VERSION 5.8 ;
BUSBITCHARS "[]" ;
DIVIDERCHAR "/" ;
UNITS
    DATABASE MICRONS 1000 ;
END UNITS

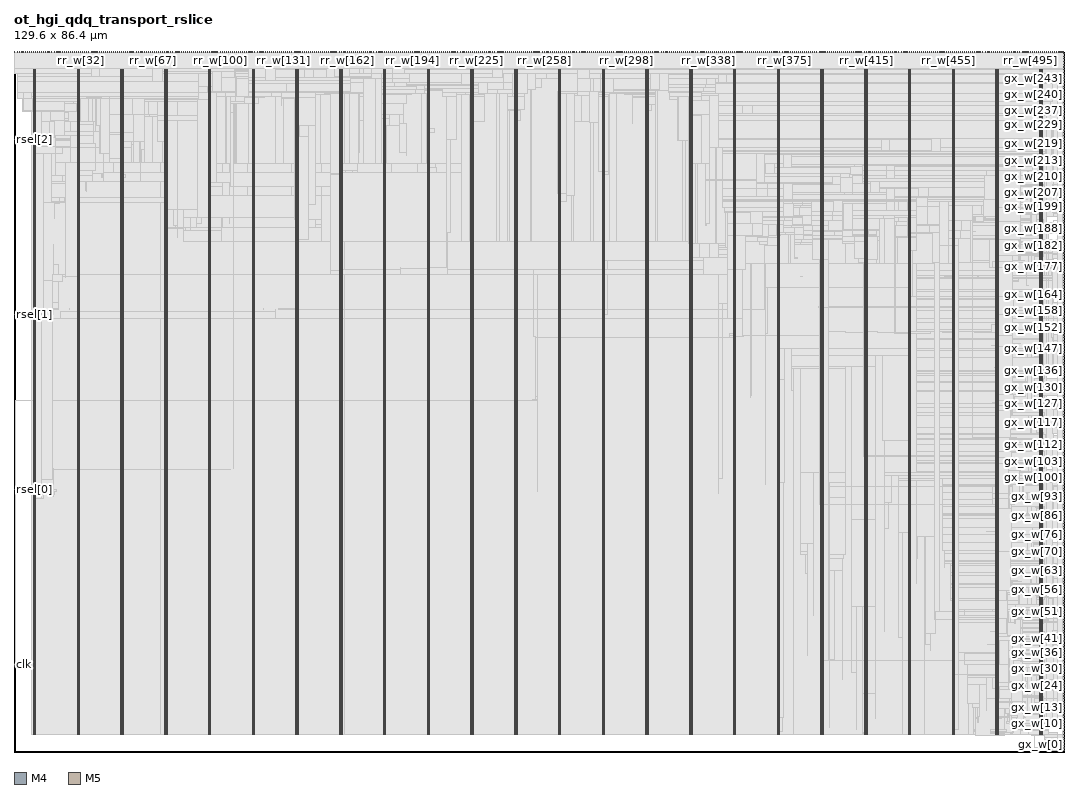
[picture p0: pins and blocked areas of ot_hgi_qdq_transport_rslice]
MACRO ot_hgi_qdq_transport_rslice
  FOREIGN ot_hgi_qdq_transport_rslice 0 0 ;
  CLASS BLOCK ;
  SIZE 129.6 BY 86.4 ;
  PIN clk
    DIRECTION INPUT ;
    USE SIGNAL ;
    PORT
      LAYER M4 ;
        RECT  0 10.8 0.084 10.824 ;
    END
    PORT
      LAYER M4 ;
        RECT  0.06 10.8 0.227 10.824 ;
    END
  END clk
  PIN gx_w[0]
    DIRECTION OUTPUT ;
    USE SIGNAL ;
    PORT
      LAYER M4 ;
        RECT  129.516 0.144 129.6 0.168 ;
    END
  END gx_w[0]
  PIN gx_w[100]
    DIRECTION OUTPUT ;
    USE SIGNAL ;
    PORT
      LAYER M4 ;
        RECT  129.516 33.888 129.6 33.912 ;
    END
  END gx_w[100]
  PIN gx_w[101]
    DIRECTION OUTPUT ;
    USE SIGNAL ;
    PORT
      LAYER M4 ;
        RECT  129.516 34.224 129.6 34.248 ;
    END
  END gx_w[101]
  PIN gx_w[102]
    DIRECTION OUTPUT ;
    USE SIGNAL ;
    PORT
      LAYER M4 ;
        RECT  129.516 34.56 129.6 34.584 ;
    END
  END gx_w[102]
  PIN gx_w[103]
    DIRECTION OUTPUT ;
    USE SIGNAL ;
    PORT
      LAYER M4 ;
        RECT  129.516 34.896 129.6 34.92 ;
    END
  END gx_w[103]
  PIN gx_w[104]
    DIRECTION OUTPUT ;
    USE SIGNAL ;
    PORT
      LAYER M4 ;
        RECT  129.516 35.28 129.6 35.304 ;
    END
  END gx_w[104]
  PIN gx_w[105]
    DIRECTION OUTPUT ;
    USE SIGNAL ;
    PORT
      LAYER M4 ;
        RECT  129.516 35.616 129.6 35.64 ;
    END
  END gx_w[105]
  PIN gx_w[106]
    DIRECTION OUTPUT ;
    USE SIGNAL ;
    PORT
      LAYER M4 ;
        RECT  129.516 35.952 129.6 35.976 ;
    END
  END gx_w[106]
  PIN gx_w[107]
    DIRECTION OUTPUT ;
    USE SIGNAL ;
    PORT
      LAYER M4 ;
        RECT  129.516 36.288 129.6 36.312 ;
    END
  END gx_w[107]
  PIN gx_w[108]
    DIRECTION OUTPUT ;
    USE SIGNAL ;
    PORT
      LAYER M4 ;
        RECT  129.516 36.624 129.6 36.648 ;
    END
  END gx_w[108]
  PIN gx_w[109]
    DIRECTION OUTPUT ;
    USE SIGNAL ;
    PORT
      LAYER M4 ;
        RECT  129.516 36.96 129.6 36.984 ;
    END
  END gx_w[109]
  PIN gx_w[10]
    DIRECTION OUTPUT ;
    USE SIGNAL ;
    PORT
      LAYER M4 ;
        RECT  129.516 3.552 129.6 3.576 ;
    END
  END gx_w[10]
  PIN gx_w[110]
    DIRECTION OUTPUT ;
    USE SIGNAL ;
    PORT
      LAYER M4 ;
        RECT  129.516 37.296 129.6 37.32 ;
    END
  END gx_w[110]
  PIN gx_w[111]
    DIRECTION OUTPUT ;
    USE SIGNAL ;
    PORT
      LAYER M4 ;
        RECT  129.516 37.632 129.6 37.656 ;
    END
  END gx_w[111]
  PIN gx_w[112]
    DIRECTION OUTPUT ;
    USE SIGNAL ;
    PORT
      LAYER M4 ;
        RECT  129.516 37.968 129.6 37.992 ;
    END
  END gx_w[112]
  PIN gx_w[113]
    DIRECTION OUTPUT ;
    USE SIGNAL ;
    PORT
      LAYER M4 ;
        RECT  129.516 38.304 129.6 38.328 ;
    END
  END gx_w[113]
  PIN gx_w[114]
    DIRECTION OUTPUT ;
    USE SIGNAL ;
    PORT
      LAYER M4 ;
        RECT  129.516 38.64 129.6 38.664 ;
    END
  END gx_w[114]
  PIN gx_w[115]
    DIRECTION OUTPUT ;
    USE SIGNAL ;
    PORT
      LAYER M4 ;
        RECT  129.516 38.976 129.6 39 ;
    END
  END gx_w[115]
  PIN gx_w[116]
    DIRECTION OUTPUT ;
    USE SIGNAL ;
    PORT
      LAYER M4 ;
        RECT  129.516 39.312 129.6 39.336 ;
    END
  END gx_w[116]
  PIN gx_w[117]
    DIRECTION OUTPUT ;
    USE SIGNAL ;
    PORT
      LAYER M4 ;
        RECT  129.516 39.648 129.6 39.672 ;
    END
  END gx_w[117]
  PIN gx_w[118]
    DIRECTION OUTPUT ;
    USE SIGNAL ;
    PORT
      LAYER M4 ;
        RECT  129.516 39.984 129.6 40.008 ;
    END
  END gx_w[118]
  PIN gx_w[119]
    DIRECTION OUTPUT ;
    USE SIGNAL ;
    PORT
      LAYER M4 ;
        RECT  129.516 40.32 129.6 40.344 ;
    END
  END gx_w[119]
  PIN gx_w[11]
    DIRECTION OUTPUT ;
    USE SIGNAL ;
    PORT
      LAYER M4 ;
        RECT  129.516 3.888 129.6 3.912 ;
    END
  END gx_w[11]
  PIN gx_w[120]
    DIRECTION OUTPUT ;
    USE SIGNAL ;
    PORT
      LAYER M4 ;
        RECT  129.516 40.656 129.6 40.68 ;
    END
  END gx_w[120]
  PIN gx_w[121]
    DIRECTION OUTPUT ;
    USE SIGNAL ;
    PORT
      LAYER M4 ;
        RECT  129.516 40.992 129.6 41.016 ;
    END
  END gx_w[121]
  PIN gx_w[122]
    DIRECTION OUTPUT ;
    USE SIGNAL ;
    PORT
      LAYER M4 ;
        RECT  129.516 41.328 129.6 41.352 ;
    END
  END gx_w[122]
  PIN gx_w[123]
    DIRECTION OUTPUT ;
    USE SIGNAL ;
    PORT
      LAYER M4 ;
        RECT  129.516 41.664 129.6 41.688 ;
    END
  END gx_w[123]
  PIN gx_w[124]
    DIRECTION OUTPUT ;
    USE SIGNAL ;
    PORT
      LAYER M4 ;
        RECT  129.516 42 129.6 42.024 ;
    END
  END gx_w[124]
  PIN gx_w[125]
    DIRECTION OUTPUT ;
    USE SIGNAL ;
    PORT
      LAYER M4 ;
        RECT  129.516 42.336 129.6 42.36 ;
    END
  END gx_w[125]
  PIN gx_w[126]
    DIRECTION OUTPUT ;
    USE SIGNAL ;
    PORT
      LAYER M4 ;
        RECT  129.516 42.672 129.6 42.696 ;
    END
  END gx_w[126]
  PIN gx_w[127]
    DIRECTION OUTPUT ;
    USE SIGNAL ;
    PORT
      LAYER M4 ;
        RECT  129.516 43.008 129.6 43.032 ;
    END
  END gx_w[127]
  PIN gx_w[128]
    DIRECTION OUTPUT ;
    USE SIGNAL ;
    PORT
      LAYER M4 ;
        RECT  129.516 43.344 129.6 43.368 ;
    END
  END gx_w[128]
  PIN gx_w[129]
    DIRECTION OUTPUT ;
    USE SIGNAL ;
    PORT
      LAYER M4 ;
        RECT  129.516 43.68 129.6 43.704 ;
    END
  END gx_w[129]
  PIN gx_w[12]
    DIRECTION OUTPUT ;
    USE SIGNAL ;
    PORT
      LAYER M4 ;
        RECT  129.516 4.224 129.6 4.248 ;
    END
  END gx_w[12]
  PIN gx_w[130]
    DIRECTION OUTPUT ;
    USE SIGNAL ;
    PORT
      LAYER M4 ;
        RECT  129.516 44.016 129.6 44.04 ;
    END
  END gx_w[130]
  PIN gx_w[131]
    DIRECTION OUTPUT ;
    USE SIGNAL ;
    PORT
      LAYER M4 ;
        RECT  129.516 44.352 129.6 44.376 ;
    END
  END gx_w[131]
  PIN gx_w[132]
    DIRECTION OUTPUT ;
    USE SIGNAL ;
    PORT
      LAYER M4 ;
        RECT  129.516 44.688 129.6 44.712 ;
    END
  END gx_w[132]
  PIN gx_w[133]
    DIRECTION OUTPUT ;
    USE SIGNAL ;
    PORT
      LAYER M4 ;
        RECT  129.516 45.024 129.6 45.048 ;
    END
  END gx_w[133]
  PIN gx_w[134]
    DIRECTION OUTPUT ;
    USE SIGNAL ;
    PORT
      LAYER M4 ;
        RECT  129.516 45.36 129.6 45.384 ;
    END
  END gx_w[134]
  PIN gx_w[135]
    DIRECTION OUTPUT ;
    USE SIGNAL ;
    PORT
      LAYER M4 ;
        RECT  129.516 45.696 129.6 45.72 ;
    END
  END gx_w[135]
  PIN gx_w[136]
    DIRECTION OUTPUT ;
    USE SIGNAL ;
    PORT
      LAYER M4 ;
        RECT  129.516 46.08 129.6 46.104 ;
    END
  END gx_w[136]
  PIN gx_w[137]
    DIRECTION OUTPUT ;
    USE SIGNAL ;
    PORT
      LAYER M4 ;
        RECT  129.516 46.416 129.6 46.44 ;
    END
  END gx_w[137]
  PIN gx_w[138]
    DIRECTION OUTPUT ;
    USE SIGNAL ;
    PORT
      LAYER M4 ;
        RECT  129.516 46.752 129.6 46.776 ;
    END
  END gx_w[138]
  PIN gx_w[139]
    DIRECTION OUTPUT ;
    USE SIGNAL ;
    PORT
      LAYER M4 ;
        RECT  129.516 47.088 129.6 47.112 ;
    END
  END gx_w[139]
  PIN gx_w[13]
    DIRECTION OUTPUT ;
    USE SIGNAL ;
    PORT
      LAYER M4 ;
        RECT  129.516 4.56 129.6 4.584 ;
    END
  END gx_w[13]
  PIN gx_w[140]
    DIRECTION OUTPUT ;
    USE SIGNAL ;
    PORT
      LAYER M4 ;
        RECT  129.516 47.424 129.6 47.448 ;
    END
  END gx_w[140]
  PIN gx_w[141]
    DIRECTION OUTPUT ;
    USE SIGNAL ;
    PORT
      LAYER M4 ;
        RECT  129.516 47.76 129.6 47.784 ;
    END
  END gx_w[141]
  PIN gx_w[142]
    DIRECTION OUTPUT ;
    USE SIGNAL ;
    PORT
      LAYER M4 ;
        RECT  129.516 48.096 129.6 48.12 ;
    END
  END gx_w[142]
  PIN gx_w[143]
    DIRECTION OUTPUT ;
    USE SIGNAL ;
    PORT
      LAYER M4 ;
        RECT  129.516 48.432 129.6 48.456 ;
    END
  END gx_w[143]
  PIN gx_w[144]
    DIRECTION OUTPUT ;
    USE SIGNAL ;
    PORT
      LAYER M4 ;
        RECT  129.516 48.768 129.6 48.792 ;
    END
  END gx_w[144]
  PIN gx_w[145]
    DIRECTION OUTPUT ;
    USE SIGNAL ;
    PORT
      LAYER M4 ;
        RECT  129.516 49.104 129.6 49.128 ;
    END
  END gx_w[145]
  PIN gx_w[146]
    DIRECTION OUTPUT ;
    USE SIGNAL ;
    PORT
      LAYER M4 ;
        RECT  129.516 49.44 129.6 49.464 ;
    END
  END gx_w[146]
  PIN gx_w[147]
    DIRECTION OUTPUT ;
    USE SIGNAL ;
    PORT
      LAYER M4 ;
        RECT  129.516 49.776 129.6 49.8 ;
    END
  END gx_w[147]
  PIN gx_w[148]
    DIRECTION OUTPUT ;
    USE SIGNAL ;
    PORT
      LAYER M4 ;
        RECT  129.516 50.112 129.6 50.136 ;
    END
  END gx_w[148]
  PIN gx_w[149]
    DIRECTION OUTPUT ;
    USE SIGNAL ;
    PORT
      LAYER M4 ;
        RECT  129.516 50.448 129.6 50.472 ;
    END
  END gx_w[149]
  PIN gx_w[14]
    DIRECTION OUTPUT ;
    USE SIGNAL ;
    PORT
      LAYER M4 ;
        RECT  129.516 4.896 129.6 4.92 ;
    END
  END gx_w[14]
  PIN gx_w[150]
    DIRECTION OUTPUT ;
    USE SIGNAL ;
    PORT
      LAYER M4 ;
        RECT  129.516 50.784 129.6 50.808 ;
    END
  END gx_w[150]
  PIN gx_w[151]
    DIRECTION OUTPUT ;
    USE SIGNAL ;
    PORT
      LAYER M4 ;
        RECT  129.516 51.12 129.6 51.144 ;
    END
  END gx_w[151]
  PIN gx_w[152]
    DIRECTION OUTPUT ;
    USE SIGNAL ;
    PORT
      LAYER M4 ;
        RECT  129.516 51.456 129.6 51.48 ;
    END
  END gx_w[152]
  PIN gx_w[153]
    DIRECTION OUTPUT ;
    USE SIGNAL ;
    PORT
      LAYER M4 ;
        RECT  129.516 51.792 129.6 51.816 ;
    END
  END gx_w[153]
  PIN gx_w[154]
    DIRECTION OUTPUT ;
    USE SIGNAL ;
    PORT
      LAYER M4 ;
        RECT  129.516 52.128 129.6 52.152 ;
    END
  END gx_w[154]
  PIN gx_w[155]
    DIRECTION OUTPUT ;
    USE SIGNAL ;
    PORT
      LAYER M4 ;
        RECT  129.516 52.464 129.6 52.488 ;
    END
  END gx_w[155]
  PIN gx_w[156]
    DIRECTION OUTPUT ;
    USE SIGNAL ;
    PORT
      LAYER M4 ;
        RECT  129.516 52.8 129.6 52.824 ;
    END
  END gx_w[156]
  PIN gx_w[157]
    DIRECTION OUTPUT ;
    USE SIGNAL ;
    PORT
      LAYER M4 ;
        RECT  129.516 53.136 129.6 53.16 ;
    END
  END gx_w[157]
  PIN gx_w[158]
    DIRECTION OUTPUT ;
    USE SIGNAL ;
    PORT
      LAYER M4 ;
        RECT  129.516 53.472 129.6 53.496 ;
    END
  END gx_w[158]
  PIN gx_w[159]
    DIRECTION OUTPUT ;
    USE SIGNAL ;
    PORT
      LAYER M4 ;
        RECT  129.516 53.808 129.6 53.832 ;
    END
  END gx_w[159]
  PIN gx_w[15]
    DIRECTION OUTPUT ;
    USE SIGNAL ;
    PORT
      LAYER M4 ;
        RECT  129.516 5.232 129.6 5.256 ;
    END
  END gx_w[15]
  PIN gx_w[160]
    DIRECTION OUTPUT ;
    USE SIGNAL ;
    PORT
      LAYER M4 ;
        RECT  129.516 54.144 129.6 54.168 ;
    END
  END gx_w[160]
  PIN gx_w[161]
    DIRECTION OUTPUT ;
    USE SIGNAL ;
    PORT
      LAYER M4 ;
        RECT  129.516 54.48 129.6 54.504 ;
    END
  END gx_w[161]
  PIN gx_w[162]
    DIRECTION OUTPUT ;
    USE SIGNAL ;
    PORT
      LAYER M4 ;
        RECT  129.516 54.816 129.6 54.84 ;
    END
  END gx_w[162]
  PIN gx_w[163]
    DIRECTION OUTPUT ;
    USE SIGNAL ;
    PORT
      LAYER M4 ;
        RECT  129.516 55.152 129.6 55.176 ;
    END
  END gx_w[163]
  PIN gx_w[164]
    DIRECTION OUTPUT ;
    USE SIGNAL ;
    PORT
      LAYER M4 ;
        RECT  129.516 55.488 129.6 55.512 ;
    END
  END gx_w[164]
  PIN gx_w[165]
    DIRECTION OUTPUT ;
    USE SIGNAL ;
    PORT
      LAYER M4 ;
        RECT  129.516 55.824 129.6 55.848 ;
    END
  END gx_w[165]
  PIN gx_w[166]
    DIRECTION OUTPUT ;
    USE SIGNAL ;
    PORT
      LAYER M4 ;
        RECT  129.516 56.16 129.6 56.184 ;
    END
  END gx_w[166]
  PIN gx_w[167]
    DIRECTION OUTPUT ;
    USE SIGNAL ;
    PORT
      LAYER M4 ;
        RECT  129.516 56.496 129.6 56.52 ;
    END
  END gx_w[167]
  PIN gx_w[168]
    DIRECTION OUTPUT ;
    USE SIGNAL ;
    PORT
      LAYER M4 ;
        RECT  129.516 56.88 129.6 56.904 ;
    END
  END gx_w[168]
  PIN gx_w[169]
    DIRECTION OUTPUT ;
    USE SIGNAL ;
    PORT
      LAYER M4 ;
        RECT  129.516 57.216 129.6 57.24 ;
    END
  END gx_w[169]
  PIN gx_w[16]
    DIRECTION OUTPUT ;
    USE SIGNAL ;
    PORT
      LAYER M4 ;
        RECT  129.516 5.568 129.6 5.592 ;
    END
  END gx_w[16]
  PIN gx_w[170]
    DIRECTION OUTPUT ;
    USE SIGNAL ;
    PORT
      LAYER M4 ;
        RECT  129.516 57.552 129.6 57.576 ;
    END
  END gx_w[170]
  PIN gx_w[171]
    DIRECTION OUTPUT ;
    USE SIGNAL ;
    PORT
      LAYER M4 ;
        RECT  129.516 57.888 129.6 57.912 ;
    END
  END gx_w[171]
  PIN gx_w[172]
    DIRECTION OUTPUT ;
    USE SIGNAL ;
    PORT
      LAYER M4 ;
        RECT  129.516 58.224 129.6 58.248 ;
    END
  END gx_w[172]
  PIN gx_w[173]
    DIRECTION OUTPUT ;
    USE SIGNAL ;
    PORT
      LAYER M4 ;
        RECT  129.516 58.56 129.6 58.584 ;
    END
  END gx_w[173]
  PIN gx_w[174]
    DIRECTION OUTPUT ;
    USE SIGNAL ;
    PORT
      LAYER M4 ;
        RECT  129.516 58.896 129.6 58.92 ;
    END
  END gx_w[174]
  PIN gx_w[175]
    DIRECTION OUTPUT ;
    USE SIGNAL ;
    PORT
      LAYER M4 ;
        RECT  129.516 59.232 129.6 59.256 ;
    END
  END gx_w[175]
  PIN gx_w[176]
    DIRECTION OUTPUT ;
    USE SIGNAL ;
    PORT
      LAYER M4 ;
        RECT  129.516 59.568 129.6 59.592 ;
    END
  END gx_w[176]
  PIN gx_w[177]
    DIRECTION OUTPUT ;
    USE SIGNAL ;
    PORT
      LAYER M4 ;
        RECT  129.516 59.904 129.6 59.928 ;
    END
  END gx_w[177]
  PIN gx_w[178]
    DIRECTION OUTPUT ;
    USE SIGNAL ;
    PORT
      LAYER M4 ;
        RECT  129.516 60.24 129.6 60.264 ;
    END
  END gx_w[178]
  PIN gx_w[179]
    DIRECTION OUTPUT ;
    USE SIGNAL ;
    PORT
      LAYER M4 ;
        RECT  129.516 60.576 129.6 60.6 ;
    END
  END gx_w[179]
  PIN gx_w[17]
    DIRECTION OUTPUT ;
    USE SIGNAL ;
    PORT
      LAYER M4 ;
        RECT  129.516 5.904 129.6 5.928 ;
    END
  END gx_w[17]
  PIN gx_w[180]
    DIRECTION OUTPUT ;
    USE SIGNAL ;
    PORT
      LAYER M4 ;
        RECT  129.516 60.912 129.6 60.936 ;
    END
  END gx_w[180]
  PIN gx_w[181]
    DIRECTION OUTPUT ;
    USE SIGNAL ;
    PORT
      LAYER M4 ;
        RECT  129.516 61.248 129.6 61.272 ;
    END
  END gx_w[181]
  PIN gx_w[182]
    DIRECTION OUTPUT ;
    USE SIGNAL ;
    PORT
      LAYER M4 ;
        RECT  129.516 61.584 129.6 61.608 ;
    END
  END gx_w[182]
  PIN gx_w[183]
    DIRECTION OUTPUT ;
    USE SIGNAL ;
    PORT
      LAYER M4 ;
        RECT  129.516 61.92 129.6 61.944 ;
    END
  END gx_w[183]
  PIN gx_w[184]
    DIRECTION OUTPUT ;
    USE SIGNAL ;
    PORT
      LAYER M4 ;
        RECT  129.516 62.256 129.6 62.28 ;
    END
  END gx_w[184]
  PIN gx_w[185]
    DIRECTION OUTPUT ;
    USE SIGNAL ;
    PORT
      LAYER M4 ;
        RECT  129.516 62.592 129.6 62.616 ;
    END
  END gx_w[185]
  PIN gx_w[186]
    DIRECTION OUTPUT ;
    USE SIGNAL ;
    PORT
      LAYER M4 ;
        RECT  129.516 62.928 129.6 62.952 ;
    END
  END gx_w[186]
  PIN gx_w[187]
    DIRECTION OUTPUT ;
    USE SIGNAL ;
    PORT
      LAYER M4 ;
        RECT  129.516 63.264 129.6 63.288 ;
    END
  END gx_w[187]
  PIN gx_w[188]
    DIRECTION OUTPUT ;
    USE SIGNAL ;
    PORT
      LAYER M4 ;
        RECT  129.516 63.6 129.6 63.624 ;
    END
  END gx_w[188]
  PIN gx_w[189]
    DIRECTION OUTPUT ;
    USE SIGNAL ;
    PORT
      LAYER M4 ;
        RECT  129.516 63.936 129.6 63.96 ;
    END
  END gx_w[189]
  PIN gx_w[18]
    DIRECTION OUTPUT ;
    USE SIGNAL ;
    PORT
      LAYER M4 ;
        RECT  129.516 6.24 129.6 6.264 ;
    END
  END gx_w[18]
  PIN gx_w[190]
    DIRECTION OUTPUT ;
    USE SIGNAL ;
    PORT
      LAYER M4 ;
        RECT  129.516 64.272 129.6 64.296 ;
    END
  END gx_w[190]
  PIN gx_w[191]
    DIRECTION OUTPUT ;
    USE SIGNAL ;
    PORT
      LAYER M4 ;
        RECT  129.516 64.608 129.6 64.632 ;
    END
  END gx_w[191]
  PIN gx_w[192]
    DIRECTION OUTPUT ;
    USE SIGNAL ;
    PORT
      LAYER M4 ;
        RECT  129.516 64.944 129.6 64.968 ;
    END
  END gx_w[192]
  PIN gx_w[193]
    DIRECTION OUTPUT ;
    USE SIGNAL ;
    PORT
      LAYER M4 ;
        RECT  129.516 65.28 129.6 65.304 ;
    END
  END gx_w[193]
  PIN gx_w[194]
    DIRECTION OUTPUT ;
    USE SIGNAL ;
    PORT
      LAYER M4 ;
        RECT  129.516 65.616 129.6 65.64 ;
    END
  END gx_w[194]
  PIN gx_w[195]
    DIRECTION OUTPUT ;
    USE SIGNAL ;
    PORT
      LAYER M4 ;
        RECT  129.516 65.952 129.6 65.976 ;
    END
  END gx_w[195]
  PIN gx_w[196]
    DIRECTION OUTPUT ;
    USE SIGNAL ;
    PORT
      LAYER M4 ;
        RECT  129.516 66.288 129.6 66.312 ;
    END
  END gx_w[196]
  PIN gx_w[197]
    DIRECTION OUTPUT ;
    USE SIGNAL ;
    PORT
      LAYER M4 ;
        RECT  129.516 66.624 129.6 66.648 ;
    END
  END gx_w[197]
  PIN gx_w[198]
    DIRECTION OUTPUT ;
    USE SIGNAL ;
    PORT
      LAYER M4 ;
        RECT  129.516 66.96 129.6 66.984 ;
    END
  END gx_w[198]
  PIN gx_w[199]
    DIRECTION OUTPUT ;
    USE SIGNAL ;
    PORT
      LAYER M4 ;
        RECT  129.516 67.296 129.6 67.32 ;
    END
  END gx_w[199]
  PIN gx_w[19]
    DIRECTION OUTPUT ;
    USE SIGNAL ;
    PORT
      LAYER M4 ;
        RECT  129.516 6.576 129.6 6.6 ;
    END
  END gx_w[19]
  PIN gx_w[1]
    DIRECTION OUTPUT ;
    USE SIGNAL ;
    PORT
      LAYER M4 ;
        RECT  129.516 0.48 129.6 0.504 ;
    END
  END gx_w[1]
  PIN gx_w[200]
    DIRECTION OUTPUT ;
    USE SIGNAL ;
    PORT
      LAYER M4 ;
        RECT  129.516 67.68 129.6 67.704 ;
    END
  END gx_w[200]
  PIN gx_w[201]
    DIRECTION OUTPUT ;
    USE SIGNAL ;
    PORT
      LAYER M4 ;
        RECT  129.516 68.016 129.6 68.04 ;
    END
  END gx_w[201]
  PIN gx_w[202]
    DIRECTION OUTPUT ;
    USE SIGNAL ;
    PORT
      LAYER M4 ;
        RECT  129.516 68.352 129.6 68.376 ;
    END
  END gx_w[202]
  PIN gx_w[203]
    DIRECTION OUTPUT ;
    USE SIGNAL ;
    PORT
      LAYER M4 ;
        RECT  129.516 68.688 129.6 68.712 ;
    END
  END gx_w[203]
  PIN gx_w[204]
    DIRECTION OUTPUT ;
    USE SIGNAL ;
    PORT
      LAYER M4 ;
        RECT  129.516 69.024 129.6 69.048 ;
    END
  END gx_w[204]
  PIN gx_w[205]
    DIRECTION OUTPUT ;
    USE SIGNAL ;
    PORT
      LAYER M4 ;
        RECT  129.516 69.36 129.6 69.384 ;
    END
  END gx_w[205]
  PIN gx_w[206]
    DIRECTION OUTPUT ;
    USE SIGNAL ;
    PORT
      LAYER M4 ;
        RECT  129.516 69.696 129.6 69.72 ;
    END
  END gx_w[206]
  PIN gx_w[207]
    DIRECTION OUTPUT ;
    USE SIGNAL ;
    PORT
      LAYER M4 ;
        RECT  129.516 70.032 129.6 70.056 ;
    END
  END gx_w[207]
  PIN gx_w[208]
    DIRECTION OUTPUT ;
    USE SIGNAL ;
    PORT
      LAYER M4 ;
        RECT  129.516 70.368 129.6 70.392 ;
    END
  END gx_w[208]
  PIN gx_w[209]
    DIRECTION OUTPUT ;
    USE SIGNAL ;
    PORT
      LAYER M4 ;
        RECT  129.516 70.704 129.6 70.728 ;
    END
  END gx_w[209]
  PIN gx_w[20]
    DIRECTION OUTPUT ;
    USE SIGNAL ;
    PORT
      LAYER M4 ;
        RECT  129.516 6.912 129.6 6.936 ;
    END
  END gx_w[20]
  PIN gx_w[210]
    DIRECTION OUTPUT ;
    USE SIGNAL ;
    PORT
      LAYER M4 ;
        RECT  129.516 71.04 129.6 71.064 ;
    END
  END gx_w[210]
  PIN gx_w[211]
    DIRECTION OUTPUT ;
    USE SIGNAL ;
    PORT
      LAYER M4 ;
        RECT  129.516 71.376 129.6 71.4 ;
    END
  END gx_w[211]
  PIN gx_w[212]
    DIRECTION OUTPUT ;
    USE SIGNAL ;
    PORT
      LAYER M4 ;
        RECT  129.516 71.712 129.6 71.736 ;
    END
  END gx_w[212]
  PIN gx_w[213]
    DIRECTION OUTPUT ;
    USE SIGNAL ;
    PORT
      LAYER M4 ;
        RECT  129.516 72.048 129.6 72.072 ;
    END
  END gx_w[213]
  PIN gx_w[214]
    DIRECTION OUTPUT ;
    USE SIGNAL ;
    PORT
      LAYER M4 ;
        RECT  129.516 72.384 129.6 72.408 ;
    END
  END gx_w[214]
  PIN gx_w[215]
    DIRECTION OUTPUT ;
    USE SIGNAL ;
    PORT
      LAYER M4 ;
        RECT  129.516 72.72 129.6 72.744 ;
    END
  END gx_w[215]
  PIN gx_w[216]
    DIRECTION OUTPUT ;
    USE SIGNAL ;
    PORT
      LAYER M4 ;
        RECT  129.516 73.056 129.6 73.08 ;
    END
  END gx_w[216]
  PIN gx_w[217]
    DIRECTION OUTPUT ;
    USE SIGNAL ;
    PORT
      LAYER M4 ;
        RECT  129.516 73.392 129.6 73.416 ;
    END
  END gx_w[217]
  PIN gx_w[218]
    DIRECTION OUTPUT ;
    USE SIGNAL ;
    PORT
      LAYER M4 ;
        RECT  129.516 73.728 129.6 73.752 ;
    END
  END gx_w[218]
  PIN gx_w[219]
    DIRECTION OUTPUT ;
    USE SIGNAL ;
    PORT
      LAYER M4 ;
        RECT  129.516 74.064 129.6 74.088 ;
    END
  END gx_w[219]
  PIN gx_w[21]
    DIRECTION OUTPUT ;
    USE SIGNAL ;
    PORT
      LAYER M4 ;
        RECT  129.516 7.248 129.6 7.272 ;
    END
  END gx_w[21]
  PIN gx_w[220]
    DIRECTION OUTPUT ;
    USE SIGNAL ;
    PORT
      LAYER M4 ;
        RECT  129.516 74.4 129.6 74.424 ;
    END
  END gx_w[220]
  PIN gx_w[221]
    DIRECTION OUTPUT ;
    USE SIGNAL ;
    PORT
      LAYER M4 ;
        RECT  129.516 74.736 129.6 74.76 ;
    END
  END gx_w[221]
  PIN gx_w[222]
    DIRECTION OUTPUT ;
    USE SIGNAL ;
    PORT
      LAYER M4 ;
        RECT  129.516 75.072 129.6 75.096 ;
    END
  END gx_w[222]
  PIN gx_w[223]
    DIRECTION OUTPUT ;
    USE SIGNAL ;
    PORT
      LAYER M4 ;
        RECT  129.516 75.408 129.6 75.432 ;
    END
  END gx_w[223]
  PIN gx_w[224]
    DIRECTION OUTPUT ;
    USE SIGNAL ;
    PORT
      LAYER M4 ;
        RECT  129.516 75.744 129.6 75.768 ;
    END
  END gx_w[224]
  PIN gx_w[225]
    DIRECTION OUTPUT ;
    USE SIGNAL ;
    PORT
      LAYER M4 ;
        RECT  129.516 76.08 129.6 76.104 ;
    END
  END gx_w[225]
  PIN gx_w[226]
    DIRECTION OUTPUT ;
    USE SIGNAL ;
    PORT
      LAYER M4 ;
        RECT  129.516 76.416 129.6 76.44 ;
    END
  END gx_w[226]
  PIN gx_w[227]
    DIRECTION OUTPUT ;
    USE SIGNAL ;
    PORT
      LAYER M4 ;
        RECT  129.516 76.752 129.6 76.776 ;
    END
  END gx_w[227]
  PIN gx_w[228]
    DIRECTION OUTPUT ;
    USE SIGNAL ;
    PORT
      LAYER M4 ;
        RECT  129.516 77.088 129.6 77.112 ;
    END
  END gx_w[228]
  PIN gx_w[229]
    DIRECTION OUTPUT ;
    USE SIGNAL ;
    PORT
      LAYER M4 ;
        RECT  129.516 77.424 129.6 77.448 ;
    END
  END gx_w[229]
  PIN gx_w[22]
    DIRECTION OUTPUT ;
    USE SIGNAL ;
    PORT
      LAYER M4 ;
        RECT  129.516 7.584 129.6 7.608 ;
    END
  END gx_w[22]
  PIN gx_w[230]
    DIRECTION OUTPUT ;
    USE SIGNAL ;
    PORT
      LAYER M4 ;
        RECT  129.516 77.76 129.6 77.784 ;
    END
  END gx_w[230]
  PIN gx_w[231]
    DIRECTION OUTPUT ;
    USE SIGNAL ;
    PORT
      LAYER M4 ;
        RECT  129.516 78.096 129.6 78.12 ;
    END
  END gx_w[231]
  PIN gx_w[232]
    DIRECTION OUTPUT ;
    USE SIGNAL ;
    PORT
      LAYER M4 ;
        RECT  129.516 78.48 129.6 78.504 ;
    END
  END gx_w[232]
  PIN gx_w[233]
    DIRECTION OUTPUT ;
    USE SIGNAL ;
    PORT
      LAYER M4 ;
        RECT  129.516 78.816 129.6 78.84 ;
    END
  END gx_w[233]
  PIN gx_w[234]
    DIRECTION OUTPUT ;
    USE SIGNAL ;
    PORT
      LAYER M4 ;
        RECT  129.516 79.152 129.6 79.176 ;
    END
  END gx_w[234]
  PIN gx_w[235]
    DIRECTION OUTPUT ;
    USE SIGNAL ;
    PORT
      LAYER M4 ;
        RECT  129.516 79.488 129.6 79.512 ;
    END
  END gx_w[235]
  PIN gx_w[236]
    DIRECTION OUTPUT ;
    USE SIGNAL ;
    PORT
      LAYER M4 ;
        RECT  129.516 79.824 129.6 79.848 ;
    END
  END gx_w[236]
  PIN gx_w[237]
    DIRECTION OUTPUT ;
    USE SIGNAL ;
    PORT
      LAYER M4 ;
        RECT  129.516 80.16 129.6 80.184 ;
    END
  END gx_w[237]
  PIN gx_w[238]
    DIRECTION OUTPUT ;
    USE SIGNAL ;
    PORT
      LAYER M4 ;
        RECT  129.516 80.496 129.6 80.52 ;
    END
  END gx_w[238]
  PIN gx_w[239]
    DIRECTION OUTPUT ;
    USE SIGNAL ;
    PORT
      LAYER M4 ;
        RECT  129.516 80.832 129.6 80.856 ;
    END
  END gx_w[239]
  PIN gx_w[23]
    DIRECTION OUTPUT ;
    USE SIGNAL ;
    PORT
      LAYER M4 ;
        RECT  129.516 7.92 129.6 7.944 ;
    END
  END gx_w[23]
  PIN gx_w[240]
    DIRECTION OUTPUT ;
    USE SIGNAL ;
    PORT
      LAYER M4 ;
        RECT  129.516 81.168 129.6 81.192 ;
    END
  END gx_w[240]
  PIN gx_w[241]
    DIRECTION OUTPUT ;
    USE SIGNAL ;
    PORT
      LAYER M4 ;
        RECT  129.516 81.504 129.6 81.528 ;
    END
  END gx_w[241]
  PIN gx_w[242]
    DIRECTION OUTPUT ;
    USE SIGNAL ;
    PORT
      LAYER M4 ;
        RECT  129.516 81.84 129.6 81.864 ;
    END
  END gx_w[242]
  PIN gx_w[243]
    DIRECTION OUTPUT ;
    USE SIGNAL ;
    PORT
      LAYER M4 ;
        RECT  129.516 82.176 129.6 82.2 ;
    END
  END gx_w[243]
  PIN gx_w[244]
    DIRECTION OUTPUT ;
    USE SIGNAL ;
    PORT
      LAYER M4 ;
        RECT  129.516 82.512 129.6 82.536 ;
    END
  END gx_w[244]
  PIN gx_w[245]
    DIRECTION OUTPUT ;
    USE SIGNAL ;
    PORT
      LAYER M4 ;
        RECT  129.516 82.848 129.6 82.872 ;
    END
  END gx_w[245]
  PIN gx_w[246]
    DIRECTION OUTPUT ;
    USE SIGNAL ;
    PORT
      LAYER M4 ;
        RECT  129.516 83.184 129.6 83.208 ;
    END
  END gx_w[246]
  PIN gx_w[247]
    DIRECTION OUTPUT ;
    USE SIGNAL ;
    PORT
      LAYER M4 ;
        RECT  129.516 83.52 129.6 83.544 ;
    END
  END gx_w[247]
  PIN gx_w[248]
    DIRECTION OUTPUT ;
    USE SIGNAL ;
    PORT
      LAYER M4 ;
        RECT  129.516 83.856 129.6 83.88 ;
    END
  END gx_w[248]
  PIN gx_w[249]
    DIRECTION OUTPUT ;
    USE SIGNAL ;
    PORT
      LAYER M4 ;
        RECT  129.516 84.192 129.6 84.216 ;
    END
  END gx_w[249]
  PIN gx_w[24]
    DIRECTION OUTPUT ;
    USE SIGNAL ;
    PORT
      LAYER M4 ;
        RECT  129.516 8.256 129.6 8.28 ;
    END
  END gx_w[24]
  PIN gx_w[250]
    DIRECTION OUTPUT ;
    USE SIGNAL ;
    PORT
      LAYER M4 ;
        RECT  129.516 84.528 129.6 84.552 ;
    END
  END gx_w[250]
  PIN gx_w[251]
    DIRECTION OUTPUT ;
    USE SIGNAL ;
    PORT
      LAYER M4 ;
        RECT  129.516 84.864 129.6 84.888 ;
    END
  END gx_w[251]
  PIN gx_w[252]
    DIRECTION OUTPUT ;
    USE SIGNAL ;
    PORT
      LAYER M4 ;
        RECT  129.516 85.2 129.6 85.224 ;
    END
  END gx_w[252]
  PIN gx_w[253]
    DIRECTION OUTPUT ;
    USE SIGNAL ;
    PORT
      LAYER M4 ;
        RECT  129.516 85.536 129.6 85.56 ;
    END
  END gx_w[253]
  PIN gx_w[254]
    DIRECTION OUTPUT ;
    USE SIGNAL ;
    PORT
      LAYER M4 ;
        RECT  129.516 85.872 129.6 85.896 ;
    END
  END gx_w[254]
  PIN gx_w[255]
    DIRECTION OUTPUT ;
    USE SIGNAL ;
    PORT
      LAYER M4 ;
        RECT  129.516 86.208 129.6 86.232 ;
    END
  END gx_w[255]
  PIN gx_w[25]
    DIRECTION OUTPUT ;
    USE SIGNAL ;
    PORT
      LAYER M4 ;
        RECT  129.516 8.592 129.6 8.616 ;
    END
  END gx_w[25]
  PIN gx_w[26]
    DIRECTION OUTPUT ;
    USE SIGNAL ;
    PORT
      LAYER M4 ;
        RECT  129.516 8.928 129.6 8.952 ;
    END
  END gx_w[26]
  PIN gx_w[27]
    DIRECTION OUTPUT ;
    USE SIGNAL ;
    PORT
      LAYER M4 ;
        RECT  129.516 9.264 129.6 9.288 ;
    END
  END gx_w[27]
  PIN gx_w[28]
    DIRECTION OUTPUT ;
    USE SIGNAL ;
    PORT
      LAYER M4 ;
        RECT  129.516 9.6 129.6 9.624 ;
    END
  END gx_w[28]
  PIN gx_w[29]
    DIRECTION OUTPUT ;
    USE SIGNAL ;
    PORT
      LAYER M4 ;
        RECT  129.516 9.936 129.6 9.96 ;
    END
  END gx_w[29]
  PIN gx_w[2]
    DIRECTION OUTPUT ;
    USE SIGNAL ;
    PORT
      LAYER M4 ;
        RECT  129.516 0.816 129.6 0.84 ;
    END
  END gx_w[2]
  PIN gx_w[30]
    DIRECTION OUTPUT ;
    USE SIGNAL ;
    PORT
      LAYER M4 ;
        RECT  129.516 10.272 129.6 10.296 ;
    END
  END gx_w[30]
  PIN gx_w[31]
    DIRECTION OUTPUT ;
    USE SIGNAL ;
    PORT
      LAYER M4 ;
        RECT  129.516 10.608 129.6 10.632 ;
    END
  END gx_w[31]
  PIN gx_w[32]
    DIRECTION OUTPUT ;
    USE SIGNAL ;
    PORT
      LAYER M4 ;
        RECT  129.516 10.944 129.6 10.968 ;
    END
  END gx_w[32]
  PIN gx_w[33]
    DIRECTION OUTPUT ;
    USE SIGNAL ;
    PORT
      LAYER M4 ;
        RECT  129.516 11.28 129.6 11.304 ;
    END
  END gx_w[33]
  PIN gx_w[34]
    DIRECTION OUTPUT ;
    USE SIGNAL ;
    PORT
      LAYER M4 ;
        RECT  129.516 11.616 129.6 11.64 ;
    END
  END gx_w[34]
  PIN gx_w[35]
    DIRECTION OUTPUT ;
    USE SIGNAL ;
    PORT
      LAYER M4 ;
        RECT  129.516 11.952 129.6 11.976 ;
    END
  END gx_w[35]
  PIN gx_w[36]
    DIRECTION OUTPUT ;
    USE SIGNAL ;
    PORT
      LAYER M4 ;
        RECT  129.516 12.288 129.6 12.312 ;
    END
  END gx_w[36]
  PIN gx_w[37]
    DIRECTION OUTPUT ;
    USE SIGNAL ;
    PORT
      LAYER M4 ;
        RECT  129.516 12.624 129.6 12.648 ;
    END
  END gx_w[37]
  PIN gx_w[38]
    DIRECTION OUTPUT ;
    USE SIGNAL ;
    PORT
      LAYER M4 ;
        RECT  129.516 12.96 129.6 12.984 ;
    END
  END gx_w[38]
  PIN gx_w[39]
    DIRECTION OUTPUT ;
    USE SIGNAL ;
    PORT
      LAYER M4 ;
        RECT  129.516 13.296 129.6 13.32 ;
    END
  END gx_w[39]
  PIN gx_w[3]
    DIRECTION OUTPUT ;
    USE SIGNAL ;
    PORT
      LAYER M4 ;
        RECT  129.516 1.152 129.6 1.176 ;
    END
  END gx_w[3]
  PIN gx_w[40]
    DIRECTION OUTPUT ;
    USE SIGNAL ;
    PORT
      LAYER M4 ;
        RECT  129.516 13.68 129.6 13.704 ;
    END
  END gx_w[40]
  PIN gx_w[41]
    DIRECTION OUTPUT ;
    USE SIGNAL ;
    PORT
      LAYER M4 ;
        RECT  129.516 14.016 129.6 14.04 ;
    END
  END gx_w[41]
  PIN gx_w[42]
    DIRECTION OUTPUT ;
    USE SIGNAL ;
    PORT
      LAYER M4 ;
        RECT  129.516 14.352 129.6 14.376 ;
    END
  END gx_w[42]
  PIN gx_w[43]
    DIRECTION OUTPUT ;
    USE SIGNAL ;
    PORT
      LAYER M4 ;
        RECT  129.516 14.688 129.6 14.712 ;
    END
  END gx_w[43]
  PIN gx_w[44]
    DIRECTION OUTPUT ;
    USE SIGNAL ;
    PORT
      LAYER M4 ;
        RECT  129.516 15.024 129.6 15.048 ;
    END
  END gx_w[44]
  PIN gx_w[45]
    DIRECTION OUTPUT ;
    USE SIGNAL ;
    PORT
      LAYER M4 ;
        RECT  129.516 15.36 129.6 15.384 ;
    END
  END gx_w[45]
  PIN gx_w[46]
    DIRECTION OUTPUT ;
    USE SIGNAL ;
    PORT
      LAYER M4 ;
        RECT  129.516 15.696 129.6 15.72 ;
    END
  END gx_w[46]
  PIN gx_w[47]
    DIRECTION OUTPUT ;
    USE SIGNAL ;
    PORT
      LAYER M4 ;
        RECT  129.516 16.032 129.6 16.056 ;
    END
  END gx_w[47]
  PIN gx_w[48]
    DIRECTION OUTPUT ;
    USE SIGNAL ;
    PORT
      LAYER M4 ;
        RECT  129.516 16.368 129.6 16.392 ;
    END
  END gx_w[48]
  PIN gx_w[49]
    DIRECTION OUTPUT ;
    USE SIGNAL ;
    PORT
      LAYER M4 ;
        RECT  129.516 16.704 129.6 16.728 ;
    END
  END gx_w[49]
  PIN gx_w[4]
    DIRECTION OUTPUT ;
    USE SIGNAL ;
    PORT
      LAYER M4 ;
        RECT  129.516 1.488 129.6 1.512 ;
    END
  END gx_w[4]
  PIN gx_w[50]
    DIRECTION OUTPUT ;
    USE SIGNAL ;
    PORT
      LAYER M4 ;
        RECT  129.516 17.04 129.6 17.064 ;
    END
  END gx_w[50]
  PIN gx_w[51]
    DIRECTION OUTPUT ;
    USE SIGNAL ;
    PORT
      LAYER M4 ;
        RECT  129.516 17.376 129.6 17.4 ;
    END
  END gx_w[51]
  PIN gx_w[52]
    DIRECTION OUTPUT ;
    USE SIGNAL ;
    PORT
      LAYER M4 ;
        RECT  129.516 17.712 129.6 17.736 ;
    END
  END gx_w[52]
  PIN gx_w[53]
    DIRECTION OUTPUT ;
    USE SIGNAL ;
    PORT
      LAYER M4 ;
        RECT  129.516 18.048 129.6 18.072 ;
    END
  END gx_w[53]
  PIN gx_w[54]
    DIRECTION OUTPUT ;
    USE SIGNAL ;
    PORT
      LAYER M4 ;
        RECT  129.516 18.384 129.6 18.408 ;
    END
  END gx_w[54]
  PIN gx_w[55]
    DIRECTION OUTPUT ;
    USE SIGNAL ;
    PORT
      LAYER M4 ;
        RECT  129.516 18.72 129.6 18.744 ;
    END
  END gx_w[55]
  PIN gx_w[56]
    DIRECTION OUTPUT ;
    USE SIGNAL ;
    PORT
      LAYER M4 ;
        RECT  129.516 19.056 129.6 19.08 ;
    END
  END gx_w[56]
  PIN gx_w[57]
    DIRECTION OUTPUT ;
    USE SIGNAL ;
    PORT
      LAYER M4 ;
        RECT  129.516 19.392 129.6 19.416 ;
    END
  END gx_w[57]
  PIN gx_w[58]
    DIRECTION OUTPUT ;
    USE SIGNAL ;
    PORT
      LAYER M4 ;
        RECT  129.516 19.728 129.6 19.752 ;
    END
  END gx_w[58]
  PIN gx_w[59]
    DIRECTION OUTPUT ;
    USE SIGNAL ;
    PORT
      LAYER M4 ;
        RECT  129.516 20.064 129.6 20.088 ;
    END
  END gx_w[59]
  PIN gx_w[5]
    DIRECTION OUTPUT ;
    USE SIGNAL ;
    PORT
      LAYER M4 ;
        RECT  129.516 1.824 129.6 1.848 ;
    END
  END gx_w[5]
  PIN gx_w[60]
    DIRECTION OUTPUT ;
    USE SIGNAL ;
    PORT
      LAYER M4 ;
        RECT  129.516 20.4 129.6 20.424 ;
    END
  END gx_w[60]
  PIN gx_w[61]
    DIRECTION OUTPUT ;
    USE SIGNAL ;
    PORT
      LAYER M4 ;
        RECT  129.516 20.736 129.6 20.76 ;
    END
  END gx_w[61]
  PIN gx_w[62]
    DIRECTION OUTPUT ;
    USE SIGNAL ;
    PORT
      LAYER M4 ;
        RECT  129.516 21.072 129.6 21.096 ;
    END
  END gx_w[62]
  PIN gx_w[63]
    DIRECTION OUTPUT ;
    USE SIGNAL ;
    PORT
      LAYER M4 ;
        RECT  129.516 21.408 129.6 21.432 ;
    END
  END gx_w[63]
  PIN gx_w[64]
    DIRECTION OUTPUT ;
    USE SIGNAL ;
    PORT
      LAYER M4 ;
        RECT  129.516 21.744 129.6 21.768 ;
    END
  END gx_w[64]
  PIN gx_w[65]
    DIRECTION OUTPUT ;
    USE SIGNAL ;
    PORT
      LAYER M4 ;
        RECT  129.516 22.08 129.6 22.104 ;
    END
  END gx_w[65]
  PIN gx_w[66]
    DIRECTION OUTPUT ;
    USE SIGNAL ;
    PORT
      LAYER M4 ;
        RECT  129.516 22.416 129.6 22.44 ;
    END
  END gx_w[66]
  PIN gx_w[67]
    DIRECTION OUTPUT ;
    USE SIGNAL ;
    PORT
      LAYER M4 ;
        RECT  129.516 22.752 129.6 22.776 ;
    END
  END gx_w[67]
  PIN gx_w[68]
    DIRECTION OUTPUT ;
    USE SIGNAL ;
    PORT
      LAYER M4 ;
        RECT  129.516 23.088 129.6 23.112 ;
    END
  END gx_w[68]
  PIN gx_w[69]
    DIRECTION OUTPUT ;
    USE SIGNAL ;
    PORT
      LAYER M4 ;
        RECT  129.516 23.424 129.6 23.448 ;
    END
  END gx_w[69]
  PIN gx_w[6]
    DIRECTION OUTPUT ;
    USE SIGNAL ;
    PORT
      LAYER M4 ;
        RECT  129.516 2.16 129.6 2.184 ;
    END
  END gx_w[6]
  PIN gx_w[70]
    DIRECTION OUTPUT ;
    USE SIGNAL ;
    PORT
      LAYER M4 ;
        RECT  129.516 23.76 129.6 23.784 ;
    END
  END gx_w[70]
  PIN gx_w[71]
    DIRECTION OUTPUT ;
    USE SIGNAL ;
    PORT
      LAYER M4 ;
        RECT  129.516 24.096 129.6 24.12 ;
    END
  END gx_w[71]
  PIN gx_w[72]
    DIRECTION OUTPUT ;
    USE SIGNAL ;
    PORT
      LAYER M4 ;
        RECT  129.516 24.48 129.6 24.504 ;
    END
  END gx_w[72]
  PIN gx_w[73]
    DIRECTION OUTPUT ;
    USE SIGNAL ;
    PORT
      LAYER M4 ;
        RECT  129.516 24.816 129.6 24.84 ;
    END
  END gx_w[73]
  PIN gx_w[74]
    DIRECTION OUTPUT ;
    USE SIGNAL ;
    PORT
      LAYER M4 ;
        RECT  129.516 25.152 129.6 25.176 ;
    END
  END gx_w[74]
  PIN gx_w[75]
    DIRECTION OUTPUT ;
    USE SIGNAL ;
    PORT
      LAYER M4 ;
        RECT  129.516 25.488 129.6 25.512 ;
    END
  END gx_w[75]
  PIN gx_w[76]
    DIRECTION OUTPUT ;
    USE SIGNAL ;
    PORT
      LAYER M4 ;
        RECT  129.516 25.824 129.6 25.848 ;
    END
  END gx_w[76]
  PIN gx_w[77]
    DIRECTION OUTPUT ;
    USE SIGNAL ;
    PORT
      LAYER M4 ;
        RECT  129.516 26.16 129.6 26.184 ;
    END
  END gx_w[77]
  PIN gx_w[78]
    DIRECTION OUTPUT ;
    USE SIGNAL ;
    PORT
      LAYER M4 ;
        RECT  129.516 26.496 129.6 26.52 ;
    END
  END gx_w[78]
  PIN gx_w[79]
    DIRECTION OUTPUT ;
    USE SIGNAL ;
    PORT
      LAYER M4 ;
        RECT  129.516 26.832 129.6 26.856 ;
    END
  END gx_w[79]
  PIN gx_w[7]
    DIRECTION OUTPUT ;
    USE SIGNAL ;
    PORT
      LAYER M4 ;
        RECT  129.516 2.496 129.6 2.52 ;
    END
  END gx_w[7]
  PIN gx_w[80]
    DIRECTION OUTPUT ;
    USE SIGNAL ;
    PORT
      LAYER M4 ;
        RECT  129.516 27.168 129.6 27.192 ;
    END
  END gx_w[80]
  PIN gx_w[81]
    DIRECTION OUTPUT ;
    USE SIGNAL ;
    PORT
      LAYER M4 ;
        RECT  129.516 27.504 129.6 27.528 ;
    END
  END gx_w[81]
  PIN gx_w[82]
    DIRECTION OUTPUT ;
    USE SIGNAL ;
    PORT
      LAYER M4 ;
        RECT  129.516 27.84 129.6 27.864 ;
    END
  END gx_w[82]
  PIN gx_w[83]
    DIRECTION OUTPUT ;
    USE SIGNAL ;
    PORT
      LAYER M4 ;
        RECT  129.516 28.176 129.6 28.2 ;
    END
  END gx_w[83]
  PIN gx_w[84]
    DIRECTION OUTPUT ;
    USE SIGNAL ;
    PORT
      LAYER M4 ;
        RECT  129.516 28.512 129.6 28.536 ;
    END
  END gx_w[84]
  PIN gx_w[85]
    DIRECTION OUTPUT ;
    USE SIGNAL ;
    PORT
      LAYER M4 ;
        RECT  129.516 28.848 129.6 28.872 ;
    END
  END gx_w[85]
  PIN gx_w[86]
    DIRECTION OUTPUT ;
    USE SIGNAL ;
    PORT
      LAYER M4 ;
        RECT  129.516 29.184 129.6 29.208 ;
    END
  END gx_w[86]
  PIN gx_w[87]
    DIRECTION OUTPUT ;
    USE SIGNAL ;
    PORT
      LAYER M4 ;
        RECT  129.516 29.52 129.6 29.544 ;
    END
  END gx_w[87]
  PIN gx_w[88]
    DIRECTION OUTPUT ;
    USE SIGNAL ;
    PORT
      LAYER M4 ;
        RECT  129.516 29.856 129.6 29.88 ;
    END
  END gx_w[88]
  PIN gx_w[89]
    DIRECTION OUTPUT ;
    USE SIGNAL ;
    PORT
      LAYER M4 ;
        RECT  129.516 30.192 129.6 30.216 ;
    END
  END gx_w[89]
  PIN gx_w[8]
    DIRECTION OUTPUT ;
    USE SIGNAL ;
    PORT
      LAYER M4 ;
        RECT  129.516 2.88 129.6 2.904 ;
    END
  END gx_w[8]
  PIN gx_w[90]
    DIRECTION OUTPUT ;
    USE SIGNAL ;
    PORT
      LAYER M4 ;
        RECT  129.516 30.528 129.6 30.552 ;
    END
  END gx_w[90]
  PIN gx_w[91]
    DIRECTION OUTPUT ;
    USE SIGNAL ;
    PORT
      LAYER M4 ;
        RECT  129.516 30.864 129.6 30.888 ;
    END
  END gx_w[91]
  PIN gx_w[92]
    DIRECTION OUTPUT ;
    USE SIGNAL ;
    PORT
      LAYER M4 ;
        RECT  129.516 31.2 129.6 31.224 ;
    END
  END gx_w[92]
  PIN gx_w[93]
    DIRECTION OUTPUT ;
    USE SIGNAL ;
    PORT
      LAYER M4 ;
        RECT  129.516 31.536 129.6 31.56 ;
    END
  END gx_w[93]
  PIN gx_w[94]
    DIRECTION OUTPUT ;
    USE SIGNAL ;
    PORT
      LAYER M4 ;
        RECT  129.516 31.872 129.6 31.896 ;
    END
  END gx_w[94]
  PIN gx_w[95]
    DIRECTION OUTPUT ;
    USE SIGNAL ;
    PORT
      LAYER M4 ;
        RECT  129.516 32.208 129.6 32.232 ;
    END
  END gx_w[95]
  PIN gx_w[96]
    DIRECTION OUTPUT ;
    USE SIGNAL ;
    PORT
      LAYER M4 ;
        RECT  129.516 32.544 129.6 32.568 ;
    END
  END gx_w[96]
  PIN gx_w[97]
    DIRECTION OUTPUT ;
    USE SIGNAL ;
    PORT
      LAYER M4 ;
        RECT  129.516 32.88 129.6 32.904 ;
    END
  END gx_w[97]
  PIN gx_w[98]
    DIRECTION OUTPUT ;
    USE SIGNAL ;
    PORT
      LAYER M4 ;
        RECT  129.516 33.216 129.6 33.24 ;
    END
  END gx_w[98]
  PIN gx_w[99]
    DIRECTION OUTPUT ;
    USE SIGNAL ;
    PORT
      LAYER M4 ;
        RECT  129.516 33.552 129.6 33.576 ;
    END
  END gx_w[99]
  PIN gx_w[9]
    DIRECTION OUTPUT ;
    USE SIGNAL ;
    PORT
      LAYER M4 ;
        RECT  129.516 3.216 129.6 3.24 ;
    END
  END gx_w[9]
  PIN rr_w[0]
    DIRECTION INPUT ;
    USE SIGNAL ;
    PORT
      LAYER M5 ;
        RECT  0.096 86.316 0.12 86.4 ;
    END
  END rr_w[0]
  PIN rr_w[100]
    DIRECTION INPUT ;
    USE SIGNAL ;
    PORT
      LAYER M5 ;
        RECT  25.44 86.316 25.464 86.4 ;
    END
  END rr_w[100]
  PIN rr_w[101]
    DIRECTION INPUT ;
    USE SIGNAL ;
    PORT
      LAYER M5 ;
        RECT  25.68 86.316 25.704 86.4 ;
    END
  END rr_w[101]
  PIN rr_w[102]
    DIRECTION INPUT ;
    USE SIGNAL ;
    PORT
      LAYER M5 ;
        RECT  25.92 86.316 25.944 86.4 ;
    END
  END rr_w[102]
  PIN rr_w[103]
    DIRECTION INPUT ;
    USE SIGNAL ;
    PORT
      LAYER M5 ;
        RECT  26.208 86.316 26.232 86.4 ;
    END
  END rr_w[103]
  PIN rr_w[104]
    DIRECTION INPUT ;
    USE SIGNAL ;
    PORT
      LAYER M5 ;
        RECT  26.448 86.316 26.472 86.4 ;
    END
  END rr_w[104]
  PIN rr_w[105]
    DIRECTION INPUT ;
    USE SIGNAL ;
    PORT
      LAYER M5 ;
        RECT  26.688 86.316 26.712 86.4 ;
    END
  END rr_w[105]
  PIN rr_w[106]
    DIRECTION INPUT ;
    USE SIGNAL ;
    PORT
      LAYER M5 ;
        RECT  26.928 86.316 26.952 86.4 ;
    END
  END rr_w[106]
  PIN rr_w[107]
    DIRECTION INPUT ;
    USE SIGNAL ;
    PORT
      LAYER M5 ;
        RECT  27.216 86.316 27.24 86.4 ;
    END
  END rr_w[107]
  PIN rr_w[108]
    DIRECTION INPUT ;
    USE SIGNAL ;
    PORT
      LAYER M5 ;
        RECT  27.456 86.316 27.48 86.4 ;
    END
  END rr_w[108]
  PIN rr_w[109]
    DIRECTION INPUT ;
    USE SIGNAL ;
    PORT
      LAYER M5 ;
        RECT  27.696 86.316 27.72 86.4 ;
    END
  END rr_w[109]
  PIN rr_w[10]
    DIRECTION INPUT ;
    USE SIGNAL ;
    PORT
      LAYER M5 ;
        RECT  2.64 86.316 2.664 86.4 ;
    END
  END rr_w[10]
  PIN rr_w[110]
    DIRECTION INPUT ;
    USE SIGNAL ;
    PORT
      LAYER M5 ;
        RECT  27.936 86.316 27.96 86.4 ;
    END
  END rr_w[110]
  PIN rr_w[111]
    DIRECTION INPUT ;
    USE SIGNAL ;
    PORT
      LAYER M5 ;
        RECT  28.224 86.316 28.248 86.4 ;
    END
  END rr_w[111]
  PIN rr_w[112]
    DIRECTION INPUT ;
    USE SIGNAL ;
    PORT
      LAYER M5 ;
        RECT  28.464 86.316 28.488 86.4 ;
    END
  END rr_w[112]
  PIN rr_w[113]
    DIRECTION INPUT ;
    USE SIGNAL ;
    PORT
      LAYER M5 ;
        RECT  28.704 86.316 28.728 86.4 ;
    END
  END rr_w[113]
  PIN rr_w[114]
    DIRECTION INPUT ;
    USE SIGNAL ;
    PORT
      LAYER M5 ;
        RECT  28.992 86.316 29.016 86.4 ;
    END
  END rr_w[114]
  PIN rr_w[115]
    DIRECTION INPUT ;
    USE SIGNAL ;
    PORT
      LAYER M5 ;
        RECT  29.232 86.316 29.256 86.4 ;
    END
  END rr_w[115]
  PIN rr_w[116]
    DIRECTION INPUT ;
    USE SIGNAL ;
    PORT
      LAYER M5 ;
        RECT  29.472 86.316 29.496 86.4 ;
    END
  END rr_w[116]
  PIN rr_w[117]
    DIRECTION INPUT ;
    USE SIGNAL ;
    PORT
      LAYER M5 ;
        RECT  29.712 86.316 29.736 86.4 ;
    END
  END rr_w[117]
  PIN rr_w[118]
    DIRECTION INPUT ;
    USE SIGNAL ;
    PORT
      LAYER M5 ;
        RECT  30 86.316 30.024 86.4 ;
    END
  END rr_w[118]
  PIN rr_w[119]
    DIRECTION INPUT ;
    USE SIGNAL ;
    PORT
      LAYER M5 ;
        RECT  30.24 86.316 30.264 86.4 ;
    END
  END rr_w[119]
  PIN rr_w[11]
    DIRECTION INPUT ;
    USE SIGNAL ;
    PORT
      LAYER M5 ;
        RECT  2.88 86.316 2.904 86.4 ;
    END
  END rr_w[11]
  PIN rr_w[120]
    DIRECTION INPUT ;
    USE SIGNAL ;
    PORT
      LAYER M5 ;
        RECT  30.48 86.316 30.504 86.4 ;
    END
  END rr_w[120]
  PIN rr_w[121]
    DIRECTION INPUT ;
    USE SIGNAL ;
    PORT
      LAYER M5 ;
        RECT  30.72 86.316 30.744 86.4 ;
    END
  END rr_w[121]
  PIN rr_w[122]
    DIRECTION INPUT ;
    USE SIGNAL ;
    PORT
      LAYER M5 ;
        RECT  31.008 86.316 31.032 86.4 ;
    END
  END rr_w[122]
  PIN rr_w[123]
    DIRECTION INPUT ;
    USE SIGNAL ;
    PORT
      LAYER M5 ;
        RECT  31.248 86.316 31.272 86.4 ;
    END
  END rr_w[123]
  PIN rr_w[124]
    DIRECTION INPUT ;
    USE SIGNAL ;
    PORT
      LAYER M5 ;
        RECT  31.488 86.316 31.512 86.4 ;
    END
  END rr_w[124]
  PIN rr_w[125]
    DIRECTION INPUT ;
    USE SIGNAL ;
    PORT
      LAYER M5 ;
        RECT  31.776 86.316 31.8 86.4 ;
    END
  END rr_w[125]
  PIN rr_w[126]
    DIRECTION INPUT ;
    USE SIGNAL ;
    PORT
      LAYER M5 ;
        RECT  32.016 86.316 32.04 86.4 ;
    END
  END rr_w[126]
  PIN rr_w[127]
    DIRECTION INPUT ;
    USE SIGNAL ;
    PORT
      LAYER M5 ;
        RECT  32.256 86.316 32.28 86.4 ;
    END
  END rr_w[127]
  PIN rr_w[128]
    DIRECTION INPUT ;
    USE SIGNAL ;
    PORT
      LAYER M5 ;
        RECT  32.496 86.316 32.52 86.4 ;
    END
  END rr_w[128]
  PIN rr_w[129]
    DIRECTION INPUT ;
    USE SIGNAL ;
    PORT
      LAYER M5 ;
        RECT  32.784 86.316 32.808 86.4 ;
    END
  END rr_w[129]
  PIN rr_w[12]
    DIRECTION INPUT ;
    USE SIGNAL ;
    PORT
      LAYER M5 ;
        RECT  3.168 86.316 3.192 86.4 ;
    END
  END rr_w[12]
  PIN rr_w[130]
    DIRECTION INPUT ;
    USE SIGNAL ;
    PORT
      LAYER M5 ;
        RECT  33.024 86.316 33.048 86.4 ;
    END
  END rr_w[130]
  PIN rr_w[131]
    DIRECTION INPUT ;
    USE SIGNAL ;
    PORT
      LAYER M5 ;
        RECT  33.264 86.316 33.288 86.4 ;
    END
  END rr_w[131]
  PIN rr_w[132]
    DIRECTION INPUT ;
    USE SIGNAL ;
    PORT
      LAYER M5 ;
        RECT  33.504 86.316 33.528 86.4 ;
    END
  END rr_w[132]
  PIN rr_w[133]
    DIRECTION INPUT ;
    USE SIGNAL ;
    PORT
      LAYER M5 ;
        RECT  33.792 86.316 33.816 86.4 ;
    END
  END rr_w[133]
  PIN rr_w[134]
    DIRECTION INPUT ;
    USE SIGNAL ;
    PORT
      LAYER M5 ;
        RECT  34.032 86.316 34.056 86.4 ;
    END
  END rr_w[134]
  PIN rr_w[135]
    DIRECTION INPUT ;
    USE SIGNAL ;
    PORT
      LAYER M5 ;
        RECT  34.272 86.316 34.296 86.4 ;
    END
  END rr_w[135]
  PIN rr_w[136]
    DIRECTION INPUT ;
    USE SIGNAL ;
    PORT
      LAYER M5 ;
        RECT  34.56 86.316 34.584 86.4 ;
    END
  END rr_w[136]
  PIN rr_w[137]
    DIRECTION INPUT ;
    USE SIGNAL ;
    PORT
      LAYER M5 ;
        RECT  34.8 86.316 34.824 86.4 ;
    END
  END rr_w[137]
  PIN rr_w[138]
    DIRECTION INPUT ;
    USE SIGNAL ;
    PORT
      LAYER M5 ;
        RECT  35.04 86.316 35.064 86.4 ;
    END
  END rr_w[138]
  PIN rr_w[139]
    DIRECTION INPUT ;
    USE SIGNAL ;
    PORT
      LAYER M5 ;
        RECT  35.28 86.316 35.304 86.4 ;
    END
  END rr_w[139]
  PIN rr_w[13]
    DIRECTION INPUT ;
    USE SIGNAL ;
    PORT
      LAYER M5 ;
        RECT  3.408 86.316 3.432 86.4 ;
    END
  END rr_w[13]
  PIN rr_w[140]
    DIRECTION INPUT ;
    USE SIGNAL ;
    PORT
      LAYER M5 ;
        RECT  35.568 86.316 35.592 86.4 ;
    END
  END rr_w[140]
  PIN rr_w[141]
    DIRECTION INPUT ;
    USE SIGNAL ;
    PORT
      LAYER M5 ;
        RECT  35.808 86.316 35.832 86.4 ;
    END
  END rr_w[141]
  PIN rr_w[142]
    DIRECTION INPUT ;
    USE SIGNAL ;
    PORT
      LAYER M5 ;
        RECT  36.048 86.316 36.072 86.4 ;
    END
  END rr_w[142]
  PIN rr_w[143]
    DIRECTION INPUT ;
    USE SIGNAL ;
    PORT
      LAYER M5 ;
        RECT  36.288 86.316 36.312 86.4 ;
    END
  END rr_w[143]
  PIN rr_w[144]
    DIRECTION INPUT ;
    USE SIGNAL ;
    PORT
      LAYER M5 ;
        RECT  36.576 86.316 36.6 86.4 ;
    END
  END rr_w[144]
  PIN rr_w[145]
    DIRECTION INPUT ;
    USE SIGNAL ;
    PORT
      LAYER M5 ;
        RECT  36.816 86.316 36.84 86.4 ;
    END
  END rr_w[145]
  PIN rr_w[146]
    DIRECTION INPUT ;
    USE SIGNAL ;
    PORT
      LAYER M5 ;
        RECT  37.056 86.316 37.08 86.4 ;
    END
  END rr_w[146]
  PIN rr_w[147]
    DIRECTION INPUT ;
    USE SIGNAL ;
    PORT
      LAYER M5 ;
        RECT  37.344 86.316 37.368 86.4 ;
    END
  END rr_w[147]
  PIN rr_w[148]
    DIRECTION INPUT ;
    USE SIGNAL ;
    PORT
      LAYER M5 ;
        RECT  37.584 86.316 37.608 86.4 ;
    END
  END rr_w[148]
  PIN rr_w[149]
    DIRECTION INPUT ;
    USE SIGNAL ;
    PORT
      LAYER M5 ;
        RECT  37.824 86.316 37.848 86.4 ;
    END
  END rr_w[149]
  PIN rr_w[14]
    DIRECTION INPUT ;
    USE SIGNAL ;
    PORT
      LAYER M5 ;
        RECT  3.648 86.316 3.672 86.4 ;
    END
  END rr_w[14]
  PIN rr_w[150]
    DIRECTION INPUT ;
    USE SIGNAL ;
    PORT
      LAYER M5 ;
        RECT  38.064 86.316 38.088 86.4 ;
    END
  END rr_w[150]
  PIN rr_w[151]
    DIRECTION INPUT ;
    USE SIGNAL ;
    PORT
      LAYER M5 ;
        RECT  38.352 86.316 38.376 86.4 ;
    END
  END rr_w[151]
  PIN rr_w[152]
    DIRECTION INPUT ;
    USE SIGNAL ;
    PORT
      LAYER M5 ;
        RECT  38.592 86.316 38.616 86.4 ;
    END
  END rr_w[152]
  PIN rr_w[153]
    DIRECTION INPUT ;
    USE SIGNAL ;
    PORT
      LAYER M5 ;
        RECT  38.832 86.316 38.856 86.4 ;
    END
  END rr_w[153]
  PIN rr_w[154]
    DIRECTION INPUT ;
    USE SIGNAL ;
    PORT
      LAYER M5 ;
        RECT  39.12 86.316 39.144 86.4 ;
    END
  END rr_w[154]
  PIN rr_w[155]
    DIRECTION INPUT ;
    USE SIGNAL ;
    PORT
      LAYER M5 ;
        RECT  39.36 86.316 39.384 86.4 ;
    END
  END rr_w[155]
  PIN rr_w[156]
    DIRECTION INPUT ;
    USE SIGNAL ;
    PORT
      LAYER M5 ;
        RECT  39.6 86.316 39.624 86.4 ;
    END
  END rr_w[156]
  PIN rr_w[157]
    DIRECTION INPUT ;
    USE SIGNAL ;
    PORT
      LAYER M5 ;
        RECT  39.84 86.316 39.864 86.4 ;
    END
  END rr_w[157]
  PIN rr_w[158]
    DIRECTION INPUT ;
    USE SIGNAL ;
    PORT
      LAYER M5 ;
        RECT  40.128 86.316 40.152 86.4 ;
    END
  END rr_w[158]
  PIN rr_w[159]
    DIRECTION INPUT ;
    USE SIGNAL ;
    PORT
      LAYER M5 ;
        RECT  40.368 86.316 40.392 86.4 ;
    END
  END rr_w[159]
  PIN rr_w[15]
    DIRECTION INPUT ;
    USE SIGNAL ;
    PORT
      LAYER M5 ;
        RECT  3.888 86.316 3.912 86.4 ;
    END
  END rr_w[15]
  PIN rr_w[160]
    DIRECTION INPUT ;
    USE SIGNAL ;
    PORT
      LAYER M5 ;
        RECT  40.608 86.316 40.632 86.4 ;
    END
  END rr_w[160]
  PIN rr_w[161]
    DIRECTION INPUT ;
    USE SIGNAL ;
    PORT
      LAYER M5 ;
        RECT  40.848 86.316 40.872 86.4 ;
    END
  END rr_w[161]
  PIN rr_w[162]
    DIRECTION INPUT ;
    USE SIGNAL ;
    PORT
      LAYER M5 ;
        RECT  41.136 86.316 41.16 86.4 ;
    END
  END rr_w[162]
  PIN rr_w[163]
    DIRECTION INPUT ;
    USE SIGNAL ;
    PORT
      LAYER M5 ;
        RECT  41.376 86.316 41.4 86.4 ;
    END
  END rr_w[163]
  PIN rr_w[164]
    DIRECTION INPUT ;
    USE SIGNAL ;
    PORT
      LAYER M5 ;
        RECT  41.616 86.316 41.64 86.4 ;
    END
  END rr_w[164]
  PIN rr_w[165]
    DIRECTION INPUT ;
    USE SIGNAL ;
    PORT
      LAYER M5 ;
        RECT  41.904 86.316 41.928 86.4 ;
    END
  END rr_w[165]
  PIN rr_w[166]
    DIRECTION INPUT ;
    USE SIGNAL ;
    PORT
      LAYER M5 ;
        RECT  42.144 86.316 42.168 86.4 ;
    END
  END rr_w[166]
  PIN rr_w[167]
    DIRECTION INPUT ;
    USE SIGNAL ;
    PORT
      LAYER M5 ;
        RECT  42.384 86.316 42.408 86.4 ;
    END
  END rr_w[167]
  PIN rr_w[168]
    DIRECTION INPUT ;
    USE SIGNAL ;
    PORT
      LAYER M5 ;
        RECT  42.624 86.316 42.648 86.4 ;
    END
  END rr_w[168]
  PIN rr_w[169]
    DIRECTION INPUT ;
    USE SIGNAL ;
    PORT
      LAYER M5 ;
        RECT  42.912 86.316 42.936 86.4 ;
    END
  END rr_w[169]
  PIN rr_w[16]
    DIRECTION INPUT ;
    USE SIGNAL ;
    PORT
      LAYER M5 ;
        RECT  4.176 86.316 4.2 86.4 ;
    END
  END rr_w[16]
  PIN rr_w[170]
    DIRECTION INPUT ;
    USE SIGNAL ;
    PORT
      LAYER M5 ;
        RECT  43.152 86.316 43.176 86.4 ;
    END
  END rr_w[170]
  PIN rr_w[171]
    DIRECTION INPUT ;
    USE SIGNAL ;
    PORT
      LAYER M5 ;
        RECT  43.392 86.316 43.416 86.4 ;
    END
  END rr_w[171]
  PIN rr_w[172]
    DIRECTION INPUT ;
    USE SIGNAL ;
    PORT
      LAYER M5 ;
        RECT  43.632 86.316 43.656 86.4 ;
    END
  END rr_w[172]
  PIN rr_w[173]
    DIRECTION INPUT ;
    USE SIGNAL ;
    PORT
      LAYER M5 ;
        RECT  43.92 86.316 43.944 86.4 ;
    END
  END rr_w[173]
  PIN rr_w[174]
    DIRECTION INPUT ;
    USE SIGNAL ;
    PORT
      LAYER M5 ;
        RECT  44.16 86.316 44.184 86.4 ;
    END
  END rr_w[174]
  PIN rr_w[175]
    DIRECTION INPUT ;
    USE SIGNAL ;
    PORT
      LAYER M5 ;
        RECT  44.4 86.316 44.424 86.4 ;
    END
  END rr_w[175]
  PIN rr_w[176]
    DIRECTION INPUT ;
    USE SIGNAL ;
    PORT
      LAYER M5 ;
        RECT  44.688 86.316 44.712 86.4 ;
    END
  END rr_w[176]
  PIN rr_w[177]
    DIRECTION INPUT ;
    USE SIGNAL ;
    PORT
      LAYER M5 ;
        RECT  44.928 86.316 44.952 86.4 ;
    END
  END rr_w[177]
  PIN rr_w[178]
    DIRECTION INPUT ;
    USE SIGNAL ;
    PORT
      LAYER M5 ;
        RECT  45.168 86.316 45.192 86.4 ;
    END
  END rr_w[178]
  PIN rr_w[179]
    DIRECTION INPUT ;
    USE SIGNAL ;
    PORT
      LAYER M5 ;
        RECT  45.408 86.316 45.432 86.4 ;
    END
  END rr_w[179]
  PIN rr_w[17]
    DIRECTION INPUT ;
    USE SIGNAL ;
    PORT
      LAYER M5 ;
        RECT  4.416 86.316 4.44 86.4 ;
    END
  END rr_w[17]
  PIN rr_w[180]
    DIRECTION INPUT ;
    USE SIGNAL ;
    PORT
      LAYER M5 ;
        RECT  45.696 86.316 45.72 86.4 ;
    END
  END rr_w[180]
  PIN rr_w[181]
    DIRECTION INPUT ;
    USE SIGNAL ;
    PORT
      LAYER M5 ;
        RECT  45.936 86.316 45.96 86.4 ;
    END
  END rr_w[181]
  PIN rr_w[182]
    DIRECTION INPUT ;
    USE SIGNAL ;
    PORT
      LAYER M5 ;
        RECT  46.176 86.316 46.2 86.4 ;
    END
  END rr_w[182]
  PIN rr_w[183]
    DIRECTION INPUT ;
    USE SIGNAL ;
    PORT
      LAYER M5 ;
        RECT  46.416 86.316 46.44 86.4 ;
    END
  END rr_w[183]
  PIN rr_w[184]
    DIRECTION INPUT ;
    USE SIGNAL ;
    PORT
      LAYER M5 ;
        RECT  46.704 86.316 46.728 86.4 ;
    END
  END rr_w[184]
  PIN rr_w[185]
    DIRECTION INPUT ;
    USE SIGNAL ;
    PORT
      LAYER M5 ;
        RECT  46.944 86.316 46.968 86.4 ;
    END
  END rr_w[185]
  PIN rr_w[186]
    DIRECTION INPUT ;
    USE SIGNAL ;
    PORT
      LAYER M5 ;
        RECT  47.184 86.316 47.208 86.4 ;
    END
  END rr_w[186]
  PIN rr_w[187]
    DIRECTION INPUT ;
    USE SIGNAL ;
    PORT
      LAYER M5 ;
        RECT  47.472 86.316 47.496 86.4 ;
    END
  END rr_w[187]
  PIN rr_w[188]
    DIRECTION INPUT ;
    USE SIGNAL ;
    PORT
      LAYER M5 ;
        RECT  47.712 86.316 47.736 86.4 ;
    END
  END rr_w[188]
  PIN rr_w[189]
    DIRECTION INPUT ;
    USE SIGNAL ;
    PORT
      LAYER M5 ;
        RECT  47.952 86.316 47.976 86.4 ;
    END
  END rr_w[189]
  PIN rr_w[18]
    DIRECTION INPUT ;
    USE SIGNAL ;
    PORT
      LAYER M5 ;
        RECT  4.656 86.316 4.68 86.4 ;
    END
  END rr_w[18]
  PIN rr_w[190]
    DIRECTION INPUT ;
    USE SIGNAL ;
    PORT
      LAYER M5 ;
        RECT  48.192 86.316 48.216 86.4 ;
    END
  END rr_w[190]
  PIN rr_w[191]
    DIRECTION INPUT ;
    USE SIGNAL ;
    PORT
      LAYER M5 ;
        RECT  48.48 86.316 48.504 86.4 ;
    END
  END rr_w[191]
  PIN rr_w[192]
    DIRECTION INPUT ;
    USE SIGNAL ;
    PORT
      LAYER M5 ;
        RECT  48.72 86.316 48.744 86.4 ;
    END
  END rr_w[192]
  PIN rr_w[193]
    DIRECTION INPUT ;
    USE SIGNAL ;
    PORT
      LAYER M5 ;
        RECT  48.96 86.316 48.984 86.4 ;
    END
  END rr_w[193]
  PIN rr_w[194]
    DIRECTION INPUT ;
    USE SIGNAL ;
    PORT
      LAYER M5 ;
        RECT  49.2 86.316 49.224 86.4 ;
    END
  END rr_w[194]
  PIN rr_w[195]
    DIRECTION INPUT ;
    USE SIGNAL ;
    PORT
      LAYER M5 ;
        RECT  49.488 86.316 49.512 86.4 ;
    END
  END rr_w[195]
  PIN rr_w[196]
    DIRECTION INPUT ;
    USE SIGNAL ;
    PORT
      LAYER M5 ;
        RECT  49.728 86.316 49.752 86.4 ;
    END
  END rr_w[196]
  PIN rr_w[197]
    DIRECTION INPUT ;
    USE SIGNAL ;
    PORT
      LAYER M5 ;
        RECT  49.968 86.316 49.992 86.4 ;
    END
  END rr_w[197]
  PIN rr_w[198]
    DIRECTION INPUT ;
    USE SIGNAL ;
    PORT
      LAYER M5 ;
        RECT  50.256 86.316 50.28 86.4 ;
    END
  END rr_w[198]
  PIN rr_w[199]
    DIRECTION INPUT ;
    USE SIGNAL ;
    PORT
      LAYER M5 ;
        RECT  50.496 86.316 50.52 86.4 ;
    END
  END rr_w[199]
  PIN rr_w[19]
    DIRECTION INPUT ;
    USE SIGNAL ;
    PORT
      LAYER M5 ;
        RECT  4.944 86.316 4.968 86.4 ;
    END
  END rr_w[19]
  PIN rr_w[1]
    DIRECTION INPUT ;
    USE SIGNAL ;
    PORT
      LAYER M5 ;
        RECT  0.384 86.316 0.408 86.4 ;
    END
  END rr_w[1]
  PIN rr_w[200]
    DIRECTION INPUT ;
    USE SIGNAL ;
    PORT
      LAYER M5 ;
        RECT  50.736 86.316 50.76 86.4 ;
    END
  END rr_w[200]
  PIN rr_w[201]
    DIRECTION INPUT ;
    USE SIGNAL ;
    PORT
      LAYER M5 ;
        RECT  50.976 86.316 51 86.4 ;
    END
  END rr_w[201]
  PIN rr_w[202]
    DIRECTION INPUT ;
    USE SIGNAL ;
    PORT
      LAYER M5 ;
        RECT  51.264 86.316 51.288 86.4 ;
    END
  END rr_w[202]
  PIN rr_w[203]
    DIRECTION INPUT ;
    USE SIGNAL ;
    PORT
      LAYER M5 ;
        RECT  51.504 86.316 51.528 86.4 ;
    END
  END rr_w[203]
  PIN rr_w[204]
    DIRECTION INPUT ;
    USE SIGNAL ;
    PORT
      LAYER M5 ;
        RECT  51.744 86.316 51.768 86.4 ;
    END
  END rr_w[204]
  PIN rr_w[205]
    DIRECTION INPUT ;
    USE SIGNAL ;
    PORT
      LAYER M5 ;
        RECT  51.984 86.316 52.008 86.4 ;
    END
  END rr_w[205]
  PIN rr_w[206]
    DIRECTION INPUT ;
    USE SIGNAL ;
    PORT
      LAYER M5 ;
        RECT  52.272 86.316 52.296 86.4 ;
    END
  END rr_w[206]
  PIN rr_w[207]
    DIRECTION INPUT ;
    USE SIGNAL ;
    PORT
      LAYER M5 ;
        RECT  52.512 86.316 52.536 86.4 ;
    END
  END rr_w[207]
  PIN rr_w[208]
    DIRECTION INPUT ;
    USE SIGNAL ;
    PORT
      LAYER M5 ;
        RECT  52.752 86.316 52.776 86.4 ;
    END
  END rr_w[208]
  PIN rr_w[209]
    DIRECTION INPUT ;
    USE SIGNAL ;
    PORT
      LAYER M5 ;
        RECT  53.04 86.316 53.064 86.4 ;
    END
  END rr_w[209]
  PIN rr_w[20]
    DIRECTION INPUT ;
    USE SIGNAL ;
    PORT
      LAYER M5 ;
        RECT  5.184 86.316 5.208 86.4 ;
    END
  END rr_w[20]
  PIN rr_w[210]
    DIRECTION INPUT ;
    USE SIGNAL ;
    PORT
      LAYER M5 ;
        RECT  53.28 86.316 53.304 86.4 ;
    END
  END rr_w[210]
  PIN rr_w[211]
    DIRECTION INPUT ;
    USE SIGNAL ;
    PORT
      LAYER M5 ;
        RECT  53.52 86.316 53.544 86.4 ;
    END
  END rr_w[211]
  PIN rr_w[212]
    DIRECTION INPUT ;
    USE SIGNAL ;
    PORT
      LAYER M5 ;
        RECT  53.76 86.316 53.784 86.4 ;
    END
  END rr_w[212]
  PIN rr_w[213]
    DIRECTION INPUT ;
    USE SIGNAL ;
    PORT
      LAYER M5 ;
        RECT  54.048 86.316 54.072 86.4 ;
    END
  END rr_w[213]
  PIN rr_w[214]
    DIRECTION INPUT ;
    USE SIGNAL ;
    PORT
      LAYER M5 ;
        RECT  54.288 86.316 54.312 86.4 ;
    END
  END rr_w[214]
  PIN rr_w[215]
    DIRECTION INPUT ;
    USE SIGNAL ;
    PORT
      LAYER M5 ;
        RECT  54.528 86.316 54.552 86.4 ;
    END
  END rr_w[215]
  PIN rr_w[216]
    DIRECTION INPUT ;
    USE SIGNAL ;
    PORT
      LAYER M5 ;
        RECT  54.768 86.316 54.792 86.4 ;
    END
  END rr_w[216]
  PIN rr_w[217]
    DIRECTION INPUT ;
    USE SIGNAL ;
    PORT
      LAYER M5 ;
        RECT  55.056 86.316 55.08 86.4 ;
    END
  END rr_w[217]
  PIN rr_w[218]
    DIRECTION INPUT ;
    USE SIGNAL ;
    PORT
      LAYER M5 ;
        RECT  55.296 86.316 55.32 86.4 ;
    END
  END rr_w[218]
  PIN rr_w[219]
    DIRECTION INPUT ;
    USE SIGNAL ;
    PORT
      LAYER M5 ;
        RECT  55.536 86.316 55.56 86.4 ;
    END
  END rr_w[219]
  PIN rr_w[21]
    DIRECTION INPUT ;
    USE SIGNAL ;
    PORT
      LAYER M5 ;
        RECT  5.424 86.316 5.448 86.4 ;
    END
  END rr_w[21]
  PIN rr_w[220]
    DIRECTION INPUT ;
    USE SIGNAL ;
    PORT
      LAYER M5 ;
        RECT  55.824 86.316 55.848 86.4 ;
    END
  END rr_w[220]
  PIN rr_w[221]
    DIRECTION INPUT ;
    USE SIGNAL ;
    PORT
      LAYER M5 ;
        RECT  56.064 86.316 56.088 86.4 ;
    END
  END rr_w[221]
  PIN rr_w[222]
    DIRECTION INPUT ;
    USE SIGNAL ;
    PORT
      LAYER M5 ;
        RECT  56.304 86.316 56.328 86.4 ;
    END
  END rr_w[222]
  PIN rr_w[223]
    DIRECTION INPUT ;
    USE SIGNAL ;
    PORT
      LAYER M5 ;
        RECT  56.544 86.316 56.568 86.4 ;
    END
  END rr_w[223]
  PIN rr_w[224]
    DIRECTION INPUT ;
    USE SIGNAL ;
    PORT
      LAYER M5 ;
        RECT  56.832 86.316 56.856 86.4 ;
    END
  END rr_w[224]
  PIN rr_w[225]
    DIRECTION INPUT ;
    USE SIGNAL ;
    PORT
      LAYER M5 ;
        RECT  57.072 86.316 57.096 86.4 ;
    END
  END rr_w[225]
  PIN rr_w[226]
    DIRECTION INPUT ;
    USE SIGNAL ;
    PORT
      LAYER M5 ;
        RECT  57.312 86.316 57.336 86.4 ;
    END
  END rr_w[226]
  PIN rr_w[227]
    DIRECTION INPUT ;
    USE SIGNAL ;
    PORT
      LAYER M5 ;
        RECT  57.552 86.316 57.576 86.4 ;
    END
  END rr_w[227]
  PIN rr_w[228]
    DIRECTION INPUT ;
    USE SIGNAL ;
    PORT
      LAYER M5 ;
        RECT  57.84 86.316 57.864 86.4 ;
    END
  END rr_w[228]
  PIN rr_w[229]
    DIRECTION INPUT ;
    USE SIGNAL ;
    PORT
      LAYER M5 ;
        RECT  58.08 86.316 58.104 86.4 ;
    END
  END rr_w[229]
  PIN rr_w[22]
    DIRECTION INPUT ;
    USE SIGNAL ;
    PORT
      LAYER M5 ;
        RECT  5.664 86.316 5.688 86.4 ;
    END
  END rr_w[22]
  PIN rr_w[230]
    DIRECTION INPUT ;
    USE SIGNAL ;
    PORT
      LAYER M5 ;
        RECT  58.32 86.316 58.344 86.4 ;
    END
  END rr_w[230]
  PIN rr_w[231]
    DIRECTION INPUT ;
    USE SIGNAL ;
    PORT
      LAYER M5 ;
        RECT  58.608 86.316 58.632 86.4 ;
    END
  END rr_w[231]
  PIN rr_w[232]
    DIRECTION INPUT ;
    USE SIGNAL ;
    PORT
      LAYER M5 ;
        RECT  58.848 86.316 58.872 86.4 ;
    END
  END rr_w[232]
  PIN rr_w[233]
    DIRECTION INPUT ;
    USE SIGNAL ;
    PORT
      LAYER M5 ;
        RECT  59.088 86.316 59.112 86.4 ;
    END
  END rr_w[233]
  PIN rr_w[234]
    DIRECTION INPUT ;
    USE SIGNAL ;
    PORT
      LAYER M5 ;
        RECT  59.328 86.316 59.352 86.4 ;
    END
  END rr_w[234]
  PIN rr_w[235]
    DIRECTION INPUT ;
    USE SIGNAL ;
    PORT
      LAYER M5 ;
        RECT  59.616 86.316 59.64 86.4 ;
    END
  END rr_w[235]
  PIN rr_w[236]
    DIRECTION INPUT ;
    USE SIGNAL ;
    PORT
      LAYER M5 ;
        RECT  59.856 86.316 59.88 86.4 ;
    END
  END rr_w[236]
  PIN rr_w[237]
    DIRECTION INPUT ;
    USE SIGNAL ;
    PORT
      LAYER M5 ;
        RECT  60.096 86.316 60.12 86.4 ;
    END
  END rr_w[237]
  PIN rr_w[238]
    DIRECTION INPUT ;
    USE SIGNAL ;
    PORT
      LAYER M5 ;
        RECT  60.336 86.316 60.36 86.4 ;
    END
  END rr_w[238]
  PIN rr_w[239]
    DIRECTION INPUT ;
    USE SIGNAL ;
    PORT
      LAYER M5 ;
        RECT  60.624 86.316 60.648 86.4 ;
    END
  END rr_w[239]
  PIN rr_w[23]
    DIRECTION INPUT ;
    USE SIGNAL ;
    PORT
      LAYER M5 ;
        RECT  5.952 86.316 5.976 86.4 ;
    END
  END rr_w[23]
  PIN rr_w[240]
    DIRECTION INPUT ;
    USE SIGNAL ;
    PORT
      LAYER M5 ;
        RECT  60.864 86.316 60.888 86.4 ;
    END
  END rr_w[240]
  PIN rr_w[241]
    DIRECTION INPUT ;
    USE SIGNAL ;
    PORT
      LAYER M5 ;
        RECT  61.104 86.316 61.128 86.4 ;
    END
  END rr_w[241]
  PIN rr_w[242]
    DIRECTION INPUT ;
    USE SIGNAL ;
    PORT
      LAYER M5 ;
        RECT  61.392 86.316 61.416 86.4 ;
    END
  END rr_w[242]
  PIN rr_w[243]
    DIRECTION INPUT ;
    USE SIGNAL ;
    PORT
      LAYER M5 ;
        RECT  61.632 86.316 61.656 86.4 ;
    END
  END rr_w[243]
  PIN rr_w[244]
    DIRECTION INPUT ;
    USE SIGNAL ;
    PORT
      LAYER M5 ;
        RECT  61.872 86.316 61.896 86.4 ;
    END
  END rr_w[244]
  PIN rr_w[245]
    DIRECTION INPUT ;
    USE SIGNAL ;
    PORT
      LAYER M5 ;
        RECT  62.112 86.316 62.136 86.4 ;
    END
  END rr_w[245]
  PIN rr_w[246]
    DIRECTION INPUT ;
    USE SIGNAL ;
    PORT
      LAYER M5 ;
        RECT  62.4 86.316 62.424 86.4 ;
    END
  END rr_w[246]
  PIN rr_w[247]
    DIRECTION INPUT ;
    USE SIGNAL ;
    PORT
      LAYER M5 ;
        RECT  62.64 86.316 62.664 86.4 ;
    END
  END rr_w[247]
  PIN rr_w[248]
    DIRECTION INPUT ;
    USE SIGNAL ;
    PORT
      LAYER M5 ;
        RECT  62.88 86.316 62.904 86.4 ;
    END
  END rr_w[248]
  PIN rr_w[249]
    DIRECTION INPUT ;
    USE SIGNAL ;
    PORT
      LAYER M5 ;
        RECT  63.12 86.316 63.144 86.4 ;
    END
  END rr_w[249]
  PIN rr_w[24]
    DIRECTION INPUT ;
    USE SIGNAL ;
    PORT
      LAYER M5 ;
        RECT  6.192 86.316 6.216 86.4 ;
    END
  END rr_w[24]
  PIN rr_w[250]
    DIRECTION INPUT ;
    USE SIGNAL ;
    PORT
      LAYER M5 ;
        RECT  63.408 86.316 63.432 86.4 ;
    END
  END rr_w[250]
  PIN rr_w[251]
    DIRECTION INPUT ;
    USE SIGNAL ;
    PORT
      LAYER M5 ;
        RECT  63.648 86.316 63.672 86.4 ;
    END
  END rr_w[251]
  PIN rr_w[252]
    DIRECTION INPUT ;
    USE SIGNAL ;
    PORT
      LAYER M5 ;
        RECT  63.888 86.316 63.912 86.4 ;
    END
  END rr_w[252]
  PIN rr_w[253]
    DIRECTION INPUT ;
    USE SIGNAL ;
    PORT
      LAYER M5 ;
        RECT  64.176 86.316 64.2 86.4 ;
    END
  END rr_w[253]
  PIN rr_w[254]
    DIRECTION INPUT ;
    USE SIGNAL ;
    PORT
      LAYER M5 ;
        RECT  64.416 86.316 64.44 86.4 ;
    END
  END rr_w[254]
  PIN rr_w[255]
    DIRECTION INPUT ;
    USE SIGNAL ;
    PORT
      LAYER M5 ;
        RECT  64.656 86.316 64.68 86.4 ;
    END
  END rr_w[255]
  PIN rr_w[256]
    DIRECTION INPUT ;
    USE SIGNAL ;
    PORT
      LAYER M5 ;
        RECT  64.896 86.316 64.92 86.4 ;
    END
  END rr_w[256]
  PIN rr_w[257]
    DIRECTION INPUT ;
    USE SIGNAL ;
    PORT
      LAYER M5 ;
        RECT  65.184 86.316 65.208 86.4 ;
    END
  END rr_w[257]
  PIN rr_w[258]
    DIRECTION INPUT ;
    USE SIGNAL ;
    PORT
      LAYER M5 ;
        RECT  65.424 86.316 65.448 86.4 ;
    END
  END rr_w[258]
  PIN rr_w[259]
    DIRECTION INPUT ;
    USE SIGNAL ;
    PORT
      LAYER M5 ;
        RECT  65.664 86.316 65.688 86.4 ;
    END
  END rr_w[259]
  PIN rr_w[25]
    DIRECTION INPUT ;
    USE SIGNAL ;
    PORT
      LAYER M5 ;
        RECT  6.432 86.316 6.456 86.4 ;
    END
  END rr_w[25]
  PIN rr_w[260]
    DIRECTION INPUT ;
    USE SIGNAL ;
    PORT
      LAYER M5 ;
        RECT  65.904 86.316 65.928 86.4 ;
    END
  END rr_w[260]
  PIN rr_w[261]
    DIRECTION INPUT ;
    USE SIGNAL ;
    PORT
      LAYER M5 ;
        RECT  66.192 86.316 66.216 86.4 ;
    END
  END rr_w[261]
  PIN rr_w[262]
    DIRECTION INPUT ;
    USE SIGNAL ;
    PORT
      LAYER M5 ;
        RECT  66.432 86.316 66.456 86.4 ;
    END
  END rr_w[262]
  PIN rr_w[263]
    DIRECTION INPUT ;
    USE SIGNAL ;
    PORT
      LAYER M5 ;
        RECT  66.672 86.316 66.696 86.4 ;
    END
  END rr_w[263]
  PIN rr_w[264]
    DIRECTION INPUT ;
    USE SIGNAL ;
    PORT
      LAYER M5 ;
        RECT  66.96 86.316 66.984 86.4 ;
    END
  END rr_w[264]
  PIN rr_w[265]
    DIRECTION INPUT ;
    USE SIGNAL ;
    PORT
      LAYER M5 ;
        RECT  67.2 86.316 67.224 86.4 ;
    END
  END rr_w[265]
  PIN rr_w[266]
    DIRECTION INPUT ;
    USE SIGNAL ;
    PORT
      LAYER M5 ;
        RECT  67.44 86.316 67.464 86.4 ;
    END
  END rr_w[266]
  PIN rr_w[267]
    DIRECTION INPUT ;
    USE SIGNAL ;
    PORT
      LAYER M5 ;
        RECT  67.68 86.316 67.704 86.4 ;
    END
  END rr_w[267]
  PIN rr_w[268]
    DIRECTION INPUT ;
    USE SIGNAL ;
    PORT
      LAYER M5 ;
        RECT  67.968 86.316 67.992 86.4 ;
    END
  END rr_w[268]
  PIN rr_w[269]
    DIRECTION INPUT ;
    USE SIGNAL ;
    PORT
      LAYER M5 ;
        RECT  68.208 86.316 68.232 86.4 ;
    END
  END rr_w[269]
  PIN rr_w[26]
    DIRECTION INPUT ;
    USE SIGNAL ;
    PORT
      LAYER M5 ;
        RECT  6.72 86.316 6.744 86.4 ;
    END
  END rr_w[26]
  PIN rr_w[270]
    DIRECTION INPUT ;
    USE SIGNAL ;
    PORT
      LAYER M5 ;
        RECT  68.448 86.316 68.472 86.4 ;
    END
  END rr_w[270]
  PIN rr_w[271]
    DIRECTION INPUT ;
    USE SIGNAL ;
    PORT
      LAYER M5 ;
        RECT  68.688 86.316 68.712 86.4 ;
    END
  END rr_w[271]
  PIN rr_w[272]
    DIRECTION INPUT ;
    USE SIGNAL ;
    PORT
      LAYER M5 ;
        RECT  68.976 86.316 69 86.4 ;
    END
  END rr_w[272]
  PIN rr_w[273]
    DIRECTION INPUT ;
    USE SIGNAL ;
    PORT
      LAYER M5 ;
        RECT  69.216 86.316 69.24 86.4 ;
    END
  END rr_w[273]
  PIN rr_w[274]
    DIRECTION INPUT ;
    USE SIGNAL ;
    PORT
      LAYER M5 ;
        RECT  69.456 86.316 69.48 86.4 ;
    END
  END rr_w[274]
  PIN rr_w[275]
    DIRECTION INPUT ;
    USE SIGNAL ;
    PORT
      LAYER M5 ;
        RECT  69.744 86.316 69.768 86.4 ;
    END
  END rr_w[275]
  PIN rr_w[276]
    DIRECTION INPUT ;
    USE SIGNAL ;
    PORT
      LAYER M5 ;
        RECT  69.984 86.316 70.008 86.4 ;
    END
  END rr_w[276]
  PIN rr_w[277]
    DIRECTION INPUT ;
    USE SIGNAL ;
    PORT
      LAYER M5 ;
        RECT  70.224 86.316 70.248 86.4 ;
    END
  END rr_w[277]
  PIN rr_w[278]
    DIRECTION INPUT ;
    USE SIGNAL ;
    PORT
      LAYER M5 ;
        RECT  70.464 86.316 70.488 86.4 ;
    END
  END rr_w[278]
  PIN rr_w[279]
    DIRECTION INPUT ;
    USE SIGNAL ;
    PORT
      LAYER M5 ;
        RECT  70.752 86.316 70.776 86.4 ;
    END
  END rr_w[279]
  PIN rr_w[27]
    DIRECTION INPUT ;
    USE SIGNAL ;
    PORT
      LAYER M5 ;
        RECT  6.96 86.316 6.984 86.4 ;
    END
  END rr_w[27]
  PIN rr_w[280]
    DIRECTION INPUT ;
    USE SIGNAL ;
    PORT
      LAYER M5 ;
        RECT  70.992 86.316 71.016 86.4 ;
    END
  END rr_w[280]
  PIN rr_w[281]
    DIRECTION INPUT ;
    USE SIGNAL ;
    PORT
      LAYER M5 ;
        RECT  71.232 86.316 71.256 86.4 ;
    END
  END rr_w[281]
  PIN rr_w[282]
    DIRECTION INPUT ;
    USE SIGNAL ;
    PORT
      LAYER M5 ;
        RECT  71.52 86.316 71.544 86.4 ;
    END
  END rr_w[282]
  PIN rr_w[283]
    DIRECTION INPUT ;
    USE SIGNAL ;
    PORT
      LAYER M5 ;
        RECT  71.76 86.316 71.784 86.4 ;
    END
  END rr_w[283]
  PIN rr_w[284]
    DIRECTION INPUT ;
    USE SIGNAL ;
    PORT
      LAYER M5 ;
        RECT  72 86.316 72.024 86.4 ;
    END
  END rr_w[284]
  PIN rr_w[285]
    DIRECTION INPUT ;
    USE SIGNAL ;
    PORT
      LAYER M5 ;
        RECT  72.24 86.316 72.264 86.4 ;
    END
  END rr_w[285]
  PIN rr_w[286]
    DIRECTION INPUT ;
    USE SIGNAL ;
    PORT
      LAYER M5 ;
        RECT  72.528 86.316 72.552 86.4 ;
    END
  END rr_w[286]
  PIN rr_w[287]
    DIRECTION INPUT ;
    USE SIGNAL ;
    PORT
      LAYER M5 ;
        RECT  72.768 86.316 72.792 86.4 ;
    END
  END rr_w[287]
  PIN rr_w[288]
    DIRECTION INPUT ;
    USE SIGNAL ;
    PORT
      LAYER M5 ;
        RECT  73.008 86.316 73.032 86.4 ;
    END
  END rr_w[288]
  PIN rr_w[289]
    DIRECTION INPUT ;
    USE SIGNAL ;
    PORT
      LAYER M5 ;
        RECT  73.248 86.316 73.272 86.4 ;
    END
  END rr_w[289]
  PIN rr_w[28]
    DIRECTION INPUT ;
    USE SIGNAL ;
    PORT
      LAYER M5 ;
        RECT  7.2 86.316 7.224 86.4 ;
    END
  END rr_w[28]
  PIN rr_w[290]
    DIRECTION INPUT ;
    USE SIGNAL ;
    PORT
      LAYER M5 ;
        RECT  73.536 86.316 73.56 86.4 ;
    END
  END rr_w[290]
  PIN rr_w[291]
    DIRECTION INPUT ;
    USE SIGNAL ;
    PORT
      LAYER M5 ;
        RECT  73.776 86.316 73.8 86.4 ;
    END
  END rr_w[291]
  PIN rr_w[292]
    DIRECTION INPUT ;
    USE SIGNAL ;
    PORT
      LAYER M5 ;
        RECT  74.016 86.316 74.04 86.4 ;
    END
  END rr_w[292]
  PIN rr_w[293]
    DIRECTION INPUT ;
    USE SIGNAL ;
    PORT
      LAYER M5 ;
        RECT  74.304 86.316 74.328 86.4 ;
    END
  END rr_w[293]
  PIN rr_w[294]
    DIRECTION INPUT ;
    USE SIGNAL ;
    PORT
      LAYER M5 ;
        RECT  74.544 86.316 74.568 86.4 ;
    END
  END rr_w[294]
  PIN rr_w[295]
    DIRECTION INPUT ;
    USE SIGNAL ;
    PORT
      LAYER M5 ;
        RECT  74.784 86.316 74.808 86.4 ;
    END
  END rr_w[295]
  PIN rr_w[296]
    DIRECTION INPUT ;
    USE SIGNAL ;
    PORT
      LAYER M5 ;
        RECT  75.024 86.316 75.048 86.4 ;
    END
  END rr_w[296]
  PIN rr_w[297]
    DIRECTION INPUT ;
    USE SIGNAL ;
    PORT
      LAYER M5 ;
        RECT  75.312 86.316 75.336 86.4 ;
    END
  END rr_w[297]
  PIN rr_w[298]
    DIRECTION INPUT ;
    USE SIGNAL ;
    PORT
      LAYER M5 ;
        RECT  75.552 86.316 75.576 86.4 ;
    END
  END rr_w[298]
  PIN rr_w[299]
    DIRECTION INPUT ;
    USE SIGNAL ;
    PORT
      LAYER M5 ;
        RECT  75.792 86.316 75.816 86.4 ;
    END
  END rr_w[299]
  PIN rr_w[29]
    DIRECTION INPUT ;
    USE SIGNAL ;
    PORT
      LAYER M5 ;
        RECT  7.44 86.316 7.464 86.4 ;
    END
  END rr_w[29]
  PIN rr_w[2]
    DIRECTION INPUT ;
    USE SIGNAL ;
    PORT
      LAYER M5 ;
        RECT  0.624 86.316 0.648 86.4 ;
    END
  END rr_w[2]
  PIN rr_w[300]
    DIRECTION INPUT ;
    USE SIGNAL ;
    PORT
      LAYER M5 ;
        RECT  76.032 86.316 76.056 86.4 ;
    END
  END rr_w[300]
  PIN rr_w[301]
    DIRECTION INPUT ;
    USE SIGNAL ;
    PORT
      LAYER M5 ;
        RECT  76.32 86.316 76.344 86.4 ;
    END
  END rr_w[301]
  PIN rr_w[302]
    DIRECTION INPUT ;
    USE SIGNAL ;
    PORT
      LAYER M5 ;
        RECT  76.56 86.316 76.584 86.4 ;
    END
  END rr_w[302]
  PIN rr_w[303]
    DIRECTION INPUT ;
    USE SIGNAL ;
    PORT
      LAYER M5 ;
        RECT  76.8 86.316 76.824 86.4 ;
    END
  END rr_w[303]
  PIN rr_w[304]
    DIRECTION INPUT ;
    USE SIGNAL ;
    PORT
      LAYER M5 ;
        RECT  77.088 86.316 77.112 86.4 ;
    END
  END rr_w[304]
  PIN rr_w[305]
    DIRECTION INPUT ;
    USE SIGNAL ;
    PORT
      LAYER M5 ;
        RECT  77.328 86.316 77.352 86.4 ;
    END
  END rr_w[305]
  PIN rr_w[306]
    DIRECTION INPUT ;
    USE SIGNAL ;
    PORT
      LAYER M5 ;
        RECT  77.568 86.316 77.592 86.4 ;
    END
  END rr_w[306]
  PIN rr_w[307]
    DIRECTION INPUT ;
    USE SIGNAL ;
    PORT
      LAYER M5 ;
        RECT  77.808 86.316 77.832 86.4 ;
    END
  END rr_w[307]
  PIN rr_w[308]
    DIRECTION INPUT ;
    USE SIGNAL ;
    PORT
      LAYER M5 ;
        RECT  78.096 86.316 78.12 86.4 ;
    END
  END rr_w[308]
  PIN rr_w[309]
    DIRECTION INPUT ;
    USE SIGNAL ;
    PORT
      LAYER M5 ;
        RECT  78.336 86.316 78.36 86.4 ;
    END
  END rr_w[309]
  PIN rr_w[30]
    DIRECTION INPUT ;
    USE SIGNAL ;
    PORT
      LAYER M5 ;
        RECT  7.728 86.316 7.752 86.4 ;
    END
  END rr_w[30]
  PIN rr_w[310]
    DIRECTION INPUT ;
    USE SIGNAL ;
    PORT
      LAYER M5 ;
        RECT  78.576 86.316 78.6 86.4 ;
    END
  END rr_w[310]
  PIN rr_w[311]
    DIRECTION INPUT ;
    USE SIGNAL ;
    PORT
      LAYER M5 ;
        RECT  78.816 86.316 78.84 86.4 ;
    END
  END rr_w[311]
  PIN rr_w[312]
    DIRECTION INPUT ;
    USE SIGNAL ;
    PORT
      LAYER M5 ;
        RECT  79.104 86.316 79.128 86.4 ;
    END
  END rr_w[312]
  PIN rr_w[313]
    DIRECTION INPUT ;
    USE SIGNAL ;
    PORT
      LAYER M5 ;
        RECT  79.344 86.316 79.368 86.4 ;
    END
  END rr_w[313]
  PIN rr_w[314]
    DIRECTION INPUT ;
    USE SIGNAL ;
    PORT
      LAYER M5 ;
        RECT  79.584 86.316 79.608 86.4 ;
    END
  END rr_w[314]
  PIN rr_w[315]
    DIRECTION INPUT ;
    USE SIGNAL ;
    PORT
      LAYER M5 ;
        RECT  79.872 86.316 79.896 86.4 ;
    END
  END rr_w[315]
  PIN rr_w[316]
    DIRECTION INPUT ;
    USE SIGNAL ;
    PORT
      LAYER M5 ;
        RECT  80.112 86.316 80.136 86.4 ;
    END
  END rr_w[316]
  PIN rr_w[317]
    DIRECTION INPUT ;
    USE SIGNAL ;
    PORT
      LAYER M5 ;
        RECT  80.352 86.316 80.376 86.4 ;
    END
  END rr_w[317]
  PIN rr_w[318]
    DIRECTION INPUT ;
    USE SIGNAL ;
    PORT
      LAYER M5 ;
        RECT  80.592 86.316 80.616 86.4 ;
    END
  END rr_w[318]
  PIN rr_w[319]
    DIRECTION INPUT ;
    USE SIGNAL ;
    PORT
      LAYER M5 ;
        RECT  80.88 86.316 80.904 86.4 ;
    END
  END rr_w[319]
  PIN rr_w[31]
    DIRECTION INPUT ;
    USE SIGNAL ;
    PORT
      LAYER M5 ;
        RECT  7.968 86.316 7.992 86.4 ;
    END
  END rr_w[31]
  PIN rr_w[320]
    DIRECTION INPUT ;
    USE SIGNAL ;
    PORT
      LAYER M5 ;
        RECT  81.12 86.316 81.144 86.4 ;
    END
  END rr_w[320]
  PIN rr_w[321]
    DIRECTION INPUT ;
    USE SIGNAL ;
    PORT
      LAYER M5 ;
        RECT  81.36 86.316 81.384 86.4 ;
    END
  END rr_w[321]
  PIN rr_w[322]
    DIRECTION INPUT ;
    USE SIGNAL ;
    PORT
      LAYER M5 ;
        RECT  81.6 86.316 81.624 86.4 ;
    END
  END rr_w[322]
  PIN rr_w[323]
    DIRECTION INPUT ;
    USE SIGNAL ;
    PORT
      LAYER M5 ;
        RECT  81.888 86.316 81.912 86.4 ;
    END
  END rr_w[323]
  PIN rr_w[324]
    DIRECTION INPUT ;
    USE SIGNAL ;
    PORT
      LAYER M5 ;
        RECT  82.128 86.316 82.152 86.4 ;
    END
  END rr_w[324]
  PIN rr_w[325]
    DIRECTION INPUT ;
    USE SIGNAL ;
    PORT
      LAYER M5 ;
        RECT  82.368 86.316 82.392 86.4 ;
    END
  END rr_w[325]
  PIN rr_w[326]
    DIRECTION INPUT ;
    USE SIGNAL ;
    PORT
      LAYER M5 ;
        RECT  82.656 86.316 82.68 86.4 ;
    END
  END rr_w[326]
  PIN rr_w[327]
    DIRECTION INPUT ;
    USE SIGNAL ;
    PORT
      LAYER M5 ;
        RECT  82.896 86.316 82.92 86.4 ;
    END
  END rr_w[327]
  PIN rr_w[328]
    DIRECTION INPUT ;
    USE SIGNAL ;
    PORT
      LAYER M5 ;
        RECT  83.136 86.316 83.16 86.4 ;
    END
  END rr_w[328]
  PIN rr_w[329]
    DIRECTION INPUT ;
    USE SIGNAL ;
    PORT
      LAYER M5 ;
        RECT  83.376 86.316 83.4 86.4 ;
    END
  END rr_w[329]
  PIN rr_w[32]
    DIRECTION INPUT ;
    USE SIGNAL ;
    PORT
      LAYER M5 ;
        RECT  8.208 86.316 8.232 86.4 ;
    END
  END rr_w[32]
  PIN rr_w[330]
    DIRECTION INPUT ;
    USE SIGNAL ;
    PORT
      LAYER M5 ;
        RECT  83.664 86.316 83.688 86.4 ;
    END
  END rr_w[330]
  PIN rr_w[331]
    DIRECTION INPUT ;
    USE SIGNAL ;
    PORT
      LAYER M5 ;
        RECT  83.904 86.316 83.928 86.4 ;
    END
  END rr_w[331]
  PIN rr_w[332]
    DIRECTION INPUT ;
    USE SIGNAL ;
    PORT
      LAYER M5 ;
        RECT  84.144 86.316 84.168 86.4 ;
    END
  END rr_w[332]
  PIN rr_w[333]
    DIRECTION INPUT ;
    USE SIGNAL ;
    PORT
      LAYER M5 ;
        RECT  84.384 86.316 84.408 86.4 ;
    END
  END rr_w[333]
  PIN rr_w[334]
    DIRECTION INPUT ;
    USE SIGNAL ;
    PORT
      LAYER M5 ;
        RECT  84.672 86.316 84.696 86.4 ;
    END
  END rr_w[334]
  PIN rr_w[335]
    DIRECTION INPUT ;
    USE SIGNAL ;
    PORT
      LAYER M5 ;
        RECT  84.912 86.316 84.936 86.4 ;
    END
  END rr_w[335]
  PIN rr_w[336]
    DIRECTION INPUT ;
    USE SIGNAL ;
    PORT
      LAYER M5 ;
        RECT  85.152 86.316 85.176 86.4 ;
    END
  END rr_w[336]
  PIN rr_w[337]
    DIRECTION INPUT ;
    USE SIGNAL ;
    PORT
      LAYER M5 ;
        RECT  85.44 86.316 85.464 86.4 ;
    END
  END rr_w[337]
  PIN rr_w[338]
    DIRECTION INPUT ;
    USE SIGNAL ;
    PORT
      LAYER M5 ;
        RECT  85.68 86.316 85.704 86.4 ;
    END
  END rr_w[338]
  PIN rr_w[339]
    DIRECTION INPUT ;
    USE SIGNAL ;
    PORT
      LAYER M5 ;
        RECT  85.92 86.316 85.944 86.4 ;
    END
  END rr_w[339]
  PIN rr_w[33]
    DIRECTION INPUT ;
    USE SIGNAL ;
    PORT
      LAYER M5 ;
        RECT  8.448 86.316 8.472 86.4 ;
    END
  END rr_w[33]
  PIN rr_w[340]
    DIRECTION INPUT ;
    USE SIGNAL ;
    PORT
      LAYER M5 ;
        RECT  86.16 86.316 86.184 86.4 ;
    END
  END rr_w[340]
  PIN rr_w[341]
    DIRECTION INPUT ;
    USE SIGNAL ;
    PORT
      LAYER M5 ;
        RECT  86.448 86.316 86.472 86.4 ;
    END
  END rr_w[341]
  PIN rr_w[342]
    DIRECTION INPUT ;
    USE SIGNAL ;
    PORT
      LAYER M5 ;
        RECT  86.688 86.316 86.712 86.4 ;
    END
  END rr_w[342]
  PIN rr_w[343]
    DIRECTION INPUT ;
    USE SIGNAL ;
    PORT
      LAYER M5 ;
        RECT  86.928 86.316 86.952 86.4 ;
    END
  END rr_w[343]
  PIN rr_w[344]
    DIRECTION INPUT ;
    USE SIGNAL ;
    PORT
      LAYER M5 ;
        RECT  87.168 86.316 87.192 86.4 ;
    END
  END rr_w[344]
  PIN rr_w[345]
    DIRECTION INPUT ;
    USE SIGNAL ;
    PORT
      LAYER M5 ;
        RECT  87.456 86.316 87.48 86.4 ;
    END
  END rr_w[345]
  PIN rr_w[346]
    DIRECTION INPUT ;
    USE SIGNAL ;
    PORT
      LAYER M5 ;
        RECT  87.696 86.316 87.72 86.4 ;
    END
  END rr_w[346]
  PIN rr_w[347]
    DIRECTION INPUT ;
    USE SIGNAL ;
    PORT
      LAYER M5 ;
        RECT  87.936 86.316 87.96 86.4 ;
    END
  END rr_w[347]
  PIN rr_w[348]
    DIRECTION INPUT ;
    USE SIGNAL ;
    PORT
      LAYER M5 ;
        RECT  88.224 86.316 88.248 86.4 ;
    END
  END rr_w[348]
  PIN rr_w[349]
    DIRECTION INPUT ;
    USE SIGNAL ;
    PORT
      LAYER M5 ;
        RECT  88.464 86.316 88.488 86.4 ;
    END
  END rr_w[349]
  PIN rr_w[34]
    DIRECTION INPUT ;
    USE SIGNAL ;
    PORT
      LAYER M5 ;
        RECT  8.736 86.316 8.76 86.4 ;
    END
  END rr_w[34]
  PIN rr_w[350]
    DIRECTION INPUT ;
    USE SIGNAL ;
    PORT
      LAYER M5 ;
        RECT  88.704 86.316 88.728 86.4 ;
    END
  END rr_w[350]
  PIN rr_w[351]
    DIRECTION INPUT ;
    USE SIGNAL ;
    PORT
      LAYER M5 ;
        RECT  88.944 86.316 88.968 86.4 ;
    END
  END rr_w[351]
  PIN rr_w[352]
    DIRECTION INPUT ;
    USE SIGNAL ;
    PORT
      LAYER M5 ;
        RECT  89.232 86.316 89.256 86.4 ;
    END
  END rr_w[352]
  PIN rr_w[353]
    DIRECTION INPUT ;
    USE SIGNAL ;
    PORT
      LAYER M5 ;
        RECT  89.472 86.316 89.496 86.4 ;
    END
  END rr_w[353]
  PIN rr_w[354]
    DIRECTION INPUT ;
    USE SIGNAL ;
    PORT
      LAYER M5 ;
        RECT  89.712 86.316 89.736 86.4 ;
    END
  END rr_w[354]
  PIN rr_w[355]
    DIRECTION INPUT ;
    USE SIGNAL ;
    PORT
      LAYER M5 ;
        RECT  89.952 86.316 89.976 86.4 ;
    END
  END rr_w[355]
  PIN rr_w[356]
    DIRECTION INPUT ;
    USE SIGNAL ;
    PORT
      LAYER M5 ;
        RECT  90.24 86.316 90.264 86.4 ;
    END
  END rr_w[356]
  PIN rr_w[357]
    DIRECTION INPUT ;
    USE SIGNAL ;
    PORT
      LAYER M5 ;
        RECT  90.48 86.316 90.504 86.4 ;
    END
  END rr_w[357]
  PIN rr_w[358]
    DIRECTION INPUT ;
    USE SIGNAL ;
    PORT
      LAYER M5 ;
        RECT  90.72 86.316 90.744 86.4 ;
    END
  END rr_w[358]
  PIN rr_w[359]
    DIRECTION INPUT ;
    USE SIGNAL ;
    PORT
      LAYER M5 ;
        RECT  91.008 86.316 91.032 86.4 ;
    END
  END rr_w[359]
  PIN rr_w[35]
    DIRECTION INPUT ;
    USE SIGNAL ;
    PORT
      LAYER M5 ;
        RECT  8.976 86.316 9 86.4 ;
    END
  END rr_w[35]
  PIN rr_w[360]
    DIRECTION INPUT ;
    USE SIGNAL ;
    PORT
      LAYER M5 ;
        RECT  91.248 86.316 91.272 86.4 ;
    END
  END rr_w[360]
  PIN rr_w[361]
    DIRECTION INPUT ;
    USE SIGNAL ;
    PORT
      LAYER M5 ;
        RECT  91.488 86.316 91.512 86.4 ;
    END
  END rr_w[361]
  PIN rr_w[362]
    DIRECTION INPUT ;
    USE SIGNAL ;
    PORT
      LAYER M5 ;
        RECT  91.728 86.316 91.752 86.4 ;
    END
  END rr_w[362]
  PIN rr_w[363]
    DIRECTION INPUT ;
    USE SIGNAL ;
    PORT
      LAYER M5 ;
        RECT  92.016 86.316 92.04 86.4 ;
    END
  END rr_w[363]
  PIN rr_w[364]
    DIRECTION INPUT ;
    USE SIGNAL ;
    PORT
      LAYER M5 ;
        RECT  92.256 86.316 92.28 86.4 ;
    END
  END rr_w[364]
  PIN rr_w[365]
    DIRECTION INPUT ;
    USE SIGNAL ;
    PORT
      LAYER M5 ;
        RECT  92.496 86.316 92.52 86.4 ;
    END
  END rr_w[365]
  PIN rr_w[366]
    DIRECTION INPUT ;
    USE SIGNAL ;
    PORT
      LAYER M5 ;
        RECT  92.736 86.316 92.76 86.4 ;
    END
  END rr_w[366]
  PIN rr_w[367]
    DIRECTION INPUT ;
    USE SIGNAL ;
    PORT
      LAYER M5 ;
        RECT  93.024 86.316 93.048 86.4 ;
    END
  END rr_w[367]
  PIN rr_w[368]
    DIRECTION INPUT ;
    USE SIGNAL ;
    PORT
      LAYER M5 ;
        RECT  93.264 86.316 93.288 86.4 ;
    END
  END rr_w[368]
  PIN rr_w[369]
    DIRECTION INPUT ;
    USE SIGNAL ;
    PORT
      LAYER M5 ;
        RECT  93.504 86.316 93.528 86.4 ;
    END
  END rr_w[369]
  PIN rr_w[36]
    DIRECTION INPUT ;
    USE SIGNAL ;
    PORT
      LAYER M5 ;
        RECT  9.216 86.316 9.24 86.4 ;
    END
  END rr_w[36]
  PIN rr_w[370]
    DIRECTION INPUT ;
    USE SIGNAL ;
    PORT
      LAYER M5 ;
        RECT  93.792 86.316 93.816 86.4 ;
    END
  END rr_w[370]
  PIN rr_w[371]
    DIRECTION INPUT ;
    USE SIGNAL ;
    PORT
      LAYER M5 ;
        RECT  94.032 86.316 94.056 86.4 ;
    END
  END rr_w[371]
  PIN rr_w[372]
    DIRECTION INPUT ;
    USE SIGNAL ;
    PORT
      LAYER M5 ;
        RECT  94.272 86.316 94.296 86.4 ;
    END
  END rr_w[372]
  PIN rr_w[373]
    DIRECTION INPUT ;
    USE SIGNAL ;
    PORT
      LAYER M5 ;
        RECT  94.512 86.316 94.536 86.4 ;
    END
  END rr_w[373]
  PIN rr_w[374]
    DIRECTION INPUT ;
    USE SIGNAL ;
    PORT
      LAYER M5 ;
        RECT  94.8 86.316 94.824 86.4 ;
    END
  END rr_w[374]
  PIN rr_w[375]
    DIRECTION INPUT ;
    USE SIGNAL ;
    PORT
      LAYER M5 ;
        RECT  95.04 86.316 95.064 86.4 ;
    END
  END rr_w[375]
  PIN rr_w[376]
    DIRECTION INPUT ;
    USE SIGNAL ;
    PORT
      LAYER M5 ;
        RECT  95.28 86.316 95.304 86.4 ;
    END
  END rr_w[376]
  PIN rr_w[377]
    DIRECTION INPUT ;
    USE SIGNAL ;
    PORT
      LAYER M5 ;
        RECT  95.52 86.316 95.544 86.4 ;
    END
  END rr_w[377]
  PIN rr_w[378]
    DIRECTION INPUT ;
    USE SIGNAL ;
    PORT
      LAYER M5 ;
        RECT  95.808 86.316 95.832 86.4 ;
    END
  END rr_w[378]
  PIN rr_w[379]
    DIRECTION INPUT ;
    USE SIGNAL ;
    PORT
      LAYER M5 ;
        RECT  96.048 86.316 96.072 86.4 ;
    END
  END rr_w[379]
  PIN rr_w[37]
    DIRECTION INPUT ;
    USE SIGNAL ;
    PORT
      LAYER M5 ;
        RECT  9.504 86.316 9.528 86.4 ;
    END
  END rr_w[37]
  PIN rr_w[380]
    DIRECTION INPUT ;
    USE SIGNAL ;
    PORT
      LAYER M5 ;
        RECT  96.288 86.316 96.312 86.4 ;
    END
  END rr_w[380]
  PIN rr_w[381]
    DIRECTION INPUT ;
    USE SIGNAL ;
    PORT
      LAYER M5 ;
        RECT  96.576 86.316 96.6 86.4 ;
    END
  END rr_w[381]
  PIN rr_w[382]
    DIRECTION INPUT ;
    USE SIGNAL ;
    PORT
      LAYER M5 ;
        RECT  96.816 86.316 96.84 86.4 ;
    END
  END rr_w[382]
  PIN rr_w[383]
    DIRECTION INPUT ;
    USE SIGNAL ;
    PORT
      LAYER M5 ;
        RECT  97.056 86.316 97.08 86.4 ;
    END
  END rr_w[383]
  PIN rr_w[384]
    DIRECTION INPUT ;
    USE SIGNAL ;
    PORT
      LAYER M5 ;
        RECT  97.296 86.316 97.32 86.4 ;
    END
  END rr_w[384]
  PIN rr_w[385]
    DIRECTION INPUT ;
    USE SIGNAL ;
    PORT
      LAYER M5 ;
        RECT  97.584 86.316 97.608 86.4 ;
    END
  END rr_w[385]
  PIN rr_w[386]
    DIRECTION INPUT ;
    USE SIGNAL ;
    PORT
      LAYER M5 ;
        RECT  97.824 86.316 97.848 86.4 ;
    END
  END rr_w[386]
  PIN rr_w[387]
    DIRECTION INPUT ;
    USE SIGNAL ;
    PORT
      LAYER M5 ;
        RECT  98.064 86.316 98.088 86.4 ;
    END
  END rr_w[387]
  PIN rr_w[388]
    DIRECTION INPUT ;
    USE SIGNAL ;
    PORT
      LAYER M5 ;
        RECT  98.304 86.316 98.328 86.4 ;
    END
  END rr_w[388]
  PIN rr_w[389]
    DIRECTION INPUT ;
    USE SIGNAL ;
    PORT
      LAYER M5 ;
        RECT  98.592 86.316 98.616 86.4 ;
    END
  END rr_w[389]
  PIN rr_w[38]
    DIRECTION INPUT ;
    USE SIGNAL ;
    PORT
      LAYER M5 ;
        RECT  9.744 86.316 9.768 86.4 ;
    END
  END rr_w[38]
  PIN rr_w[390]
    DIRECTION INPUT ;
    USE SIGNAL ;
    PORT
      LAYER M5 ;
        RECT  98.832 86.316 98.856 86.4 ;
    END
  END rr_w[390]
  PIN rr_w[391]
    DIRECTION INPUT ;
    USE SIGNAL ;
    PORT
      LAYER M5 ;
        RECT  99.072 86.316 99.096 86.4 ;
    END
  END rr_w[391]
  PIN rr_w[392]
    DIRECTION INPUT ;
    USE SIGNAL ;
    PORT
      LAYER M5 ;
        RECT  99.36 86.316 99.384 86.4 ;
    END
  END rr_w[392]
  PIN rr_w[393]
    DIRECTION INPUT ;
    USE SIGNAL ;
    PORT
      LAYER M5 ;
        RECT  99.6 86.316 99.624 86.4 ;
    END
  END rr_w[393]
  PIN rr_w[394]
    DIRECTION INPUT ;
    USE SIGNAL ;
    PORT
      LAYER M5 ;
        RECT  99.84 86.316 99.864 86.4 ;
    END
  END rr_w[394]
  PIN rr_w[395]
    DIRECTION INPUT ;
    USE SIGNAL ;
    PORT
      LAYER M5 ;
        RECT  100.08 86.316 100.104 86.4 ;
    END
  END rr_w[395]
  PIN rr_w[396]
    DIRECTION INPUT ;
    USE SIGNAL ;
    PORT
      LAYER M5 ;
        RECT  100.368 86.316 100.392 86.4 ;
    END
  END rr_w[396]
  PIN rr_w[397]
    DIRECTION INPUT ;
    USE SIGNAL ;
    PORT
      LAYER M5 ;
        RECT  100.608 86.316 100.632 86.4 ;
    END
  END rr_w[397]
  PIN rr_w[398]
    DIRECTION INPUT ;
    USE SIGNAL ;
    PORT
      LAYER M5 ;
        RECT  100.848 86.316 100.872 86.4 ;
    END
  END rr_w[398]
  PIN rr_w[399]
    DIRECTION INPUT ;
    USE SIGNAL ;
    PORT
      LAYER M5 ;
        RECT  101.088 86.316 101.112 86.4 ;
    END
  END rr_w[399]
  PIN rr_w[39]
    DIRECTION INPUT ;
    USE SIGNAL ;
    PORT
      LAYER M5 ;
        RECT  9.984 86.316 10.008 86.4 ;
    END
  END rr_w[39]
  PIN rr_w[3]
    DIRECTION INPUT ;
    USE SIGNAL ;
    PORT
      LAYER M5 ;
        RECT  0.864 86.316 0.888 86.4 ;
    END
  END rr_w[3]
  PIN rr_w[400]
    DIRECTION INPUT ;
    USE SIGNAL ;
    PORT
      LAYER M5 ;
        RECT  101.376 86.316 101.4 86.4 ;
    END
  END rr_w[400]
  PIN rr_w[401]
    DIRECTION INPUT ;
    USE SIGNAL ;
    PORT
      LAYER M5 ;
        RECT  101.616 86.316 101.64 86.4 ;
    END
  END rr_w[401]
  PIN rr_w[402]
    DIRECTION INPUT ;
    USE SIGNAL ;
    PORT
      LAYER M5 ;
        RECT  101.856 86.316 101.88 86.4 ;
    END
  END rr_w[402]
  PIN rr_w[403]
    DIRECTION INPUT ;
    USE SIGNAL ;
    PORT
      LAYER M5 ;
        RECT  102.144 86.316 102.168 86.4 ;
    END
  END rr_w[403]
  PIN rr_w[404]
    DIRECTION INPUT ;
    USE SIGNAL ;
    PORT
      LAYER M5 ;
        RECT  102.384 86.316 102.408 86.4 ;
    END
  END rr_w[404]
  PIN rr_w[405]
    DIRECTION INPUT ;
    USE SIGNAL ;
    PORT
      LAYER M5 ;
        RECT  102.624 86.316 102.648 86.4 ;
    END
  END rr_w[405]
  PIN rr_w[406]
    DIRECTION INPUT ;
    USE SIGNAL ;
    PORT
      LAYER M5 ;
        RECT  102.864 86.316 102.888 86.4 ;
    END
  END rr_w[406]
  PIN rr_w[407]
    DIRECTION INPUT ;
    USE SIGNAL ;
    PORT
      LAYER M5 ;
        RECT  103.152 86.316 103.176 86.4 ;
    END
  END rr_w[407]
  PIN rr_w[408]
    DIRECTION INPUT ;
    USE SIGNAL ;
    PORT
      LAYER M5 ;
        RECT  103.392 86.316 103.416 86.4 ;
    END
  END rr_w[408]
  PIN rr_w[409]
    DIRECTION INPUT ;
    USE SIGNAL ;
    PORT
      LAYER M5 ;
        RECT  103.632 86.316 103.656 86.4 ;
    END
  END rr_w[409]
  PIN rr_w[40]
    DIRECTION INPUT ;
    USE SIGNAL ;
    PORT
      LAYER M5 ;
        RECT  10.224 86.316 10.248 86.4 ;
    END
  END rr_w[40]
  PIN rr_w[410]
    DIRECTION INPUT ;
    USE SIGNAL ;
    PORT
      LAYER M5 ;
        RECT  103.92 86.316 103.944 86.4 ;
    END
  END rr_w[410]
  PIN rr_w[411]
    DIRECTION INPUT ;
    USE SIGNAL ;
    PORT
      LAYER M5 ;
        RECT  104.16 86.316 104.184 86.4 ;
    END
  END rr_w[411]
  PIN rr_w[412]
    DIRECTION INPUT ;
    USE SIGNAL ;
    PORT
      LAYER M5 ;
        RECT  104.4 86.316 104.424 86.4 ;
    END
  END rr_w[412]
  PIN rr_w[413]
    DIRECTION INPUT ;
    USE SIGNAL ;
    PORT
      LAYER M5 ;
        RECT  104.64 86.316 104.664 86.4 ;
    END
  END rr_w[413]
  PIN rr_w[414]
    DIRECTION INPUT ;
    USE SIGNAL ;
    PORT
      LAYER M5 ;
        RECT  104.928 86.316 104.952 86.4 ;
    END
  END rr_w[414]
  PIN rr_w[415]
    DIRECTION INPUT ;
    USE SIGNAL ;
    PORT
      LAYER M5 ;
        RECT  105.168 86.316 105.192 86.4 ;
    END
  END rr_w[415]
  PIN rr_w[416]
    DIRECTION INPUT ;
    USE SIGNAL ;
    PORT
      LAYER M5 ;
        RECT  105.408 86.316 105.432 86.4 ;
    END
  END rr_w[416]
  PIN rr_w[417]
    DIRECTION INPUT ;
    USE SIGNAL ;
    PORT
      LAYER M5 ;
        RECT  105.648 86.316 105.672 86.4 ;
    END
  END rr_w[417]
  PIN rr_w[418]
    DIRECTION INPUT ;
    USE SIGNAL ;
    PORT
      LAYER M5 ;
        RECT  105.936 86.316 105.96 86.4 ;
    END
  END rr_w[418]
  PIN rr_w[419]
    DIRECTION INPUT ;
    USE SIGNAL ;
    PORT
      LAYER M5 ;
        RECT  106.176 86.316 106.2 86.4 ;
    END
  END rr_w[419]
  PIN rr_w[41]
    DIRECTION INPUT ;
    USE SIGNAL ;
    PORT
      LAYER M5 ;
        RECT  10.512 86.316 10.536 86.4 ;
    END
  END rr_w[41]
  PIN rr_w[420]
    DIRECTION INPUT ;
    USE SIGNAL ;
    PORT
      LAYER M5 ;
        RECT  106.416 86.316 106.44 86.4 ;
    END
  END rr_w[420]
  PIN rr_w[421]
    DIRECTION INPUT ;
    USE SIGNAL ;
    PORT
      LAYER M5 ;
        RECT  106.704 86.316 106.728 86.4 ;
    END
  END rr_w[421]
  PIN rr_w[422]
    DIRECTION INPUT ;
    USE SIGNAL ;
    PORT
      LAYER M5 ;
        RECT  106.944 86.316 106.968 86.4 ;
    END
  END rr_w[422]
  PIN rr_w[423]
    DIRECTION INPUT ;
    USE SIGNAL ;
    PORT
      LAYER M5 ;
        RECT  107.184 86.316 107.208 86.4 ;
    END
  END rr_w[423]
  PIN rr_w[424]
    DIRECTION INPUT ;
    USE SIGNAL ;
    PORT
      LAYER M5 ;
        RECT  107.424 86.316 107.448 86.4 ;
    END
  END rr_w[424]
  PIN rr_w[425]
    DIRECTION INPUT ;
    USE SIGNAL ;
    PORT
      LAYER M5 ;
        RECT  107.712 86.316 107.736 86.4 ;
    END
  END rr_w[425]
  PIN rr_w[426]
    DIRECTION INPUT ;
    USE SIGNAL ;
    PORT
      LAYER M5 ;
        RECT  107.952 86.316 107.976 86.4 ;
    END
  END rr_w[426]
  PIN rr_w[427]
    DIRECTION INPUT ;
    USE SIGNAL ;
    PORT
      LAYER M5 ;
        RECT  108.192 86.316 108.216 86.4 ;
    END
  END rr_w[427]
  PIN rr_w[428]
    DIRECTION INPUT ;
    USE SIGNAL ;
    PORT
      LAYER M5 ;
        RECT  108.432 86.316 108.456 86.4 ;
    END
  END rr_w[428]
  PIN rr_w[429]
    DIRECTION INPUT ;
    USE SIGNAL ;
    PORT
      LAYER M5 ;
        RECT  108.72 86.316 108.744 86.4 ;
    END
  END rr_w[429]
  PIN rr_w[42]
    DIRECTION INPUT ;
    USE SIGNAL ;
    PORT
      LAYER M5 ;
        RECT  10.752 86.316 10.776 86.4 ;
    END
  END rr_w[42]
  PIN rr_w[430]
    DIRECTION INPUT ;
    USE SIGNAL ;
    PORT
      LAYER M5 ;
        RECT  108.96 86.316 108.984 86.4 ;
    END
  END rr_w[430]
  PIN rr_w[431]
    DIRECTION INPUT ;
    USE SIGNAL ;
    PORT
      LAYER M5 ;
        RECT  109.2 86.316 109.224 86.4 ;
    END
  END rr_w[431]
  PIN rr_w[432]
    DIRECTION INPUT ;
    USE SIGNAL ;
    PORT
      LAYER M5 ;
        RECT  109.488 86.316 109.512 86.4 ;
    END
  END rr_w[432]
  PIN rr_w[433]
    DIRECTION INPUT ;
    USE SIGNAL ;
    PORT
      LAYER M5 ;
        RECT  109.728 86.316 109.752 86.4 ;
    END
  END rr_w[433]
  PIN rr_w[434]
    DIRECTION INPUT ;
    USE SIGNAL ;
    PORT
      LAYER M5 ;
        RECT  109.968 86.316 109.992 86.4 ;
    END
  END rr_w[434]
  PIN rr_w[435]
    DIRECTION INPUT ;
    USE SIGNAL ;
    PORT
      LAYER M5 ;
        RECT  110.208 86.316 110.232 86.4 ;
    END
  END rr_w[435]
  PIN rr_w[436]
    DIRECTION INPUT ;
    USE SIGNAL ;
    PORT
      LAYER M5 ;
        RECT  110.496 86.316 110.52 86.4 ;
    END
  END rr_w[436]
  PIN rr_w[437]
    DIRECTION INPUT ;
    USE SIGNAL ;
    PORT
      LAYER M5 ;
        RECT  110.736 86.316 110.76 86.4 ;
    END
  END rr_w[437]
  PIN rr_w[438]
    DIRECTION INPUT ;
    USE SIGNAL ;
    PORT
      LAYER M5 ;
        RECT  110.976 86.316 111 86.4 ;
    END
  END rr_w[438]
  PIN rr_w[439]
    DIRECTION INPUT ;
    USE SIGNAL ;
    PORT
      LAYER M5 ;
        RECT  111.216 86.316 111.24 86.4 ;
    END
  END rr_w[439]
  PIN rr_w[43]
    DIRECTION INPUT ;
    USE SIGNAL ;
    PORT
      LAYER M5 ;
        RECT  10.992 86.316 11.016 86.4 ;
    END
  END rr_w[43]
  PIN rr_w[440]
    DIRECTION INPUT ;
    USE SIGNAL ;
    PORT
      LAYER M5 ;
        RECT  111.504 86.316 111.528 86.4 ;
    END
  END rr_w[440]
  PIN rr_w[441]
    DIRECTION INPUT ;
    USE SIGNAL ;
    PORT
      LAYER M5 ;
        RECT  111.744 86.316 111.768 86.4 ;
    END
  END rr_w[441]
  PIN rr_w[442]
    DIRECTION INPUT ;
    USE SIGNAL ;
    PORT
      LAYER M5 ;
        RECT  111.984 86.316 112.008 86.4 ;
    END
  END rr_w[442]
  PIN rr_w[443]
    DIRECTION INPUT ;
    USE SIGNAL ;
    PORT
      LAYER M5 ;
        RECT  112.272 86.316 112.296 86.4 ;
    END
  END rr_w[443]
  PIN rr_w[444]
    DIRECTION INPUT ;
    USE SIGNAL ;
    PORT
      LAYER M5 ;
        RECT  112.512 86.316 112.536 86.4 ;
    END
  END rr_w[444]
  PIN rr_w[445]
    DIRECTION INPUT ;
    USE SIGNAL ;
    PORT
      LAYER M5 ;
        RECT  112.752 86.316 112.776 86.4 ;
    END
  END rr_w[445]
  PIN rr_w[446]
    DIRECTION INPUT ;
    USE SIGNAL ;
    PORT
      LAYER M5 ;
        RECT  112.992 86.316 113.016 86.4 ;
    END
  END rr_w[446]
  PIN rr_w[447]
    DIRECTION INPUT ;
    USE SIGNAL ;
    PORT
      LAYER M5 ;
        RECT  113.28 86.316 113.304 86.4 ;
    END
  END rr_w[447]
  PIN rr_w[448]
    DIRECTION INPUT ;
    USE SIGNAL ;
    PORT
      LAYER M5 ;
        RECT  113.52 86.316 113.544 86.4 ;
    END
  END rr_w[448]
  PIN rr_w[449]
    DIRECTION INPUT ;
    USE SIGNAL ;
    PORT
      LAYER M5 ;
        RECT  113.76 86.316 113.784 86.4 ;
    END
  END rr_w[449]
  PIN rr_w[44]
    DIRECTION INPUT ;
    USE SIGNAL ;
    PORT
      LAYER M5 ;
        RECT  11.232 86.316 11.256 86.4 ;
    END
  END rr_w[44]
  PIN rr_w[450]
    DIRECTION INPUT ;
    USE SIGNAL ;
    PORT
      LAYER M5 ;
        RECT  114 86.316 114.024 86.4 ;
    END
  END rr_w[450]
  PIN rr_w[451]
    DIRECTION INPUT ;
    USE SIGNAL ;
    PORT
      LAYER M5 ;
        RECT  114.288 86.316 114.312 86.4 ;
    END
  END rr_w[451]
  PIN rr_w[452]
    DIRECTION INPUT ;
    USE SIGNAL ;
    PORT
      LAYER M5 ;
        RECT  114.528 86.316 114.552 86.4 ;
    END
  END rr_w[452]
  PIN rr_w[453]
    DIRECTION INPUT ;
    USE SIGNAL ;
    PORT
      LAYER M5 ;
        RECT  114.768 86.316 114.792 86.4 ;
    END
  END rr_w[453]
  PIN rr_w[454]
    DIRECTION INPUT ;
    USE SIGNAL ;
    PORT
      LAYER M5 ;
        RECT  115.056 86.316 115.08 86.4 ;
    END
  END rr_w[454]
  PIN rr_w[455]
    DIRECTION INPUT ;
    USE SIGNAL ;
    PORT
      LAYER M5 ;
        RECT  115.296 86.316 115.32 86.4 ;
    END
  END rr_w[455]
  PIN rr_w[456]
    DIRECTION INPUT ;
    USE SIGNAL ;
    PORT
      LAYER M5 ;
        RECT  115.536 86.316 115.56 86.4 ;
    END
  END rr_w[456]
  PIN rr_w[457]
    DIRECTION INPUT ;
    USE SIGNAL ;
    PORT
      LAYER M5 ;
        RECT  115.776 86.316 115.8 86.4 ;
    END
  END rr_w[457]
  PIN rr_w[458]
    DIRECTION INPUT ;
    USE SIGNAL ;
    PORT
      LAYER M5 ;
        RECT  116.064 86.316 116.088 86.4 ;
    END
  END rr_w[458]
  PIN rr_w[459]
    DIRECTION INPUT ;
    USE SIGNAL ;
    PORT
      LAYER M5 ;
        RECT  116.304 86.316 116.328 86.4 ;
    END
  END rr_w[459]
  PIN rr_w[45]
    DIRECTION INPUT ;
    USE SIGNAL ;
    PORT
      LAYER M5 ;
        RECT  11.52 86.316 11.544 86.4 ;
    END
  END rr_w[45]
  PIN rr_w[460]
    DIRECTION INPUT ;
    USE SIGNAL ;
    PORT
      LAYER M5 ;
        RECT  116.544 86.316 116.568 86.4 ;
    END
  END rr_w[460]
  PIN rr_w[461]
    DIRECTION INPUT ;
    USE SIGNAL ;
    PORT
      LAYER M5 ;
        RECT  116.784 86.316 116.808 86.4 ;
    END
  END rr_w[461]
  PIN rr_w[462]
    DIRECTION INPUT ;
    USE SIGNAL ;
    PORT
      LAYER M5 ;
        RECT  117.072 86.316 117.096 86.4 ;
    END
  END rr_w[462]
  PIN rr_w[463]
    DIRECTION INPUT ;
    USE SIGNAL ;
    PORT
      LAYER M5 ;
        RECT  117.312 86.316 117.336 86.4 ;
    END
  END rr_w[463]
  PIN rr_w[464]
    DIRECTION INPUT ;
    USE SIGNAL ;
    PORT
      LAYER M5 ;
        RECT  117.552 86.316 117.576 86.4 ;
    END
  END rr_w[464]
  PIN rr_w[465]
    DIRECTION INPUT ;
    USE SIGNAL ;
    PORT
      LAYER M5 ;
        RECT  117.84 86.316 117.864 86.4 ;
    END
  END rr_w[465]
  PIN rr_w[466]
    DIRECTION INPUT ;
    USE SIGNAL ;
    PORT
      LAYER M5 ;
        RECT  118.08 86.316 118.104 86.4 ;
    END
  END rr_w[466]
  PIN rr_w[467]
    DIRECTION INPUT ;
    USE SIGNAL ;
    PORT
      LAYER M5 ;
        RECT  118.32 86.316 118.344 86.4 ;
    END
  END rr_w[467]
  PIN rr_w[468]
    DIRECTION INPUT ;
    USE SIGNAL ;
    PORT
      LAYER M5 ;
        RECT  118.56 86.316 118.584 86.4 ;
    END
  END rr_w[468]
  PIN rr_w[469]
    DIRECTION INPUT ;
    USE SIGNAL ;
    PORT
      LAYER M5 ;
        RECT  118.848 86.316 118.872 86.4 ;
    END
  END rr_w[469]
  PIN rr_w[46]
    DIRECTION INPUT ;
    USE SIGNAL ;
    PORT
      LAYER M5 ;
        RECT  11.76 86.316 11.784 86.4 ;
    END
  END rr_w[46]
  PIN rr_w[470]
    DIRECTION INPUT ;
    USE SIGNAL ;
    PORT
      LAYER M5 ;
        RECT  119.088 86.316 119.112 86.4 ;
    END
  END rr_w[470]
  PIN rr_w[471]
    DIRECTION INPUT ;
    USE SIGNAL ;
    PORT
      LAYER M5 ;
        RECT  119.328 86.316 119.352 86.4 ;
    END
  END rr_w[471]
  PIN rr_w[472]
    DIRECTION INPUT ;
    USE SIGNAL ;
    PORT
      LAYER M5 ;
        RECT  119.568 86.316 119.592 86.4 ;
    END
  END rr_w[472]
  PIN rr_w[473]
    DIRECTION INPUT ;
    USE SIGNAL ;
    PORT
      LAYER M5 ;
        RECT  119.856 86.316 119.88 86.4 ;
    END
  END rr_w[473]
  PIN rr_w[474]
    DIRECTION INPUT ;
    USE SIGNAL ;
    PORT
      LAYER M5 ;
        RECT  120.096 86.316 120.12 86.4 ;
    END
  END rr_w[474]
  PIN rr_w[475]
    DIRECTION INPUT ;
    USE SIGNAL ;
    PORT
      LAYER M5 ;
        RECT  120.336 86.316 120.36 86.4 ;
    END
  END rr_w[475]
  PIN rr_w[476]
    DIRECTION INPUT ;
    USE SIGNAL ;
    PORT
      LAYER M5 ;
        RECT  120.624 86.316 120.648 86.4 ;
    END
  END rr_w[476]
  PIN rr_w[477]
    DIRECTION INPUT ;
    USE SIGNAL ;
    PORT
      LAYER M5 ;
        RECT  120.864 86.316 120.888 86.4 ;
    END
  END rr_w[477]
  PIN rr_w[478]
    DIRECTION INPUT ;
    USE SIGNAL ;
    PORT
      LAYER M5 ;
        RECT  121.104 86.316 121.128 86.4 ;
    END
  END rr_w[478]
  PIN rr_w[479]
    DIRECTION INPUT ;
    USE SIGNAL ;
    PORT
      LAYER M5 ;
        RECT  121.344 86.316 121.368 86.4 ;
    END
  END rr_w[479]
  PIN rr_w[47]
    DIRECTION INPUT ;
    USE SIGNAL ;
    PORT
      LAYER M5 ;
        RECT  12 86.316 12.024 86.4 ;
    END
  END rr_w[47]
  PIN rr_w[480]
    DIRECTION INPUT ;
    USE SIGNAL ;
    PORT
      LAYER M5 ;
        RECT  121.632 86.316 121.656 86.4 ;
    END
  END rr_w[480]
  PIN rr_w[481]
    DIRECTION INPUT ;
    USE SIGNAL ;
    PORT
      LAYER M5 ;
        RECT  121.872 86.316 121.896 86.4 ;
    END
  END rr_w[481]
  PIN rr_w[482]
    DIRECTION INPUT ;
    USE SIGNAL ;
    PORT
      LAYER M5 ;
        RECT  122.112 86.316 122.136 86.4 ;
    END
  END rr_w[482]
  PIN rr_w[483]
    DIRECTION INPUT ;
    USE SIGNAL ;
    PORT
      LAYER M5 ;
        RECT  122.352 86.316 122.376 86.4 ;
    END
  END rr_w[483]
  PIN rr_w[484]
    DIRECTION INPUT ;
    USE SIGNAL ;
    PORT
      LAYER M5 ;
        RECT  122.64 86.316 122.664 86.4 ;
    END
  END rr_w[484]
  PIN rr_w[485]
    DIRECTION INPUT ;
    USE SIGNAL ;
    PORT
      LAYER M5 ;
        RECT  122.88 86.316 122.904 86.4 ;
    END
  END rr_w[485]
  PIN rr_w[486]
    DIRECTION INPUT ;
    USE SIGNAL ;
    PORT
      LAYER M5 ;
        RECT  123.12 86.316 123.144 86.4 ;
    END
  END rr_w[486]
  PIN rr_w[487]
    DIRECTION INPUT ;
    USE SIGNAL ;
    PORT
      LAYER M5 ;
        RECT  123.408 86.316 123.432 86.4 ;
    END
  END rr_w[487]
  PIN rr_w[488]
    DIRECTION INPUT ;
    USE SIGNAL ;
    PORT
      LAYER M5 ;
        RECT  123.648 86.316 123.672 86.4 ;
    END
  END rr_w[488]
  PIN rr_w[489]
    DIRECTION INPUT ;
    USE SIGNAL ;
    PORT
      LAYER M5 ;
        RECT  123.888 86.316 123.912 86.4 ;
    END
  END rr_w[489]
  PIN rr_w[48]
    DIRECTION INPUT ;
    USE SIGNAL ;
    PORT
      LAYER M5 ;
        RECT  12.288 86.316 12.312 86.4 ;
    END
  END rr_w[48]
  PIN rr_w[490]
    DIRECTION INPUT ;
    USE SIGNAL ;
    PORT
      LAYER M5 ;
        RECT  124.128 86.316 124.152 86.4 ;
    END
  END rr_w[490]
  PIN rr_w[491]
    DIRECTION INPUT ;
    USE SIGNAL ;
    PORT
      LAYER M5 ;
        RECT  124.416 86.316 124.44 86.4 ;
    END
  END rr_w[491]
  PIN rr_w[492]
    DIRECTION INPUT ;
    USE SIGNAL ;
    PORT
      LAYER M5 ;
        RECT  124.656 86.316 124.68 86.4 ;
    END
  END rr_w[492]
  PIN rr_w[493]
    DIRECTION INPUT ;
    USE SIGNAL ;
    PORT
      LAYER M5 ;
        RECT  124.896 86.316 124.92 86.4 ;
    END
  END rr_w[493]
  PIN rr_w[494]
    DIRECTION INPUT ;
    USE SIGNAL ;
    PORT
      LAYER M5 ;
        RECT  125.136 86.316 125.16 86.4 ;
    END
  END rr_w[494]
  PIN rr_w[495]
    DIRECTION INPUT ;
    USE SIGNAL ;
    PORT
      LAYER M5 ;
        RECT  125.424 86.316 125.448 86.4 ;
    END
  END rr_w[495]
  PIN rr_w[496]
    DIRECTION INPUT ;
    USE SIGNAL ;
    PORT
      LAYER M5 ;
        RECT  125.664 86.316 125.688 86.4 ;
    END
  END rr_w[496]
  PIN rr_w[497]
    DIRECTION INPUT ;
    USE SIGNAL ;
    PORT
      LAYER M5 ;
        RECT  125.904 86.316 125.928 86.4 ;
    END
  END rr_w[497]
  PIN rr_w[498]
    DIRECTION INPUT ;
    USE SIGNAL ;
    PORT
      LAYER M5 ;
        RECT  126.192 86.316 126.216 86.4 ;
    END
  END rr_w[498]
  PIN rr_w[499]
    DIRECTION INPUT ;
    USE SIGNAL ;
    PORT
      LAYER M5 ;
        RECT  126.432 86.316 126.456 86.4 ;
    END
  END rr_w[499]
  PIN rr_w[49]
    DIRECTION INPUT ;
    USE SIGNAL ;
    PORT
      LAYER M5 ;
        RECT  12.528 86.316 12.552 86.4 ;
    END
  END rr_w[49]
  PIN rr_w[4]
    DIRECTION INPUT ;
    USE SIGNAL ;
    PORT
      LAYER M5 ;
        RECT  1.104 86.316 1.128 86.4 ;
    END
  END rr_w[4]
  PIN rr_w[500]
    DIRECTION INPUT ;
    USE SIGNAL ;
    PORT
      LAYER M5 ;
        RECT  126.672 86.316 126.696 86.4 ;
    END
  END rr_w[500]
  PIN rr_w[501]
    DIRECTION INPUT ;
    USE SIGNAL ;
    PORT
      LAYER M5 ;
        RECT  126.912 86.316 126.936 86.4 ;
    END
  END rr_w[501]
  PIN rr_w[502]
    DIRECTION INPUT ;
    USE SIGNAL ;
    PORT
      LAYER M5 ;
        RECT  127.2 86.316 127.224 86.4 ;
    END
  END rr_w[502]
  PIN rr_w[503]
    DIRECTION INPUT ;
    USE SIGNAL ;
    PORT
      LAYER M5 ;
        RECT  127.44 86.316 127.464 86.4 ;
    END
  END rr_w[503]
  PIN rr_w[504]
    DIRECTION INPUT ;
    USE SIGNAL ;
    PORT
      LAYER M5 ;
        RECT  127.68 86.316 127.704 86.4 ;
    END
  END rr_w[504]
  PIN rr_w[505]
    DIRECTION INPUT ;
    USE SIGNAL ;
    PORT
      LAYER M5 ;
        RECT  127.92 86.316 127.944 86.4 ;
    END
  END rr_w[505]
  PIN rr_w[506]
    DIRECTION INPUT ;
    USE SIGNAL ;
    PORT
      LAYER M5 ;
        RECT  128.208 86.316 128.232 86.4 ;
    END
  END rr_w[506]
  PIN rr_w[507]
    DIRECTION INPUT ;
    USE SIGNAL ;
    PORT
      LAYER M5 ;
        RECT  128.448 86.316 128.472 86.4 ;
    END
  END rr_w[507]
  PIN rr_w[508]
    DIRECTION INPUT ;
    USE SIGNAL ;
    PORT
      LAYER M5 ;
        RECT  128.688 86.316 128.712 86.4 ;
    END
  END rr_w[508]
  PIN rr_w[509]
    DIRECTION INPUT ;
    USE SIGNAL ;
    PORT
      LAYER M5 ;
        RECT  128.976 86.316 129 86.4 ;
    END
  END rr_w[509]
  PIN rr_w[50]
    DIRECTION INPUT ;
    USE SIGNAL ;
    PORT
      LAYER M5 ;
        RECT  12.768 86.316 12.792 86.4 ;
    END
  END rr_w[50]
  PIN rr_w[510]
    DIRECTION INPUT ;
    USE SIGNAL ;
    PORT
      LAYER M5 ;
        RECT  129.216 86.316 129.24 86.4 ;
    END
  END rr_w[510]
  PIN rr_w[511]
    DIRECTION INPUT ;
    USE SIGNAL ;
    PORT
      LAYER M5 ;
        RECT  129.456 86.316 129.48 86.4 ;
    END
  END rr_w[511]
  PIN rr_w[51]
    DIRECTION INPUT ;
    USE SIGNAL ;
    PORT
      LAYER M5 ;
        RECT  13.008 86.316 13.032 86.4 ;
    END
  END rr_w[51]
  PIN rr_w[52]
    DIRECTION INPUT ;
    USE SIGNAL ;
    PORT
      LAYER M5 ;
        RECT  13.296 86.316 13.32 86.4 ;
    END
  END rr_w[52]
  PIN rr_w[53]
    DIRECTION INPUT ;
    USE SIGNAL ;
    PORT
      LAYER M5 ;
        RECT  13.536 86.316 13.56 86.4 ;
    END
  END rr_w[53]
  PIN rr_w[54]
    DIRECTION INPUT ;
    USE SIGNAL ;
    PORT
      LAYER M5 ;
        RECT  13.776 86.316 13.8 86.4 ;
    END
  END rr_w[54]
  PIN rr_w[55]
    DIRECTION INPUT ;
    USE SIGNAL ;
    PORT
      LAYER M5 ;
        RECT  14.016 86.316 14.04 86.4 ;
    END
  END rr_w[55]
  PIN rr_w[56]
    DIRECTION INPUT ;
    USE SIGNAL ;
    PORT
      LAYER M5 ;
        RECT  14.304 86.316 14.328 86.4 ;
    END
  END rr_w[56]
  PIN rr_w[57]
    DIRECTION INPUT ;
    USE SIGNAL ;
    PORT
      LAYER M5 ;
        RECT  14.544 86.316 14.568 86.4 ;
    END
  END rr_w[57]
  PIN rr_w[58]
    DIRECTION INPUT ;
    USE SIGNAL ;
    PORT
      LAYER M5 ;
        RECT  14.784 86.316 14.808 86.4 ;
    END
  END rr_w[58]
  PIN rr_w[59]
    DIRECTION INPUT ;
    USE SIGNAL ;
    PORT
      LAYER M5 ;
        RECT  15.072 86.316 15.096 86.4 ;
    END
  END rr_w[59]
  PIN rr_w[5]
    DIRECTION INPUT ;
    USE SIGNAL ;
    PORT
      LAYER M5 ;
        RECT  1.392 86.316 1.416 86.4 ;
    END
  END rr_w[5]
  PIN rr_w[60]
    DIRECTION INPUT ;
    USE SIGNAL ;
    PORT
      LAYER M5 ;
        RECT  15.312 86.316 15.336 86.4 ;
    END
  END rr_w[60]
  PIN rr_w[61]
    DIRECTION INPUT ;
    USE SIGNAL ;
    PORT
      LAYER M5 ;
        RECT  15.552 86.316 15.576 86.4 ;
    END
  END rr_w[61]
  PIN rr_w[62]
    DIRECTION INPUT ;
    USE SIGNAL ;
    PORT
      LAYER M5 ;
        RECT  15.792 86.316 15.816 86.4 ;
    END
  END rr_w[62]
  PIN rr_w[63]
    DIRECTION INPUT ;
    USE SIGNAL ;
    PORT
      LAYER M5 ;
        RECT  16.08 86.316 16.104 86.4 ;
    END
  END rr_w[63]
  PIN rr_w[64]
    DIRECTION INPUT ;
    USE SIGNAL ;
    PORT
      LAYER M5 ;
        RECT  16.32 86.316 16.344 86.4 ;
    END
  END rr_w[64]
  PIN rr_w[65]
    DIRECTION INPUT ;
    USE SIGNAL ;
    PORT
      LAYER M5 ;
        RECT  16.56 86.316 16.584 86.4 ;
    END
  END rr_w[65]
  PIN rr_w[66]
    DIRECTION INPUT ;
    USE SIGNAL ;
    PORT
      LAYER M5 ;
        RECT  16.8 86.316 16.824 86.4 ;
    END
  END rr_w[66]
  PIN rr_w[67]
    DIRECTION INPUT ;
    USE SIGNAL ;
    PORT
      LAYER M5 ;
        RECT  17.088 86.316 17.112 86.4 ;
    END
  END rr_w[67]
  PIN rr_w[68]
    DIRECTION INPUT ;
    USE SIGNAL ;
    PORT
      LAYER M5 ;
        RECT  17.328 86.316 17.352 86.4 ;
    END
  END rr_w[68]
  PIN rr_w[69]
    DIRECTION INPUT ;
    USE SIGNAL ;
    PORT
      LAYER M5 ;
        RECT  17.568 86.316 17.592 86.4 ;
    END
  END rr_w[69]
  PIN rr_w[6]
    DIRECTION INPUT ;
    USE SIGNAL ;
    PORT
      LAYER M5 ;
        RECT  1.632 86.316 1.656 86.4 ;
    END
  END rr_w[6]
  PIN rr_w[70]
    DIRECTION INPUT ;
    USE SIGNAL ;
    PORT
      LAYER M5 ;
        RECT  17.856 86.316 17.88 86.4 ;
    END
  END rr_w[70]
  PIN rr_w[71]
    DIRECTION INPUT ;
    USE SIGNAL ;
    PORT
      LAYER M5 ;
        RECT  18.096 86.316 18.12 86.4 ;
    END
  END rr_w[71]
  PIN rr_w[72]
    DIRECTION INPUT ;
    USE SIGNAL ;
    PORT
      LAYER M5 ;
        RECT  18.336 86.316 18.36 86.4 ;
    END
  END rr_w[72]
  PIN rr_w[73]
    DIRECTION INPUT ;
    USE SIGNAL ;
    PORT
      LAYER M5 ;
        RECT  18.576 86.316 18.6 86.4 ;
    END
  END rr_w[73]
  PIN rr_w[74]
    DIRECTION INPUT ;
    USE SIGNAL ;
    PORT
      LAYER M5 ;
        RECT  18.864 86.316 18.888 86.4 ;
    END
  END rr_w[74]
  PIN rr_w[75]
    DIRECTION INPUT ;
    USE SIGNAL ;
    PORT
      LAYER M5 ;
        RECT  19.104 86.316 19.128 86.4 ;
    END
  END rr_w[75]
  PIN rr_w[76]
    DIRECTION INPUT ;
    USE SIGNAL ;
    PORT
      LAYER M5 ;
        RECT  19.344 86.316 19.368 86.4 ;
    END
  END rr_w[76]
  PIN rr_w[77]
    DIRECTION INPUT ;
    USE SIGNAL ;
    PORT
      LAYER M5 ;
        RECT  19.584 86.316 19.608 86.4 ;
    END
  END rr_w[77]
  PIN rr_w[78]
    DIRECTION INPUT ;
    USE SIGNAL ;
    PORT
      LAYER M5 ;
        RECT  19.872 86.316 19.896 86.4 ;
    END
  END rr_w[78]
  PIN rr_w[79]
    DIRECTION INPUT ;
    USE SIGNAL ;
    PORT
      LAYER M5 ;
        RECT  20.112 86.316 20.136 86.4 ;
    END
  END rr_w[79]
  PIN rr_w[7]
    DIRECTION INPUT ;
    USE SIGNAL ;
    PORT
      LAYER M5 ;
        RECT  1.872 86.316 1.896 86.4 ;
    END
  END rr_w[7]
  PIN rr_w[80]
    DIRECTION INPUT ;
    USE SIGNAL ;
    PORT
      LAYER M5 ;
        RECT  20.352 86.316 20.376 86.4 ;
    END
  END rr_w[80]
  PIN rr_w[81]
    DIRECTION INPUT ;
    USE SIGNAL ;
    PORT
      LAYER M5 ;
        RECT  20.64 86.316 20.664 86.4 ;
    END
  END rr_w[81]
  PIN rr_w[82]
    DIRECTION INPUT ;
    USE SIGNAL ;
    PORT
      LAYER M5 ;
        RECT  20.88 86.316 20.904 86.4 ;
    END
  END rr_w[82]
  PIN rr_w[83]
    DIRECTION INPUT ;
    USE SIGNAL ;
    PORT
      LAYER M5 ;
        RECT  21.12 86.316 21.144 86.4 ;
    END
  END rr_w[83]
  PIN rr_w[84]
    DIRECTION INPUT ;
    USE SIGNAL ;
    PORT
      LAYER M5 ;
        RECT  21.36 86.316 21.384 86.4 ;
    END
  END rr_w[84]
  PIN rr_w[85]
    DIRECTION INPUT ;
    USE SIGNAL ;
    PORT
      LAYER M5 ;
        RECT  21.648 86.316 21.672 86.4 ;
    END
  END rr_w[85]
  PIN rr_w[86]
    DIRECTION INPUT ;
    USE SIGNAL ;
    PORT
      LAYER M5 ;
        RECT  21.888 86.316 21.912 86.4 ;
    END
  END rr_w[86]
  PIN rr_w[87]
    DIRECTION INPUT ;
    USE SIGNAL ;
    PORT
      LAYER M5 ;
        RECT  22.128 86.316 22.152 86.4 ;
    END
  END rr_w[87]
  PIN rr_w[88]
    DIRECTION INPUT ;
    USE SIGNAL ;
    PORT
      LAYER M5 ;
        RECT  22.368 86.316 22.392 86.4 ;
    END
  END rr_w[88]
  PIN rr_w[89]
    DIRECTION INPUT ;
    USE SIGNAL ;
    PORT
      LAYER M5 ;
        RECT  22.656 86.316 22.68 86.4 ;
    END
  END rr_w[89]
  PIN rr_w[8]
    DIRECTION INPUT ;
    USE SIGNAL ;
    PORT
      LAYER M5 ;
        RECT  2.16 86.316 2.184 86.4 ;
    END
  END rr_w[8]
  PIN rr_w[90]
    DIRECTION INPUT ;
    USE SIGNAL ;
    PORT
      LAYER M5 ;
        RECT  22.896 86.316 22.92 86.4 ;
    END
  END rr_w[90]
  PIN rr_w[91]
    DIRECTION INPUT ;
    USE SIGNAL ;
    PORT
      LAYER M5 ;
        RECT  23.136 86.316 23.16 86.4 ;
    END
  END rr_w[91]
  PIN rr_w[92]
    DIRECTION INPUT ;
    USE SIGNAL ;
    PORT
      LAYER M5 ;
        RECT  23.424 86.316 23.448 86.4 ;
    END
  END rr_w[92]
  PIN rr_w[93]
    DIRECTION INPUT ;
    USE SIGNAL ;
    PORT
      LAYER M5 ;
        RECT  23.664 86.316 23.688 86.4 ;
    END
  END rr_w[93]
  PIN rr_w[94]
    DIRECTION INPUT ;
    USE SIGNAL ;
    PORT
      LAYER M5 ;
        RECT  23.904 86.316 23.928 86.4 ;
    END
  END rr_w[94]
  PIN rr_w[95]
    DIRECTION INPUT ;
    USE SIGNAL ;
    PORT
      LAYER M5 ;
        RECT  24.144 86.316 24.168 86.4 ;
    END
  END rr_w[95]
  PIN rr_w[96]
    DIRECTION INPUT ;
    USE SIGNAL ;
    PORT
      LAYER M5 ;
        RECT  24.432 86.316 24.456 86.4 ;
    END
  END rr_w[96]
  PIN rr_w[97]
    DIRECTION INPUT ;
    USE SIGNAL ;
    PORT
      LAYER M5 ;
        RECT  24.672 86.316 24.696 86.4 ;
    END
  END rr_w[97]
  PIN rr_w[98]
    DIRECTION INPUT ;
    USE SIGNAL ;
    PORT
      LAYER M5 ;
        RECT  24.912 86.316 24.936 86.4 ;
    END
  END rr_w[98]
  PIN rr_w[99]
    DIRECTION INPUT ;
    USE SIGNAL ;
    PORT
      LAYER M5 ;
        RECT  25.152 86.316 25.176 86.4 ;
    END
  END rr_w[99]
  PIN rr_w[9]
    DIRECTION INPUT ;
    USE SIGNAL ;
    PORT
      LAYER M5 ;
        RECT  2.4 86.316 2.424 86.4 ;
    END
  END rr_w[9]
  PIN rsel[0]
    DIRECTION INPUT ;
    USE SIGNAL ;
    PORT
      LAYER M4 ;
        RECT  0 32.4 0.084 32.424 ;
    END
    PORT
      LAYER M4 ;
        RECT  0.06 32.4 2.365 32.424 ;
    END
  END rsel[0]
  PIN rsel[1]
    DIRECTION INPUT ;
    USE SIGNAL ;
    PORT
      LAYER M4 ;
        RECT  0 54 0.084 54.024 ;
    END
    PORT
      LAYER M4 ;
        RECT  0.06 54 2.408 54.024 ;
    END
  END rsel[1]
  PIN rsel[2]
    DIRECTION INPUT ;
    USE SIGNAL ;
    PORT
      LAYER M4 ;
        RECT  0 75.6 0.084 75.624 ;
    END
    PORT
      LAYER M4 ;
        RECT  0.06 75.6 2.365 75.624 ;
    END
  END rsel[2]
  PIN VSS
    DIRECTION INOUT ;
    USE GROUND ;
    PORT
      LAYER M5 ;
        RECT  126.6 2.137 126.72 84.263 ;
        RECT  121.2 2.137 121.32 84.263 ;
        RECT  115.8 2.137 115.92 84.263 ;
        RECT  110.4 2.137 110.52 84.263 ;
        RECT  105 2.137 105.12 84.263 ;
        RECT  99.6 2.137 99.72 84.263 ;
        RECT  94.2 2.137 94.32 84.263 ;
        RECT  88.8 2.137 88.92 84.263 ;
        RECT  83.4 2.137 83.52 84.263 ;
        RECT  78 2.137 78.12 84.263 ;
        RECT  72.6 2.137 72.72 84.263 ;
        RECT  67.2 2.137 67.32 84.263 ;
        RECT  61.8 2.137 61.92 84.263 ;
        RECT  56.4 2.137 56.52 84.263 ;
        RECT  51 2.137 51.12 84.263 ;
        RECT  45.6 2.137 45.72 84.263 ;
        RECT  40.2 2.137 40.32 84.263 ;
        RECT  34.8 2.137 34.92 84.263 ;
        RECT  29.4 2.137 29.52 84.263 ;
        RECT  24 2.137 24.12 84.263 ;
        RECT  18.6 2.137 18.72 84.263 ;
        RECT  13.2 2.137 13.32 84.263 ;
        RECT  7.8 2.137 7.92 84.263 ;
        RECT  2.4 2.137 2.52 84.263 ;
    END
  END VSS
  PIN VDD
    DIRECTION INOUT ;
    USE POWER ;
    PORT
      LAYER M5 ;
        RECT  126.792 2.151 126.912 84.249 ;
        RECT  121.392 2.151 121.512 84.249 ;
        RECT  115.992 2.151 116.112 84.249 ;
        RECT  110.592 2.151 110.712 84.249 ;
        RECT  105.192 2.151 105.312 84.249 ;
        RECT  99.792 2.151 99.912 84.249 ;
        RECT  94.392 2.151 94.512 84.249 ;
        RECT  88.992 2.151 89.112 84.249 ;
        RECT  83.592 2.151 83.712 84.249 ;
        RECT  78.192 2.151 78.312 84.249 ;
        RECT  72.792 2.151 72.912 84.249 ;
        RECT  67.392 2.151 67.512 84.249 ;
        RECT  61.992 2.151 62.112 84.249 ;
        RECT  56.592 2.151 56.712 84.249 ;
        RECT  51.192 2.151 51.312 84.249 ;
        RECT  45.792 2.151 45.912 84.249 ;
        RECT  40.392 2.151 40.512 84.249 ;
        RECT  34.992 2.151 35.112 84.249 ;
        RECT  29.592 2.151 29.712 84.249 ;
        RECT  24.192 2.151 24.312 84.249 ;
        RECT  18.792 2.151 18.912 84.249 ;
        RECT  13.392 2.151 13.512 84.249 ;
        RECT  7.992 2.151 8.112 84.249 ;
        RECT  2.592 2.151 2.712 84.249 ;
    END
  END VDD
  # OT_OBS_CLOSED layer=M5 d_um=1.536 added=227
  OBS
    LAYER RVTN ;
     RECT  2.16 2.16 127.44 2.295 ;
     RECT  2.16 2.565 127.44 2.835 ;
     RECT  2.16 3.105 127.44 3.375 ;
     RECT  2.16 3.645 127.44 3.915 ;
     RECT  2.16 4.185 127.44 4.455 ;
     RECT  2.16 4.725 127.44 4.995 ;
     RECT  2.16 5.265 127.44 5.535 ;
     RECT  2.16 5.805 127.44 6.075 ;
     RECT  2.16 6.345 127.44 6.615 ;
     RECT  2.16 6.885 127.44 7.155 ;
     RECT  2.16 7.425 127.44 7.695 ;
     RECT  2.16 7.965 127.44 8.235 ;
     RECT  2.16 8.505 127.44 8.775 ;
     RECT  2.16 9.045 127.44 9.315 ;
     RECT  2.16 9.585 127.44 9.855 ;
     RECT  2.16 10.125 127.44 10.395 ;
     RECT  2.16 10.665 127.44 10.935 ;
     RECT  2.16 11.205 127.44 11.475 ;
     RECT  2.16 11.745 127.44 12.015 ;
     RECT  2.16 12.285 127.44 12.555 ;
     RECT  2.16 12.825 127.44 13.095 ;
     RECT  2.16 13.365 127.44 13.635 ;
     RECT  2.16 13.905 127.44 14.175 ;
     RECT  2.16 14.445 127.44 14.715 ;
     RECT  2.16 14.985 127.44 15.255 ;
     RECT  2.16 15.525 127.44 15.795 ;
     RECT  2.16 16.065 127.44 16.335 ;
     RECT  2.16 16.605 127.44 16.875 ;
     RECT  2.16 17.145 127.44 17.415 ;
     RECT  2.16 17.685 127.44 17.955 ;
     RECT  2.16 18.225 127.44 18.495 ;
     RECT  2.16 18.765 127.44 19.035 ;
     RECT  2.16 19.305 127.44 19.575 ;
     RECT  2.16 19.845 127.44 20.115 ;
     RECT  2.16 20.385 127.44 20.655 ;
     RECT  2.16 20.925 127.44 21.195 ;
     RECT  2.16 21.465 127.44 21.735 ;
     RECT  2.16 22.005 127.44 22.275 ;
     RECT  2.16 22.545 127.44 22.815 ;
     RECT  2.16 23.085 127.44 23.355 ;
     RECT  2.16 23.625 127.44 23.895 ;
     RECT  2.16 24.165 127.44 24.435 ;
     RECT  2.16 24.705 127.44 24.975 ;
     RECT  2.16 25.245 127.44 25.515 ;
     RECT  2.16 25.785 127.44 26.055 ;
     RECT  2.16 26.325 127.44 26.595 ;
     RECT  2.16 26.865 127.44 27.135 ;
     RECT  2.16 27.405 127.44 27.675 ;
     RECT  2.16 27.945 127.44 28.215 ;
     RECT  2.16 28.485 127.44 28.755 ;
     RECT  2.16 29.025 127.44 29.295 ;
     RECT  2.16 29.565 127.44 29.835 ;
     RECT  2.16 30.105 127.44 30.375 ;
     RECT  2.16 30.645 127.44 30.915 ;
     RECT  2.16 31.185 127.44 31.455 ;
     RECT  2.16 31.725 127.44 31.995 ;
     RECT  2.16 32.265 127.44 32.535 ;
     RECT  2.16 32.805 127.44 33.075 ;
     RECT  2.16 33.345 127.44 33.615 ;
     RECT  2.16 33.885 127.44 34.155 ;
     RECT  2.16 34.425 127.44 34.695 ;
     RECT  2.16 34.965 127.44 35.235 ;
     RECT  2.16 35.505 127.44 35.775 ;
     RECT  2.16 36.045 127.44 36.315 ;
     RECT  2.16 36.585 127.44 36.855 ;
     RECT  2.16 37.125 127.44 37.395 ;
     RECT  2.16 37.665 127.44 37.935 ;
     RECT  2.16 38.205 127.44 38.475 ;
     RECT  2.16 38.745 127.44 39.015 ;
     RECT  2.16 39.285 127.44 39.555 ;
     RECT  2.16 39.825 127.44 40.095 ;
     RECT  2.16 40.365 127.44 40.635 ;
     RECT  2.16 40.905 127.44 41.175 ;
     RECT  2.16 41.445 127.44 41.715 ;
     RECT  2.16 41.985 127.44 42.255 ;
     RECT  2.16 42.525 127.44 42.795 ;
     RECT  2.16 43.065 127.44 43.335 ;
     RECT  2.16 43.605 127.44 43.875 ;
     RECT  2.16 44.145 127.44 44.415 ;
     RECT  2.16 44.685 127.44 44.955 ;
     RECT  2.16 45.225 127.44 45.495 ;
     RECT  2.16 45.765 127.44 46.035 ;
     RECT  2.16 46.305 127.44 46.575 ;
     RECT  2.16 46.845 127.44 47.115 ;
     RECT  2.16 47.385 127.44 47.655 ;
     RECT  2.16 47.925 127.44 48.195 ;
     RECT  2.16 48.465 127.44 48.735 ;
     RECT  2.16 49.005 127.44 49.275 ;
     RECT  2.16 49.545 127.44 49.815 ;
     RECT  2.16 50.085 127.44 50.355 ;
     RECT  2.16 50.625 127.44 50.895 ;
     RECT  2.16 51.165 127.44 51.435 ;
     RECT  2.16 51.705 127.44 51.975 ;
     RECT  2.16 52.245 127.44 52.515 ;
     RECT  2.16 52.785 127.44 53.055 ;
     RECT  2.16 53.325 127.44 53.595 ;
     RECT  2.16 53.865 127.44 54.135 ;
     RECT  2.16 54.405 127.44 54.675 ;
     RECT  2.16 54.945 127.44 55.215 ;
     RECT  2.16 55.485 127.44 55.755 ;
     RECT  2.16 56.025 127.44 56.295 ;
     RECT  2.16 56.565 127.44 56.835 ;
     RECT  2.16 57.105 127.44 57.375 ;
     RECT  2.16 57.645 127.44 57.915 ;
     RECT  2.16 58.185 127.44 58.455 ;
     RECT  2.16 58.725 127.44 58.995 ;
     RECT  2.16 59.265 127.44 59.535 ;
     RECT  2.16 59.805 127.44 60.075 ;
     RECT  2.16 60.345 127.44 60.615 ;
     RECT  2.16 60.885 127.44 61.155 ;
     RECT  2.16 61.425 127.44 61.695 ;
     RECT  2.16 61.965 127.44 62.235 ;
     RECT  2.16 62.505 127.44 62.775 ;
     RECT  2.16 63.045 127.44 63.315 ;
     RECT  2.16 63.585 127.44 63.855 ;
     RECT  2.16 64.125 127.44 64.395 ;
     RECT  2.16 64.665 127.44 64.935 ;
     RECT  2.16 65.205 127.44 65.475 ;
     RECT  2.16 65.745 127.44 66.015 ;
     RECT  2.16 66.285 127.44 66.555 ;
     RECT  2.16 66.825 127.44 67.095 ;
     RECT  2.16 67.365 127.44 67.635 ;
     RECT  2.16 67.905 127.44 68.175 ;
     RECT  2.16 68.445 127.44 68.715 ;
     RECT  2.16 68.985 127.44 69.255 ;
     RECT  2.16 69.525 127.44 69.795 ;
     RECT  2.16 70.065 127.44 70.335 ;
     RECT  2.16 70.605 127.44 70.875 ;
     RECT  2.16 71.145 127.44 71.415 ;
     RECT  2.16 71.685 127.44 71.955 ;
     RECT  2.16 72.225 127.44 72.495 ;
     RECT  2.16 72.765 127.44 73.035 ;
     RECT  2.16 73.305 127.44 73.575 ;
     RECT  2.16 73.845 127.44 74.115 ;
     RECT  2.16 74.385 127.44 74.655 ;
     RECT  2.16 74.925 127.44 75.195 ;
     RECT  2.16 75.465 127.44 75.735 ;
     RECT  2.16 76.005 127.44 76.275 ;
     RECT  2.16 76.545 127.44 76.815 ;
     RECT  2.16 77.085 127.44 77.355 ;
     RECT  2.16 77.625 127.44 77.895 ;
     RECT  2.16 78.165 127.44 78.435 ;
     RECT  2.16 78.705 127.44 78.975 ;
     RECT  2.16 79.245 127.44 79.515 ;
     RECT  2.16 79.785 127.44 80.055 ;
     RECT  2.16 80.325 127.44 80.595 ;
     RECT  2.16 80.865 127.44 81.135 ;
     RECT  2.16 81.405 127.44 81.675 ;
     RECT  2.16 81.945 127.44 82.215 ;
     RECT  2.16 82.485 127.44 82.755 ;
     RECT  2.16 83.025 127.44 83.295 ;
     RECT  2.16 83.565 127.44 83.835 ;
     RECT  2.16 84.105 127.44 84.24 ;
    LAYER RVTP ;
     RECT  2.16 2.295 127.44 2.565 ;
     RECT  2.16 2.835 127.44 3.105 ;
     RECT  2.16 3.375 127.44 3.645 ;
     RECT  2.16 3.915 127.44 4.185 ;
     RECT  2.16 4.455 127.44 4.725 ;
     RECT  2.16 4.995 127.44 5.265 ;
     RECT  2.16 5.535 127.44 5.805 ;
     RECT  2.16 6.075 127.44 6.345 ;
     RECT  2.16 6.615 127.44 6.885 ;
     RECT  2.16 7.155 127.44 7.425 ;
     RECT  2.16 7.695 127.44 7.965 ;
     RECT  2.16 8.235 127.44 8.505 ;
     RECT  2.16 8.775 127.44 9.045 ;
     RECT  2.16 9.315 127.44 9.585 ;
     RECT  2.16 9.855 127.44 10.125 ;
     RECT  2.16 10.395 127.44 10.665 ;
     RECT  2.16 10.935 127.44 11.205 ;
     RECT  2.16 11.475 127.44 11.745 ;
     RECT  2.16 12.015 127.44 12.285 ;
     RECT  2.16 12.555 127.44 12.825 ;
     RECT  2.16 13.095 127.44 13.365 ;
     RECT  2.16 13.635 127.44 13.905 ;
     RECT  2.16 14.175 127.44 14.445 ;
     RECT  2.16 14.715 127.44 14.985 ;
     RECT  2.16 15.255 127.44 15.525 ;
     RECT  2.16 15.795 127.44 16.065 ;
     RECT  2.16 16.335 127.44 16.605 ;
     RECT  2.16 16.875 127.44 17.145 ;
     RECT  2.16 17.415 127.44 17.685 ;
     RECT  2.16 17.955 127.44 18.225 ;
     RECT  2.16 18.495 127.44 18.765 ;
     RECT  2.16 19.035 127.44 19.305 ;
     RECT  2.16 19.575 127.44 19.845 ;
     RECT  2.16 20.115 127.44 20.385 ;
     RECT  2.16 20.655 127.44 20.925 ;
     RECT  2.16 21.195 127.44 21.465 ;
     RECT  2.16 21.735 127.44 22.005 ;
     RECT  2.16 22.275 127.44 22.545 ;
     RECT  2.16 22.815 127.44 23.085 ;
     RECT  2.16 23.355 127.44 23.625 ;
     RECT  2.16 23.895 127.44 24.165 ;
     RECT  2.16 24.435 127.44 24.705 ;
     RECT  2.16 24.975 127.44 25.245 ;
     RECT  2.16 25.515 127.44 25.785 ;
     RECT  2.16 26.055 127.44 26.325 ;
     RECT  2.16 26.595 127.44 26.865 ;
     RECT  2.16 27.135 127.44 27.405 ;
     RECT  2.16 27.675 127.44 27.945 ;
     RECT  2.16 28.215 127.44 28.485 ;
     RECT  2.16 28.755 127.44 29.025 ;
     RECT  2.16 29.295 127.44 29.565 ;
     RECT  2.16 29.835 127.44 30.105 ;
     RECT  2.16 30.375 127.44 30.645 ;
     RECT  2.16 30.915 127.44 31.185 ;
     RECT  2.16 31.455 127.44 31.725 ;
     RECT  2.16 31.995 127.44 32.265 ;
     RECT  2.16 32.535 127.44 32.805 ;
     RECT  2.16 33.075 127.44 33.345 ;
     RECT  2.16 33.615 127.44 33.885 ;
     RECT  2.16 34.155 127.44 34.425 ;
     RECT  2.16 34.695 127.44 34.965 ;
     RECT  2.16 35.235 127.44 35.505 ;
     RECT  2.16 35.775 127.44 36.045 ;
     RECT  2.16 36.315 127.44 36.585 ;
     RECT  2.16 36.855 127.44 37.125 ;
     RECT  2.16 37.395 127.44 37.665 ;
     RECT  2.16 37.935 127.44 38.205 ;
     RECT  2.16 38.475 127.44 38.745 ;
     RECT  2.16 39.015 127.44 39.285 ;
     RECT  2.16 39.555 127.44 39.825 ;
     RECT  2.16 40.095 127.44 40.365 ;
     RECT  2.16 40.635 127.44 40.905 ;
     RECT  2.16 41.175 127.44 41.445 ;
     RECT  2.16 41.715 127.44 41.985 ;
     RECT  2.16 42.255 127.44 42.525 ;
     RECT  2.16 42.795 127.44 43.065 ;
     RECT  2.16 43.335 127.44 43.605 ;
     RECT  2.16 43.875 127.44 44.145 ;
     RECT  2.16 44.415 127.44 44.685 ;
     RECT  2.16 44.955 127.44 45.225 ;
     RECT  2.16 45.495 127.44 45.765 ;
     RECT  2.16 46.035 127.44 46.305 ;
     RECT  2.16 46.575 127.44 46.845 ;
     RECT  2.16 47.115 127.44 47.385 ;
     RECT  2.16 47.655 127.44 47.925 ;
     RECT  2.16 48.195 127.44 48.465 ;
     RECT  2.16 48.735 127.44 49.005 ;
     RECT  2.16 49.275 127.44 49.545 ;
     RECT  2.16 49.815 127.44 50.085 ;
     RECT  2.16 50.355 127.44 50.625 ;
     RECT  2.16 50.895 127.44 51.165 ;
     RECT  2.16 51.435 127.44 51.705 ;
     RECT  2.16 51.975 127.44 52.245 ;
     RECT  2.16 52.515 127.44 52.785 ;
     RECT  2.16 53.055 127.44 53.325 ;
     RECT  2.16 53.595 127.44 53.865 ;
     RECT  2.16 54.135 127.44 54.405 ;
     RECT  2.16 54.675 127.44 54.945 ;
     RECT  2.16 55.215 127.44 55.485 ;
     RECT  2.16 55.755 127.44 56.025 ;
     RECT  2.16 56.295 127.44 56.565 ;
     RECT  2.16 56.835 127.44 57.105 ;
     RECT  2.16 57.375 127.44 57.645 ;
     RECT  2.16 57.915 127.44 58.185 ;
     RECT  2.16 58.455 127.44 58.725 ;
     RECT  2.16 58.995 127.44 59.265 ;
     RECT  2.16 59.535 127.44 59.805 ;
     RECT  2.16 60.075 127.44 60.345 ;
     RECT  2.16 60.615 127.44 60.885 ;
     RECT  2.16 61.155 127.44 61.425 ;
     RECT  2.16 61.695 127.44 61.965 ;
     RECT  2.16 62.235 127.44 62.505 ;
     RECT  2.16 62.775 127.44 63.045 ;
     RECT  2.16 63.315 127.44 63.585 ;
     RECT  2.16 63.855 127.44 64.125 ;
     RECT  2.16 64.395 127.44 64.665 ;
     RECT  2.16 64.935 127.44 65.205 ;
     RECT  2.16 65.475 127.44 65.745 ;
     RECT  2.16 66.015 127.44 66.285 ;
     RECT  2.16 66.555 127.44 66.825 ;
     RECT  2.16 67.095 127.44 67.365 ;
     RECT  2.16 67.635 127.44 67.905 ;
     RECT  2.16 68.175 127.44 68.445 ;
     RECT  2.16 68.715 127.44 68.985 ;
     RECT  2.16 69.255 127.44 69.525 ;
     RECT  2.16 69.795 127.44 70.065 ;
     RECT  2.16 70.335 127.44 70.605 ;
     RECT  2.16 70.875 127.44 71.145 ;
     RECT  2.16 71.415 127.44 71.685 ;
     RECT  2.16 71.955 127.44 72.225 ;
     RECT  2.16 72.495 127.44 72.765 ;
     RECT  2.16 73.035 127.44 73.305 ;
     RECT  2.16 73.575 127.44 73.845 ;
     RECT  2.16 74.115 127.44 74.385 ;
     RECT  2.16 74.655 127.44 74.925 ;
     RECT  2.16 75.195 127.44 75.465 ;
     RECT  2.16 75.735 127.44 76.005 ;
     RECT  2.16 76.275 127.44 76.545 ;
     RECT  2.16 76.815 127.44 77.085 ;
     RECT  2.16 77.355 127.44 77.625 ;
     RECT  2.16 77.895 127.44 78.165 ;
     RECT  2.16 78.435 127.44 78.705 ;
     RECT  2.16 78.975 127.44 79.245 ;
     RECT  2.16 79.515 127.44 79.785 ;
     RECT  2.16 80.055 127.44 80.325 ;
     RECT  2.16 80.595 127.44 80.865 ;
     RECT  2.16 81.135 127.44 81.405 ;
     RECT  2.16 81.675 127.44 81.945 ;
     RECT  2.16 82.215 127.44 82.485 ;
     RECT  2.16 82.755 127.44 83.025 ;
     RECT  2.16 83.295 127.44 83.565 ;
     RECT  2.16 83.835 127.44 84.105 ;
    LAYER M1 ;
     RECT  2.16 2.151 127.44 84.249 ;
    LAYER M2 ;
     RECT  1.399 82.8 2.16 82.818 ;
     RECT  2.16 2.151 18.139 84.249 ;
     RECT  18.139 2.151 40.819 84.942 ;
     RECT  40.819 2.151 109.607 85.554 ;
     RECT  109.607 2.151 112.343 85.518 ;
     RECT  112.343 2.151 117.851 84.978 ;
     RECT  117.851 2.151 118.427 84.402 ;
     RECT  118.427 2.151 118.615 84.249 ;
     RECT  118.615 2.034 122.243 84.249 ;
     RECT  122.243 2.106 125.563 84.249 ;
     RECT  125.563 2.034 127.44 84.249 ;
     RECT  127.44 17.316 127.679 19.134 ;
     RECT  127.44 46.926 127.679 59.796 ;
     RECT  127.44 60.786 127.679 65.304 ;
     RECT  127.44 78.876 127.679 79.614 ;
     RECT  127.679 50.256 127.715 59.796 ;
     RECT  127.44 81.612 127.715 82.278 ;
     RECT  127.715 81.612 127.967 81.63 ;
     RECT  127.44 20.016 128.147 33.264 ;
     RECT  127.715 54.846 128.219 59.634 ;
     RECT  127.44 3.348 128.255 16.524 ;
     RECT  127.679 17.316 128.255 18.954 ;
     RECT  128.147 20.016 128.255 25.434 ;
     RECT  128.147 26.226 128.255 33.264 ;
     RECT  127.44 34.056 128.255 34.884 ;
     RECT  127.44 35.676 128.255 43.326 ;
     RECT  127.679 47.016 128.255 49.464 ;
     RECT  128.219 54.846 128.255 56.898 ;
     RECT  128.219 57.996 128.255 59.634 ;
     RECT  127.679 60.786 128.255 63.234 ;
     RECT  127.44 66.096 128.255 72.864 ;
     RECT  128.255 3.348 128.291 13.662 ;
     RECT  128.255 14.616 128.291 16.524 ;
     RECT  128.255 47.016 128.291 48.996 ;
     RECT  128.255 58.086 128.291 58.554 ;
     RECT  128.255 62.316 128.291 62.604 ;
     RECT  127.679 64.026 128.291 65.304 ;
     RECT  128.255 67.446 128.291 72.414 ;
     RECT  127.44 84.15 128.291 84.168 ;
     RECT  127.715 50.256 128.363 54.054 ;
     RECT  128.291 62.316 128.363 62.334 ;
     RECT  128.255 20.016 128.795 22.464 ;
     RECT  128.255 28.836 128.795 32.724 ;
     RECT  128.255 34.056 128.795 34.344 ;
     RECT  128.255 61.164 128.795 61.344 ;
     RECT  128.291 64.026 128.795 64.89 ;
     RECT  127.44 74.016 128.795 75.762 ;
     RECT  127.44 2.034 128.831 2.394 ;
     RECT  128.291 3.348 128.831 9.774 ;
     RECT  128.291 10.944 128.831 10.962 ;
     RECT  128.291 11.916 128.831 13.662 ;
     RECT  128.291 14.616 128.831 16.434 ;
     RECT  128.255 17.316 128.831 17.874 ;
     RECT  128.255 18.738 128.831 18.954 ;
     RECT  128.795 20.016 128.831 21.654 ;
     RECT  128.795 22.446 128.831 22.464 ;
     RECT  128.255 23.328 128.831 24.624 ;
     RECT  128.255 25.416 128.831 25.434 ;
     RECT  128.255 26.226 128.831 27.324 ;
     RECT  128.795 28.836 128.831 29.556 ;
     RECT  128.795 30.816 128.831 31.554 ;
     RECT  128.795 32.436 128.831 32.724 ;
     RECT  128.795 34.056 128.831 34.074 ;
     RECT  128.255 35.676 128.831 39.006 ;
     RECT  128.255 39.996 128.831 43.326 ;
     RECT  127.44 44.316 128.831 46.098 ;
     RECT  128.291 47.016 128.831 47.034 ;
     RECT  128.291 48.096 128.831 48.996 ;
     RECT  128.363 50.256 128.831 50.814 ;
     RECT  128.363 51.786 128.831 54.054 ;
     RECT  128.255 54.846 128.831 54.864 ;
     RECT  128.255 55.836 128.831 55.854 ;
     RECT  128.255 56.646 128.831 56.898 ;
     RECT  128.291 58.086 128.831 58.104 ;
     RECT  128.255 59.616 128.831 59.634 ;
     RECT  128.795 61.326 128.831 61.344 ;
     RECT  128.795 64.296 128.831 64.89 ;
     RECT  128.255 66.096 128.831 66.474 ;
     RECT  128.291 67.446 128.831 68.904 ;
     RECT  128.291 69.966 128.831 71.406 ;
     RECT  128.291 72.396 128.831 72.414 ;
     RECT  128.795 74.016 128.831 74.034 ;
     RECT  128.795 74.97 128.831 75.762 ;
     RECT  127.679 78.876 128.831 78.894 ;
     RECT  128.831 18.936 128.867 18.954 ;
     RECT  128.831 27.306 128.867 27.324 ;
     RECT  128.831 40.986 128.867 41.004 ;
     RECT  128.831 51.786 128.867 51.804 ;
     RECT  128.831 56.646 128.867 56.664 ;
     RECT  128.831 67.446 128.867 67.464 ;
     RECT  128.831 74.97 128.867 74.988 ;
     RECT  128.831 3.348 129.443 4.212 ;
     RECT  129.443 3.348 129.479 3.708 ;
     RECT  129.479 3.348 129.515 3.366 ;
     RECT  128.831 5.346 129.515 5.364 ;
     RECT  128.831 9.666 129.515 9.684 ;
     RECT  128.831 12.456 129.515 12.474 ;
     RECT  128.831 13.644 129.515 13.662 ;
     RECT  128.831 21.636 129.515 21.654 ;
     RECT  128.831 23.328 129.515 23.346 ;
     RECT  128.831 31.428 129.515 31.446 ;
     RECT  128.831 37.476 129.515 38.196 ;
     RECT  128.831 44.892 129.515 44.91 ;
     RECT  128.831 52.992 129.515 53.01 ;
     RECT  128.831 54.036 129.515 54.054 ;
     RECT  128.831 66.096 129.515 66.114 ;
     RECT  128.831 68.886 129.515 68.904 ;
     RECT  127.44 76.896 129.515 76.914 ;
     RECT  127.44 80.676 129.515 80.694 ;
    LAYER M3 ;
     RECT  127.296 0.811 127.314 1.147 ;
     RECT  127.152 1.147 127.314 1.483 ;
     RECT  128.232 0.139 128.25 1.483 ;
     RECT  127.152 1.483 128.25 1.819 ;
     RECT  125.964 0.475 125.982 2.029 ;
     RECT  122.22 2.029 122.238 2.101 ;
     RECT  125.568 2.029 125.982 2.101 ;
     RECT  121.68 2.101 122.238 2.143 ;
     RECT  125.568 2.101 126.306 2.143 ;
     RECT  127.152 1.819 128.826 2.143 ;
     RECT  125.568 2.143 128.826 2.191 ;
     RECT  118.62 2.029 118.638 2.219 ;
     RECT  125.208 2.191 128.826 2.219 ;
     RECT  105.015 2.143 105.105 2.227 ;
     RECT  123.048 2.101 123.21 2.291 ;
     RECT  121.215 2.143 122.238 2.335 ;
     RECT  128.808 2.219 128.826 2.399 ;
     RECT  2.415 2.143 2.505 2.413 ;
     RECT  7.815 2.143 7.905 2.413 ;
     RECT  13.215 2.143 13.305 2.413 ;
     RECT  18.615 2.143 18.705 2.413 ;
     RECT  24.015 2.143 24.105 2.413 ;
     RECT  29.415 2.143 29.505 2.413 ;
     RECT  34.815 2.143 34.905 2.413 ;
     RECT  40.215 2.143 40.305 2.413 ;
     RECT  45.615 2.143 45.705 2.413 ;
     RECT  51.015 2.143 51.105 2.413 ;
     RECT  56.415 2.143 56.505 2.413 ;
     RECT  61.815 2.143 61.905 2.413 ;
     RECT  67.215 2.143 67.305 2.413 ;
     RECT  72.615 2.143 72.705 2.413 ;
     RECT  78.015 2.143 78.105 2.413 ;
     RECT  83.415 2.143 83.505 2.413 ;
     RECT  88.815 2.143 88.905 2.413 ;
     RECT  94.215 2.143 94.305 2.413 ;
     RECT  99.615 2.143 99.705 2.413 ;
     RECT  104.76 2.227 105.105 2.413 ;
     RECT  110.415 2.143 110.505 2.413 ;
     RECT  115.815 2.143 115.905 2.413 ;
     RECT  120.528 2.335 122.238 2.533 ;
     RECT  94.215 2.413 94.497 2.569 ;
     RECT  124.236 2.227 124.254 2.605 ;
     RECT  125.208 2.219 127.674 2.605 ;
     RECT  123.3 2.347 123.318 2.641 ;
     RECT  120.528 2.533 122.562 2.759 ;
     RECT  123.3 2.641 123.426 2.767 ;
     RECT  124.236 2.605 127.674 2.767 ;
     RECT  120.528 2.759 122.094 2.795 ;
     RECT  115.815 2.413 116.097 2.803 ;
     RECT  118.584 2.533 118.602 2.831 ;
     RECT  129.456 2.491 129.51 3.211 ;
     RECT  123.3 2.767 127.674 3.299 ;
     RECT  129.42 3.211 129.51 3.371 ;
     RECT  123.3 3.299 123.75 3.403 ;
     RECT  122.904 3.403 123.75 3.541 ;
     RECT  124.632 3.299 127.674 3.547 ;
     RECT  122.544 3.541 123.75 3.713 ;
     RECT  129.42 3.371 129.474 3.713 ;
     RECT  124.632 3.547 128.25 3.839 ;
     RECT  128.196 3.839 128.25 3.883 ;
     RECT  129.42 3.713 129.438 3.883 ;
     RECT  118.98 3.685 118.998 4.081 ;
     RECT  121.215 2.795 121.497 4.117 ;
     RECT  118.62 4.081 118.998 4.217 ;
     RECT  94.215 2.569 94.914 4.225 ;
     RECT  122.652 3.713 123.75 4.225 ;
     RECT  121.215 4.117 121.878 4.349 ;
     RECT  118.98 4.217 118.998 4.387 ;
     RECT  122.652 4.225 123.822 4.541 ;
     RECT  128.196 3.883 129.438 4.555 ;
     RECT  122.652 4.541 123.174 4.559 ;
     RECT  122.652 4.559 122.922 4.649 ;
     RECT  124.632 3.839 127.134 4.685 ;
     RECT  122.652 4.649 122.85 4.801 ;
     RECT  124.632 4.685 125.118 4.801 ;
     RECT  125.892 4.685 127.134 4.801 ;
     RECT  125.892 4.801 127.17 4.891 ;
     RECT  128.196 4.555 129.51 4.891 ;
     RECT  125.892 4.891 129.51 5.099 ;
     RECT  128.196 5.099 129.51 5.189 ;
     RECT  125.892 5.099 127.17 5.225 ;
     RECT  125.892 5.225 126.99 5.297 ;
     RECT  121.215 4.349 121.497 5.341 ;
     RECT  122.4 4.801 122.85 5.341 ;
     RECT  128.232 5.189 129.51 5.369 ;
     RECT  118.98 4.387 119.142 5.467 ;
     RECT  125.892 5.297 126.954 5.495 ;
     RECT  123.696 5.467 123.714 5.729 ;
     RECT  128.232 5.369 128.826 5.729 ;
     RECT  118.26 5.467 119.142 5.971 ;
     RECT  125.964 5.495 126.954 6.115 ;
     RECT  121.215 5.341 122.85 6.151 ;
     RECT  121.215 6.151 123.282 6.269 ;
     RECT  121.215 6.269 123.138 6.275 ;
     RECT  119.988 5.161 120.006 6.547 ;
     RECT  121.215 6.275 122.85 6.547 ;
     RECT  125.964 6.115 127.062 6.571 ;
     RECT  119.988 6.547 122.85 6.605 ;
     RECT  125.964 6.571 127.674 6.647 ;
     RECT  124.524 4.801 125.118 6.691 ;
     RECT  125.964 6.647 127.062 6.691 ;
     RECT  121.215 6.605 122.85 6.809 ;
     RECT  124.524 6.691 127.062 6.809 ;
     RECT  124.524 6.809 126.897 6.917 ;
     RECT  104.76 2.413 105.297 7.231 ;
     RECT  106.272 4.189 106.29 7.231 ;
     RECT  128.808 5.729 128.826 7.579 ;
     RECT  122.364 6.809 122.85 7.627 ;
     RECT  122.364 7.627 122.958 7.771 ;
     RECT  125.964 6.917 126.897 7.771 ;
     RECT  128.232 7.579 128.826 7.799 ;
     RECT  121.215 6.809 121.497 7.861 ;
     RECT  122.364 7.771 123.678 7.889 ;
     RECT  125.964 7.771 126.99 8.005 ;
     RECT  125.964 8.005 127.062 8.275 ;
     RECT  117.684 5.971 119.142 8.311 ;
     RECT  119.988 6.605 120.006 8.311 ;
     RECT  125.964 8.275 127.098 8.311 ;
     RECT  125.856 8.311 127.71 8.429 ;
     RECT  124.524 6.917 125.118 8.491 ;
     RECT  124.272 8.491 125.118 8.699 ;
     RECT  126.144 8.429 127.71 8.957 ;
     RECT  122.364 7.889 122.886 9.113 ;
     RECT  117.684 8.311 120.006 9.247 ;
     RECT  120.816 7.861 121.497 9.247 ;
     RECT  124.524 8.699 125.118 9.391 ;
     RECT  126.144 8.957 127.098 9.391 ;
     RECT  117.684 9.247 121.497 9.481 ;
     RECT  122.364 9.113 122.598 9.481 ;
     RECT  124.524 9.391 127.098 9.509 ;
     RECT  128.808 7.799 128.826 9.661 ;
     RECT  103.932 2.731 103.95 9.751 ;
     RECT  128.808 9.661 129.51 9.779 ;
     RECT  125.928 9.509 127.098 9.895 ;
     RECT  129.492 9.779 129.51 9.965 ;
     RECT  125.928 9.895 127.17 10.049 ;
     RECT  123.372 10.315 123.39 10.355 ;
     RECT  124.524 9.509 125.118 10.471 ;
     RECT  125.928 10.049 127.134 10.471 ;
     RECT  128.232 10.267 128.286 10.589 ;
     RECT  117.684 9.481 122.598 10.795 ;
     RECT  117.684 10.795 122.922 10.829 ;
     RECT  117.684 10.829 121.497 10.831 ;
     RECT  128.268 10.589 128.286 10.939 ;
     RECT  124.524 10.471 127.134 10.975 ;
     RECT  124.524 10.975 127.17 11.209 ;
     RECT  110.415 2.413 110.697 11.272 ;
     RECT  110.304 11.272 110.697 11.309 ;
     RECT  100.656 3.001 100.674 11.371 ;
     RECT  122.292 10.829 122.922 11.549 ;
     RECT  124.2 11.209 127.17 11.669 ;
     RECT  128.268 10.939 128.826 11.939 ;
     RECT  122.292 11.549 122.598 11.975 ;
     RECT  124.2 11.669 126.897 12.091 ;
     RECT  117.324 10.831 121.497 12.139 ;
     RECT  117.324 12.139 121.626 12.209 ;
     RECT  123.516 12.091 126.897 12.209 ;
     RECT  115.815 2.803 116.55 12.289 ;
     RECT  117.324 12.209 121.497 12.289 ;
     RECT  124.164 12.209 126.897 12.557 ;
     RECT  124.272 12.557 126.897 12.595 ;
     RECT  129.492 12.451 129.51 12.653 ;
     RECT  128.232 11.947 128.25 12.955 ;
     RECT  128.232 12.955 128.826 13.019 ;
     RECT  122.364 11.975 122.598 13.051 ;
     RECT  122.364 13.051 123.21 13.091 ;
     RECT  124.272 12.595 126.99 13.135 ;
     RECT  113.148 12.487 113.166 13.261 ;
     RECT  128.232 13.019 128.25 13.325 ;
     RECT  124.272 13.135 127.026 13.639 ;
     RECT  129.492 13.639 129.51 13.709 ;
     RECT  124.272 13.639 127.134 13.829 ;
     RECT  124.272 13.829 126.954 13.981 ;
     RECT  109.62 13.027 109.638 14.071 ;
     RECT  122.364 13.091 122.634 14.203 ;
     RECT  124.02 13.981 126.954 14.243 ;
     RECT  128.808 14.011 128.826 14.341 ;
     RECT  122.364 14.203 123.246 14.369 ;
     RECT  112.536 13.261 113.166 14.611 ;
     RECT  124.524 14.243 126.954 14.755 ;
     RECT  124.524 14.755 127.134 14.909 ;
     RECT  128.232 14.341 128.826 14.981 ;
     RECT  124.524 14.909 126.897 15.295 ;
     RECT  124.236 15.295 126.897 15.341 ;
     RECT  124.524 15.341 126.897 15.835 ;
     RECT  123.48 15.835 123.498 15.871 ;
     RECT  115.815 12.289 121.497 15.931 ;
     RECT  124.524 15.835 127.026 15.961 ;
     RECT  123.48 15.871 123.642 15.965 ;
     RECT  124.524 15.961 127.098 16.027 ;
     RECT  124.524 16.027 127.674 16.231 ;
     RECT  124.452 16.231 127.674 16.367 ;
     RECT  123.624 15.965 123.642 16.375 ;
     RECT  124.452 16.367 127.098 16.375 ;
     RECT  128.808 14.981 128.826 16.501 ;
     RECT  115.815 15.931 121.59 16.541 ;
     RECT  123.624 16.375 127.098 16.565 ;
     RECT  115.815 16.541 121.497 16.835 ;
     RECT  122.364 14.369 122.598 17.083 ;
     RECT  123.624 16.565 125.118 17.117 ;
     RECT  122.364 17.083 122.814 17.311 ;
     RECT  123.624 17.117 123.786 17.311 ;
     RECT  128.268 16.501 128.826 17.371 ;
     RECT  126.072 16.565 127.098 17.455 ;
     RECT  124.524 17.117 125.118 17.491 ;
     RECT  125.892 17.455 127.098 17.491 ;
     RECT  115.815 16.835 116.586 17.581 ;
     RECT  117.324 16.835 121.497 17.581 ;
     RECT  122.364 17.311 123.786 17.609 ;
     RECT  124.524 17.491 127.098 17.609 ;
     RECT  128.232 17.371 128.826 17.879 ;
     RECT  123.624 17.609 123.786 17.887 ;
     RECT  124.524 17.609 127.062 17.887 ;
     RECT  103.428 9.751 103.95 17.923 ;
     RECT  104.76 7.231 106.29 17.923 ;
     RECT  123.624 17.887 127.062 18.149 ;
     RECT  123.624 18.149 125.514 18.185 ;
     RECT  128.232 17.879 128.25 18.599 ;
     RECT  115.815 17.581 121.497 18.667 ;
     RECT  122.364 17.609 122.598 18.667 ;
     RECT  115.815 18.667 122.598 18.697 ;
     RECT  126.252 18.149 127.062 18.769 ;
     RECT  128.808 18.715 128.826 18.931 ;
     RECT  115.596 18.697 122.598 18.995 ;
     RECT  126.252 18.769 127.17 19.051 ;
     RECT  122.364 18.995 122.598 19.111 ;
     RECT  126.252 19.051 127.674 19.139 ;
     RECT  126.252 19.139 127.17 19.229 ;
     RECT  126.252 19.229 127.134 19.345 ;
     RECT  123.624 18.185 125.118 19.381 ;
     RECT  126.072 19.345 127.134 19.381 ;
     RECT  122.364 19.111 122.706 19.387 ;
     RECT  123.624 19.381 127.134 19.387 ;
     RECT  122.364 19.387 127.134 19.535 ;
     RECT  128.808 18.931 128.862 19.757 ;
     RECT  126 19.535 127.134 19.769 ;
     RECT  128.808 19.757 128.826 20.059 ;
     RECT  115.596 18.995 121.497 20.281 ;
     RECT  122.364 19.535 125.226 20.281 ;
     RECT  126 19.769 126.897 20.281 ;
     RECT  128.772 20.059 128.826 20.389 ;
     RECT  128.232 20.389 128.826 20.429 ;
     RECT  115.596 20.281 126.897 20.695 ;
     RECT  115.596 20.695 126.99 20.849 ;
     RECT  128.808 20.429 128.826 21.119 ;
     RECT  128.232 21.361 128.25 21.437 ;
     RECT  129.492 21.631 129.51 21.773 ;
     RECT  126.216 20.849 126.99 21.775 ;
     RECT  115.596 20.849 125.406 21.811 ;
     RECT  126.216 21.775 127.062 21.811 ;
     RECT  97.956 11.911 97.974 22.009 ;
     RECT  115.596 21.811 127.062 22.207 ;
     RECT  100.656 11.371 101.214 22.441 ;
     RECT  102.276 8.941 102.294 22.441 ;
     RECT  128.772 22.075 128.826 22.469 ;
     RECT  115.596 22.207 127.242 23.009 ;
     RECT  128.232 22.747 128.25 23.083 ;
     RECT  114.84 22.711 114.858 23.251 ;
     RECT  115.596 23.009 127.206 23.251 ;
     RECT  129.492 23.323 129.51 23.453 ;
     RECT  114.84 23.251 127.206 23.549 ;
     RECT  114.84 23.549 127.134 23.585 ;
     RECT  128.196 23.083 128.25 23.729 ;
     RECT  111.42 20.821 111.438 23.827 ;
     RECT  100.656 22.441 102.294 23.863 ;
     RECT  125.964 23.585 127.134 24.089 ;
     RECT  97.74 22.009 97.974 24.331 ;
     RECT  100.656 23.863 102.33 24.403 ;
     RECT  114.84 23.585 125.118 24.511 ;
     RECT  125.964 24.089 127.098 24.511 ;
     RECT  97.128 24.331 97.974 24.781 ;
     RECT  114.84 24.511 127.098 24.871 ;
     RECT  114.552 24.871 127.098 24.899 ;
     RECT  128.808 23.755 128.826 25.141 ;
     RECT  128.232 25.141 128.826 25.483 ;
     RECT  125.892 24.899 127.098 25.555 ;
     RECT  125.892 25.555 127.134 25.709 ;
     RECT  97.02 24.781 97.974 25.789 ;
     RECT  98.712 16.807 98.73 25.789 ;
     RECT  114.552 24.899 125.118 25.861 ;
     RECT  125.892 25.709 126.897 25.861 ;
     RECT  128.124 25.483 128.826 25.889 ;
     RECT  111.42 23.827 111.51 26.563 ;
     RECT  112.536 14.611 113.706 26.563 ;
     RECT  114.552 25.861 126.897 26.825 ;
     RECT  128.772 25.889 128.826 26.827 ;
     RECT  109.116 14.071 109.638 27.031 ;
     RECT  110.415 11.309 110.697 27.031 ;
     RECT  128.196 26.827 128.826 27.167 ;
     RECT  126.54 26.825 126.897 27.175 ;
     RECT  128.232 27.167 128.826 27.301 ;
     RECT  126.54 27.175 126.99 27.337 ;
     RECT  107.424 14.917 107.442 27.643 ;
     RECT  114.552 26.825 125.766 27.751 ;
     RECT  126.54 27.337 127.062 27.751 ;
     RECT  128.232 27.301 128.862 27.869 ;
     RECT  128.232 27.869 128.25 28.507 ;
     RECT  103.428 17.923 106.29 28.723 ;
     RECT  128.196 28.507 128.25 28.787 ;
     RECT  114.552 27.751 127.062 28.795 ;
     RECT  114.552 28.795 127.098 29.219 ;
     RECT  114.552 29.219 125.334 29.255 ;
     RECT  114.552 29.255 125.19 29.489 ;
     RECT  126.144 29.219 127.098 29.605 ;
     RECT  128.808 28.831 128.826 29.851 ;
     RECT  128.34 29.851 128.826 29.939 ;
     RECT  126.144 29.605 127.242 30.029 ;
     RECT  126.144 30.029 127.17 30.181 ;
     RECT  114.552 29.489 125.118 30.271 ;
     RECT  126.072 30.181 127.17 30.271 ;
     RECT  114.552 30.271 127.17 30.299 ;
     RECT  114.552 30.299 127.098 30.335 ;
     RECT  107.424 27.643 107.946 30.811 ;
     RECT  128.772 29.939 128.826 30.859 ;
     RECT  128.232 30.859 128.826 31.109 ;
     RECT  114.552 30.335 126.897 31.181 ;
     RECT  128.808 31.109 128.826 31.195 ;
     RECT  2.415 2.413 2.697 31.261 ;
     RECT  100.656 24.403 102.654 31.423 ;
     RECT  128.808 31.195 129.51 31.451 ;
     RECT  125.928 31.181 126.897 31.495 ;
     RECT  4.716 31.495 4.734 31.531 ;
     RECT  125.928 31.495 127.098 31.649 ;
     RECT  2.415 31.261 3.618 31.765 ;
     RECT  2.415 31.765 3.762 31.771 ;
     RECT  4.716 31.531 4.914 31.801 ;
     RECT  2.376 31.771 3.762 31.891 ;
     RECT  4.716 31.801 4.95 31.891 ;
     RECT  128.808 31.451 128.826 31.891 ;
     RECT  2.376 31.891 4.95 31.955 ;
     RECT  114.552 31.181 125.118 32.071 ;
     RECT  125.928 31.649 127.026 32.071 ;
     RECT  3.492 31.955 4.95 32.197 ;
     RECT  3.492 32.197 5.202 32.369 ;
     RECT  2.376 31.955 2.754 32.395 ;
     RECT  128.772 31.891 128.826 32.729 ;
     RECT  2.304 32.395 2.754 32.765 ;
     RECT  2.415 32.765 2.754 32.845 ;
     RECT  3.492 32.369 4.698 32.845 ;
     RECT  114.552 32.071 127.026 32.845 ;
     RECT  114.552 32.845 127.062 32.999 ;
     RECT  2.415 32.845 4.698 33.151 ;
     RECT  99.615 2.413 99.897 33.241 ;
     RECT  100.62 31.423 102.654 33.241 ;
     RECT  128.232 32.872 128.25 33.269 ;
     RECT  94.215 4.225 94.986 33.313 ;
     RECT  2.415 33.151 4.806 33.449 ;
     RECT  109.116 27.031 110.697 33.511 ;
     RECT  111.42 26.563 113.706 33.511 ;
     RECT  2.415 33.449 3.438 33.539 ;
     RECT  2.415 33.539 3.258 33.575 ;
     RECT  86.904 31.891 86.922 33.781 ;
     RECT  109.116 33.511 113.706 33.781 ;
     RECT  114.552 32.999 126.897 33.781 ;
     RECT  2.415 33.575 3.078 33.809 ;
     RECT  2.415 33.809 2.97 33.845 ;
     RECT  4.572 33.449 4.806 33.845 ;
     RECT  128.772 33.547 128.79 33.883 ;
     RECT  128.772 33.883 128.826 34.079 ;
     RECT  107.424 30.811 108.342 34.087 ;
     RECT  109.116 33.781 126.897 34.087 ;
     RECT  128.772 34.079 128.79 34.219 ;
     RECT  128.232 34.219 128.79 34.349 ;
     RECT  97.02 25.789 98.73 34.465 ;
     RECT  99.615 33.241 102.654 34.465 ;
     RECT  107.424 34.087 126.897 34.493 ;
     RECT  111.42 34.493 126.897 34.655 ;
     RECT  26.748 34.888 26.766 34.925 ;
     RECT  126.216 34.655 126.897 35.005 ;
     RECT  128.232 34.349 128.25 35.275 ;
     RECT  126.216 35.005 127.134 35.311 ;
     RECT  27.072 35.041 27.09 35.357 ;
     RECT  111.42 34.655 125.226 35.581 ;
     RECT  128.088 35.275 128.25 35.611 ;
     RECT  111.42 35.581 125.442 35.671 ;
     RECT  126.216 35.311 127.242 35.671 ;
     RECT  111.42 35.671 127.242 35.981 ;
     RECT  128.088 35.611 128.826 36.149 ;
     RECT  128.232 36.149 128.826 36.989 ;
     RECT  111.42 35.981 127.134 37.049 ;
     RECT  128.196 37.291 128.214 37.963 ;
     RECT  129.492 37.471 129.51 37.963 ;
     RECT  128.196 37.963 129.51 37.967 ;
     RECT  111.42 37.049 125.442 38.011 ;
     RECT  126.216 37.049 127.062 38.011 ;
     RECT  107.424 34.493 110.697 38.443 ;
     RECT  111.42 38.011 127.062 38.551 ;
     RECT  128.808 37.967 129.51 38.669 ;
     RECT  111.42 38.551 127.242 38.713 ;
     RECT  111.42 38.713 127.314 39.209 ;
     RECT  111.42 39.209 127.098 39.281 ;
     RECT  128.808 38.669 128.826 39.307 ;
     RECT  126.216 39.281 127.098 39.479 ;
     RECT  128.232 39.307 128.826 39.979 ;
     RECT  111.42 39.281 125.442 40.019 ;
     RECT  111.42 40.019 125.262 40.055 ;
     RECT  126.216 39.479 126.897 40.405 ;
     RECT  128.196 39.979 128.826 40.469 ;
     RECT  126.216 40.405 126.99 40.675 ;
     RECT  126.216 40.675 127.098 40.801 ;
     RECT  128.808 40.469 128.826 40.981 ;
     RECT  128.808 40.981 128.862 41.357 ;
     RECT  125.928 40.801 127.098 41.485 ;
     RECT  111.42 40.055 125.19 41.521 ;
     RECT  125.928 41.485 127.134 41.521 ;
     RECT  111.42 41.521 127.134 41.909 ;
     RECT  128.808 41.357 128.826 42.331 ;
     RECT  128.232 42.331 128.826 42.449 ;
     RECT  111.42 41.909 126.954 42.485 ;
     RECT  126.504 42.485 126.954 42.727 ;
     RECT  111.42 42.485 125.658 42.989 ;
     RECT  126.504 42.727 127.098 43.003 ;
     RECT  126.504 43.003 127.674 43.169 ;
     RECT  64.656 32.197 64.674 43.339 ;
     RECT  126.504 43.169 127.242 43.375 ;
     RECT  64.008 43.339 64.674 43.529 ;
     RECT  125.856 43.375 127.242 43.565 ;
     RECT  64.368 43.529 64.674 43.901 ;
     RECT  90.936 43.771 90.954 44.041 ;
     RECT  125.964 43.565 127.242 44.069 ;
     RECT  128.808 42.449 128.826 44.339 ;
     RECT  111.42 42.989 125.118 44.491 ;
     RECT  125.964 44.069 126.897 44.491 ;
     RECT  96.192 2.191 96.21 44.581 ;
     RECT  128.232 44.347 128.25 44.609 ;
     RECT  111.42 44.491 126.897 44.645 ;
     RECT  127.656 44.683 127.674 44.987 ;
     RECT  125.964 44.645 126.897 44.995 ;
     RECT  129.492 44.887 129.51 45.053 ;
     RECT  125.964 44.995 127.134 45.149 ;
     RECT  111.42 44.645 125.118 45.571 ;
     RECT  111.42 45.571 125.154 45.689 ;
     RECT  94.215 33.313 95.094 45.967 ;
     RECT  125.964 45.149 127.026 46.075 ;
     RECT  111.42 45.689 125.118 46.471 ;
     RECT  125.964 46.075 127.242 46.471 ;
     RECT  111.42 46.471 127.242 46.747 ;
     RECT  111.42 46.747 127.674 46.949 ;
     RECT  128.808 45.355 128.826 47.039 ;
     RECT  111.42 46.949 127.098 47.111 ;
     RECT  95.904 44.581 96.21 47.281 ;
     RECT  97.02 34.465 102.654 47.281 ;
     RECT  95.904 47.281 102.654 47.623 ;
     RECT  103.428 28.723 106.326 47.623 ;
     RECT  128.196 47.083 128.286 47.687 ;
     RECT  128.232 47.687 128.286 48.091 ;
     RECT  111.42 47.111 127.026 48.695 ;
     RECT  126 48.695 127.026 48.775 ;
     RECT  95.904 47.623 106.326 48.973 ;
     RECT  107.136 38.443 110.697 48.973 ;
     RECT  128.232 48.091 128.826 49.469 ;
     RECT  111.42 48.695 125.154 49.549 ;
     RECT  126 48.775 127.098 49.549 ;
     RECT  94.215 45.967 95.13 49.747 ;
     RECT  95.904 48.973 110.697 49.747 ;
     RECT  111.42 49.549 127.098 49.771 ;
     RECT  111.42 49.771 127.674 49.847 ;
     RECT  128.808 49.469 128.826 50.779 ;
     RECT  128.196 50.779 128.826 50.819 ;
     RECT  111.42 49.847 127.062 50.935 ;
     RECT  111.42 50.935 127.098 51.089 ;
     RECT  88.815 2.413 89.097 51.115 ;
     RECT  128.196 50.819 128.358 51.115 ;
     RECT  89.928 51.241 89.946 51.293 ;
     RECT  88.344 51.115 89.097 51.355 ;
     RECT  92.7 32.971 92.718 51.601 ;
     RECT  88.344 51.355 89.802 51.629 ;
     RECT  88.344 51.629 89.097 51.665 ;
     RECT  128.088 51.115 128.358 51.737 ;
     RECT  111.42 51.089 127.062 51.899 ;
     RECT  128.808 51.781 128.862 52.157 ;
     RECT  111.42 51.899 126.99 52.169 ;
     RECT  128.808 52.157 128.826 52.459 ;
     RECT  128.772 52.459 128.826 52.709 ;
     RECT  111.42 52.169 126.897 52.987 ;
     RECT  128.808 52.709 128.826 52.987 ;
     RECT  128.808 52.987 129.51 53.165 ;
     RECT  2.415 33.845 2.697 53.365 ;
     RECT  4.788 33.845 4.806 53.365 ;
     RECT  2.415 53.365 3.33 53.401 ;
     RECT  4.572 53.365 4.806 53.401 ;
     RECT  111.42 52.987 126.99 53.467 ;
     RECT  111.42 53.467 127.674 53.519 ;
     RECT  2.415 53.401 3.402 53.671 ;
     RECT  4.464 53.401 4.806 53.941 ;
     RECT  2.415 53.671 3.618 53.995 ;
     RECT  2.304 53.995 3.618 54.031 ;
     RECT  4.464 53.941 4.878 54.031 ;
     RECT  72.615 2.413 72.897 54.031 ;
     RECT  128.808 53.165 128.826 54.031 ;
     RECT  2.304 54.031 4.878 54.095 ;
     RECT  128.808 54.031 129.51 54.173 ;
     RECT  5.796 54.328 5.814 54.365 ;
     RECT  111.42 53.519 127.134 54.481 ;
     RECT  45.615 2.413 45.897 54.571 ;
     RECT  56.415 2.413 56.697 54.571 ;
     RECT  67.215 2.413 67.497 54.571 ;
     RECT  78.015 2.413 78.297 54.571 ;
     RECT  88.815 51.665 89.097 54.571 ;
     RECT  32.256 54.331 32.274 54.599 ;
     RECT  33.048 54.571 33.066 54.607 ;
     RECT  88.704 54.571 89.097 54.607 ;
     RECT  45.504 54.571 45.897 54.608 ;
     RECT  56.304 54.571 56.697 54.608 ;
     RECT  67.104 54.571 67.497 54.608 ;
     RECT  77.904 54.571 78.297 54.608 ;
     RECT  88.704 54.607 89.658 54.608 ;
     RECT  2.415 54.095 4.878 54.643 ;
     RECT  2.415 54.643 5.49 54.701 ;
     RECT  32.652 54.607 33.066 54.701 ;
     RECT  6.84 54.607 6.858 54.707 ;
     RECT  30.78 54.607 30.798 54.707 ;
     RECT  32.652 54.701 32.67 54.707 ;
     RECT  111.42 54.481 127.71 54.845 ;
     RECT  128.808 54.173 128.826 54.869 ;
     RECT  2.415 54.701 3.186 55.139 ;
     RECT  2.415 55.139 3.006 55.283 ;
     RECT  86.904 33.781 87.498 55.381 ;
     RECT  88.815 54.608 89.658 55.381 ;
     RECT  3.96 54.701 5.49 55.445 ;
     RECT  111.42 54.845 127.098 55.795 ;
     RECT  128.232 55.147 128.25 55.819 ;
     RECT  111.42 55.795 127.134 55.949 ;
     RECT  128.232 55.819 128.826 56.155 ;
     RECT  128.232 56.155 128.862 56.669 ;
     RECT  111.42 55.949 126.954 56.875 ;
     RECT  128.232 56.669 128.826 56.912 ;
     RECT  111.42 56.875 127.134 57.029 ;
     RECT  92.7 51.601 92.97 57.271 ;
     RECT  94.215 49.747 110.697 57.271 ;
     RECT  3.96 55.445 3.978 57.299 ;
     RECT  128.232 56.912 128.25 57.541 ;
     RECT  128.196 57.541 128.25 57.883 ;
     RECT  128.196 57.883 128.826 58.109 ;
     RECT  4.788 55.445 5.49 58.123 ;
     RECT  128.196 58.109 128.286 58.219 ;
     RECT  4.788 58.123 6.03 58.379 ;
     RECT  111.42 57.029 126.954 58.387 ;
     RECT  127.692 58.219 128.286 58.387 ;
     RECT  111.42 58.387 128.286 58.589 ;
     RECT  6.336 58.531 6.354 58.685 ;
     RECT  111.42 58.589 128.25 58.757 ;
     RECT  4.788 58.379 5.49 58.973 ;
     RECT  111.42 58.757 127.134 59.459 ;
     RECT  53.424 59.431 53.442 59.515 ;
     RECT  64.656 43.901 64.674 59.549 ;
     RECT  128.088 58.757 128.25 59.563 ;
     RECT  125.964 59.459 127.134 59.575 ;
     RECT  128.088 59.563 128.826 59.639 ;
     RECT  48.024 59.431 48.042 59.701 ;
     RECT  47.7 59.701 48.042 59.729 ;
     RECT  47.7 59.729 47.718 59.741 ;
     RECT  125.964 59.575 127.206 59.773 ;
     RECT  128.088 59.639 128.25 59.773 ;
     RECT  90.936 44.041 91.062 59.809 ;
     RECT  53.1 59.515 53.442 59.837 ;
     RECT  53.1 59.837 53.118 59.843 ;
     RECT  125.964 59.773 128.25 60.035 ;
     RECT  4.86 58.973 5.49 60.143 ;
     RECT  126 60.035 128.25 60.269 ;
     RECT  90.9 59.809 91.062 60.313 ;
     RECT  92.7 57.271 110.697 60.349 ;
     RECT  85.176 60.331 85.194 60.379 ;
     RECT  92.664 60.349 110.697 60.385 ;
     RECT  111.42 59.459 125.19 60.385 ;
     RECT  72.615 54.031 73.242 60.701 ;
     RECT  128.124 60.269 128.25 60.907 ;
     RECT  85.176 60.379 85.806 60.955 ;
     RECT  90.792 60.313 91.062 60.961 ;
     RECT  126 60.269 126.897 61.195 ;
     RECT  92.664 60.385 125.19 61.231 ;
     RECT  126 61.195 127.098 61.231 ;
     RECT  128.124 60.907 128.826 61.349 ;
     RECT  92.664 61.231 127.098 61.373 ;
     RECT  92.664 61.373 103.014 61.387 ;
     RECT  86.904 55.381 89.658 61.435 ;
     RECT  103.86 61.373 127.098 61.579 ;
     RECT  128.124 61.349 128.25 61.579 ;
     RECT  103.86 61.579 128.25 61.691 ;
     RECT  90.792 60.961 91.242 61.963 ;
     RECT  92.088 61.387 103.014 61.963 ;
     RECT  86.904 61.435 90.054 62.011 ;
     RECT  90.792 61.963 103.014 62.011 ;
     RECT  103.86 61.691 127.062 62.159 ;
     RECT  128.232 61.691 128.25 62.251 ;
     RECT  86.904 62.011 103.014 62.311 ;
     RECT  103.86 62.159 125.262 62.311 ;
     RECT  128.232 62.251 128.358 62.339 ;
     RECT  86.904 62.311 125.262 62.525 ;
     RECT  126.432 62.159 127.062 62.545 ;
     RECT  4.86 60.143 4.878 62.609 ;
     RECT  86.904 62.525 116.586 62.735 ;
     RECT  117.324 62.525 125.262 62.941 ;
     RECT  126.432 62.545 127.314 62.941 ;
     RECT  117.324 62.941 127.314 63.041 ;
     RECT  86.904 62.735 86.922 63.149 ;
     RECT  45.615 54.608 45.897 63.211 ;
     RECT  56.415 54.608 56.697 63.211 ;
     RECT  67.215 54.608 67.497 63.211 ;
     RECT  78.015 54.608 78.297 63.211 ;
     RECT  128.232 62.339 128.286 63.239 ;
     RECT  45.504 63.211 45.897 63.248 ;
     RECT  56.304 63.211 56.697 63.248 ;
     RECT  67.104 63.211 67.497 63.248 ;
     RECT  77.904 63.211 78.297 63.248 ;
     RECT  87.804 62.735 116.586 63.319 ;
     RECT  117.324 63.041 126.897 63.319 ;
     RECT  127.656 63.259 127.674 63.509 ;
     RECT  86.652 63.391 86.67 63.581 ;
     RECT  84.6 60.955 85.806 63.589 ;
     RECT  78.015 63.248 78.297 63.661 ;
     RECT  87.804 63.319 126.897 63.779 ;
     RECT  126.252 63.779 126.897 64.021 ;
     RECT  126.252 64.021 127.098 64.121 ;
     RECT  78.015 63.661 78.93 64.201 ;
     RECT  128.772 63.595 128.826 64.267 ;
     RECT  126.252 64.121 126.897 64.561 ;
     RECT  20.16 63.553 20.178 64.651 ;
     RECT  2.415 55.283 2.697 64.795 ;
     RECT  2.415 64.795 3.654 64.859 ;
     RECT  126.216 64.561 126.897 64.903 ;
     RECT  19.872 64.651 20.178 64.939 ;
     RECT  87.804 63.779 125.406 64.939 ;
     RECT  126.216 64.903 127.098 64.939 ;
     RECT  128.196 64.267 128.826 64.967 ;
     RECT  2.415 64.859 3.33 64.973 ;
     RECT  128.268 64.967 128.826 64.973 ;
     RECT  37.224 63.883 37.242 65.131 ;
     RECT  51.015 2.413 51.297 65.173 ;
     RECT  52.02 63.595 52.038 65.173 ;
     RECT  22.5 64.327 22.518 65.245 ;
     RECT  87.804 64.939 127.098 65.399 ;
     RECT  78.015 64.201 79.362 65.419 ;
     RECT  86.976 65.515 86.994 65.563 ;
     RECT  87.804 65.399 125.406 65.563 ;
     RECT  128.268 64.973 128.286 65.645 ;
     RECT  126.216 65.399 127.098 65.669 ;
     RECT  84.564 63.589 85.806 65.707 ;
     RECT  86.976 65.563 125.406 65.707 ;
     RECT  84.564 65.707 125.406 65.789 ;
     RECT  129.492 65.275 129.51 65.947 ;
     RECT  128.808 65.947 129.51 66.119 ;
     RECT  25.668 63.499 25.686 66.187 ;
     RECT  67.215 63.248 67.497 66.235 ;
     RECT  87.732 65.789 125.406 66.361 ;
     RECT  126.216 65.669 126.897 66.361 ;
     RECT  36.36 64.027 36.378 66.475 ;
     RECT  37.224 65.131 37.926 66.475 ;
     RECT  87.732 66.361 126.897 66.515 ;
     RECT  84.564 65.789 86.994 66.571 ;
     RECT  87.732 66.515 125.406 66.571 ;
     RECT  67.215 66.235 67.626 66.595 ;
     RECT  128.808 66.119 128.826 66.619 ;
     RECT  67.068 66.595 67.626 66.631 ;
     RECT  40.215 2.413 40.497 66.763 ;
     RECT  34.815 2.413 35.097 66.793 ;
     RECT  39.42 65.659 39.438 66.811 ;
     RECT  39.312 66.811 39.438 66.859 ;
     RECT  40.215 66.763 40.95 66.859 ;
     RECT  126.216 66.515 126.897 66.865 ;
     RECT  128.232 66.619 128.826 66.955 ;
     RECT  45.615 63.248 45.897 66.991 ;
     RECT  56.415 63.248 56.697 66.991 ;
     RECT  78.015 65.419 79.974 66.991 ;
     RECT  24.015 2.413 24.297 67.003 ;
     RECT  36.36 66.475 37.926 67.019 ;
     RECT  84.564 66.571 125.406 67.051 ;
     RECT  23.904 67.003 24.297 67.055 ;
     RECT  51.015 65.173 52.038 67.099 ;
     RECT  84.492 67.051 125.406 67.261 ;
     RECT  126.216 66.865 126.954 67.261 ;
     RECT  128.232 66.955 128.862 67.325 ;
     RECT  19.656 64.939 20.178 67.339 ;
     RECT  77.904 66.991 79.974 67.387 ;
     RECT  24.015 67.055 24.297 67.405 ;
     RECT  25.02 66.187 25.686 67.405 ;
     RECT  128.808 67.325 128.862 67.469 ;
     RECT  84.492 67.261 126.954 67.559 ;
     RECT  45.504 66.991 45.897 67.568 ;
     RECT  56.304 66.991 56.697 67.568 ;
     RECT  4.968 65.821 4.986 67.639 ;
     RECT  126.615 67.559 126.954 67.675 ;
     RECT  126.615 67.675 127.062 67.829 ;
     RECT  84.492 67.559 125.622 67.865 ;
     RECT  4.968 67.639 5.598 67.915 ;
     RECT  4.536 67.915 5.598 67.945 ;
     RECT  77.904 67.387 80.082 68.009 ;
     RECT  128.808 67.469 128.826 68.347 ;
     RECT  78.015 68.009 80.082 68.405 ;
     RECT  4.536 67.945 5.634 68.443 ;
     RECT  6.372 68.347 6.39 68.443 ;
     RECT  83.415 2.413 83.697 68.449 ;
     RECT  84.492 67.865 125.406 68.449 ;
     RECT  29.415 2.413 29.697 68.521 ;
     RECT  126.615 67.829 126.954 68.521 ;
     RECT  128.772 68.347 128.826 68.639 ;
     RECT  21.672 64.603 21.69 68.647 ;
     RECT  51.015 67.099 52.47 68.711 ;
     RECT  83.415 68.449 125.406 68.791 ;
     RECT  126.504 68.521 126.954 68.791 ;
     RECT  128.232 68.683 128.286 68.819 ;
     RECT  72.615 60.701 72.897 68.917 ;
     RECT  83.415 68.791 126.99 68.917 ;
     RECT  83.415 68.917 127.134 68.945 ;
     RECT  42.012 65.707 42.03 68.971 ;
     RECT  83.415 68.945 125.802 69.017 ;
     RECT  129.492 68.881 129.51 69.053 ;
     RECT  8.928 69.151 8.946 69.331 ;
     RECT  128.268 68.819 128.286 69.691 ;
     RECT  22.5 65.245 23.13 69.799 ;
     RECT  24.015 67.405 25.686 69.799 ;
     RECT  87.84 69.017 125.802 69.835 ;
     RECT  68.976 67.027 68.994 69.863 ;
     RECT  87.804 69.835 125.802 69.871 ;
     RECT  126.576 68.945 127.134 69.871 ;
     RECT  128.268 69.691 128.826 69.871 ;
     RECT  128.232 69.871 128.826 70.061 ;
     RECT  87.804 69.871 127.134 70.097 ;
     RECT  4.536 68.443 6.39 70.141 ;
     RECT  72.615 68.917 73.242 70.267 ;
     RECT  4.536 70.141 6.678 70.375 ;
     RECT  87.84 70.097 127.134 70.529 ;
     RECT  41.724 68.971 42.03 70.573 ;
     RECT  51.015 68.711 52.038 70.771 ;
     RECT  22.5 69.799 25.686 70.891 ;
     RECT  71.028 69.529 71.046 70.915 ;
     RECT  72.072 70.267 73.242 70.915 ;
     RECT  13.215 2.413 13.497 70.939 ;
     RECT  7.815 2.413 8.097 71.083 ;
     RECT  8.856 69.331 8.946 71.083 ;
     RECT  13.215 70.939 13.59 71.083 ;
     RECT  7.815 71.083 8.946 71.131 ;
     RECT  9.72 71.113 9.738 71.131 ;
     RECT  10.944 71.083 10.962 71.213 ;
     RECT  13.215 71.083 13.698 71.213 ;
     RECT  78.015 68.405 78.354 71.221 ;
     RECT  83.415 69.017 86.994 71.221 ;
     RECT  83.304 71.221 86.994 71.261 ;
     RECT  13.215 71.213 13.497 71.311 ;
     RECT  87.84 70.529 127.062 71.311 ;
     RECT  13.104 71.311 13.497 71.357 ;
     RECT  128.268 70.061 128.826 71.411 ;
     RECT  87.732 71.311 127.062 71.455 ;
     RECT  87.732 71.455 127.098 71.519 ;
     RECT  128.268 71.411 128.286 71.707 ;
     RECT  39.312 66.859 40.95 71.725 ;
     RECT  41.724 70.573 42.426 71.725 ;
     RECT  7.815 71.131 9.738 71.761 ;
     RECT  51.015 70.771 52.146 72.185 ;
     RECT  67.068 66.631 68.238 72.283 ;
     RECT  69.192 70.951 69.21 72.283 ;
     RECT  77.904 71.221 78.354 72.329 ;
     RECT  128.196 71.707 128.286 72.379 ;
     RECT  128.196 72.379 128.826 72.419 ;
     RECT  87.84 71.519 127.098 72.535 ;
     RECT  18.615 2.413 18.897 72.667 ;
     RECT  19.656 67.339 20.61 72.667 ;
     RECT  71.028 70.915 73.242 72.697 ;
     RECT  87.84 72.535 127.278 72.761 ;
     RECT  67.068 72.283 69.21 72.769 ;
     RECT  128.196 72.419 128.25 72.769 ;
     RECT  18.615 72.667 20.61 72.797 ;
     RECT  71.028 72.697 73.35 72.805 ;
     RECT  82.08 70.843 82.098 72.833 ;
     RECT  67.068 72.769 69.318 72.841 ;
     RECT  128.052 72.769 128.25 72.869 ;
     RECT  128.052 72.869 128.07 73.085 ;
     RECT  87.876 72.761 127.278 73.517 ;
     RECT  70.164 71.077 70.182 73.579 ;
     RECT  74.376 69.259 74.394 73.679 ;
     RECT  87.876 73.517 127.242 73.757 ;
     RECT  48.384 73.741 48.402 73.805 ;
     RECT  47.592 73.921 47.61 73.997 ;
     RECT  128.808 73.387 128.826 74.059 ;
     RECT  16.2 72.763 16.218 74.107 ;
     RECT  70.164 73.579 70.218 74.155 ;
     RECT  70.956 72.805 73.35 74.155 ;
     RECT  87.876 73.757 127.206 74.203 ;
     RECT  70.164 74.155 73.35 74.389 ;
     RECT  74.268 73.885 74.286 74.389 ;
     RECT  128.772 74.059 128.826 74.395 ;
     RECT  56.415 67.568 56.697 74.461 ;
     RECT  87.804 74.203 127.206 74.489 ;
     RECT  128.124 74.395 128.826 74.489 ;
     RECT  15.624 74.107 16.218 74.551 ;
     RECT  14.94 74.551 16.218 74.579 ;
     RECT  128.772 74.489 128.826 74.579 ;
     RECT  4.536 70.375 7.002 74.587 ;
     RECT  51.015 72.185 52.074 74.587 ;
     RECT  53.208 73.345 53.226 74.587 ;
     RECT  2.415 64.973 2.697 74.615 ;
     RECT  14.94 74.579 14.958 74.621 ;
     RECT  45.615 67.568 45.897 74.659 ;
     RECT  46.62 67.291 46.638 74.659 ;
     RECT  2.415 74.615 3.402 74.731 ;
     RECT  4.392 74.587 7.002 74.731 ;
     RECT  78.015 72.329 78.354 74.731 ;
     RECT  79.344 68.405 80.082 74.731 ;
     RECT  87.876 74.489 127.206 74.849 ;
     RECT  51.015 74.587 53.226 74.857 ;
     RECT  16.2 74.579 16.218 74.875 ;
     RECT  83.415 71.261 86.994 74.885 ;
     RECT  75.06 73.921 75.078 74.893 ;
     RECT  78.015 74.731 80.226 74.957 ;
     RECT  128.808 74.579 128.826 74.965 ;
     RECT  7.815 71.761 10.026 75.119 ;
     RECT  79.344 74.957 79.578 75.119 ;
     RECT  55.188 71.947 55.206 75.127 ;
     RECT  79.344 75.119 79.362 75.155 ;
     RECT  18.615 72.797 18.897 75.259 ;
     RECT  19.656 72.797 20.61 75.259 ;
     RECT  14.508 74.923 14.526 75.403 ;
     RECT  128.808 74.965 128.862 75.403 ;
     RECT  128.232 75.403 128.862 75.461 ;
     RECT  2.415 74.731 7.002 75.499 ;
     RECT  11.016 71.467 11.034 75.505 ;
     RECT  14.508 75.403 14.85 75.533 ;
     RECT  18.615 75.259 20.61 75.533 ;
     RECT  2.376 75.499 7.002 75.595 ;
     RECT  56.415 74.461 56.754 75.631 ;
     RECT  78.015 74.957 78.297 75.631 ;
     RECT  2.304 75.595 7.002 75.695 ;
     RECT  51.015 74.857 53.622 75.739 ;
     RECT  128.808 75.461 128.862 75.776 ;
     RECT  49.752 69.223 49.77 75.931 ;
     RECT  54.72 75.127 55.206 75.937 ;
     RECT  61.815 2.413 62.097 75.937 ;
     RECT  13.215 71.357 13.497 75.979 ;
     RECT  14.508 75.533 14.526 75.979 ;
     RECT  83.415 74.885 85.446 76.037 ;
     RECT  2.415 75.695 7.002 76.045 ;
     RECT  7.815 75.119 9.846 76.045 ;
     RECT  45.615 74.659 46.638 76.072 ;
     RECT  128.844 75.776 128.862 76.075 ;
     RECT  86.328 74.885 86.994 76.081 ;
     RECT  87.876 74.849 127.134 76.081 ;
     RECT  2.415 76.045 9.846 76.109 ;
     RECT  44.172 75.775 44.19 76.219 ;
     RECT  51.015 75.739 53.982 76.243 ;
     RECT  16.2 74.875 16.29 76.267 ;
     RECT  86.328 76.081 127.17 76.271 ;
     RECT  50.724 76.243 53.982 76.315 ;
     RECT  54.72 75.937 55.35 76.315 ;
     RECT  50.724 76.315 55.35 76.343 ;
     RECT  87.732 76.271 127.17 76.351 ;
     RECT  2.415 76.109 7.002 76.469 ;
     RECT  2.415 76.469 2.862 76.505 ;
     RECT  13.215 75.979 14.526 76.603 ;
     RECT  13.104 76.603 14.526 76.649 ;
     RECT  45.504 76.072 46.638 76.649 ;
     RECT  56.304 75.631 56.754 76.649 ;
     RECT  61.815 75.937 62.73 76.649 ;
     RECT  76.392 76.279 76.41 76.649 ;
     RECT  77.904 75.631 78.297 76.649 ;
     RECT  53.208 76.343 55.35 76.711 ;
     RECT  83.415 76.037 84.69 76.711 ;
     RECT  39.312 71.725 42.426 76.747 ;
     RECT  86.328 76.271 86.994 76.775 ;
     RECT  56.415 76.649 56.754 76.783 ;
     RECT  56.415 76.783 57.042 76.855 ;
     RECT  57.852 71.899 57.87 76.855 ;
     RECT  87.732 76.351 127.314 76.883 ;
     RECT  83.376 76.711 84.69 76.919 ;
     RECT  38.772 76.747 42.426 77.083 ;
     RECT  43.416 75.811 43.434 77.083 ;
     RECT  66.42 72.841 69.318 77.083 ;
     RECT  51.015 76.343 52.398 77.131 ;
     RECT  83.415 76.919 84.69 77.359 ;
     RECT  85.428 76.037 85.446 77.359 ;
     RECT  7.815 76.109 9.846 77.395 ;
     RECT  128.844 76.075 129.51 77.453 ;
     RECT  87.876 76.883 127.314 77.459 ;
     RECT  70.164 74.389 74.286 77.563 ;
     RECT  75.06 74.893 75.258 77.563 ;
     RECT  78.015 76.649 78.297 77.563 ;
     RECT  78.015 77.563 78.678 77.755 ;
     RECT  128.844 77.453 128.862 77.789 ;
     RECT  13.215 76.649 14.526 77.791 ;
     RECT  48.42 77.515 48.438 77.791 ;
     RECT  58.716 76.243 58.734 77.791 ;
     RECT  61.815 76.649 62.097 77.791 ;
     RECT  18.615 75.533 18.897 77.803 ;
     RECT  70.164 77.563 75.258 77.819 ;
     RECT  45.615 76.649 46.638 77.827 ;
     RECT  48.24 77.791 48.438 77.827 ;
     RECT  49.212 75.931 49.77 77.827 ;
     RECT  48.24 77.827 49.77 77.837 ;
     RECT  58.716 77.791 59.274 77.855 ;
     RECT  78.015 77.755 78.786 77.885 ;
     RECT  61.815 77.791 62.73 77.891 ;
     RECT  18.252 77.803 18.897 77.927 ;
     RECT  45.615 77.827 46.782 77.927 ;
     RECT  48.492 77.837 49.77 77.927 ;
     RECT  70.164 77.819 75.078 77.933 ;
     RECT  66.42 77.083 69.354 77.935 ;
     RECT  70.164 77.933 74.286 77.935 ;
     RECT  18.615 77.927 18.897 77.971 ;
     RECT  19.656 75.533 20.61 77.971 ;
     RECT  18.615 77.971 20.61 78.029 ;
     RECT  78.015 77.885 78.39 78.029 ;
     RECT  87.876 77.459 127.278 78.089 ;
     RECT  4.32 76.469 7.002 78.205 ;
     RECT  7.776 77.395 9.846 78.205 ;
     RECT  78.015 78.029 78.297 78.205 ;
     RECT  45.615 77.927 46.638 78.232 ;
     RECT  53.208 76.711 55.674 78.232 ;
     RECT  56.415 76.855 57.87 78.232 ;
     RECT  60.444 77.017 60.462 78.241 ;
     RECT  13.104 77.791 14.526 78.269 ;
     RECT  91.44 78.089 127.278 78.331 ;
     RECT  60.336 78.241 60.462 78.395 ;
     RECT  87.876 78.089 90.702 78.475 ;
     RECT  87.84 78.475 90.702 78.629 ;
     RECT  87.84 78.629 90.63 78.665 ;
     RECT  59.256 77.855 59.274 78.673 ;
     RECT  128.808 78.475 128.826 78.715 ;
     RECT  12.24 71.083 12.258 78.781 ;
     RECT  61.815 77.891 62.097 78.781 ;
     RECT  66.42 77.935 74.286 78.781 ;
     RECT  75.06 77.933 75.078 78.781 ;
     RECT  91.44 78.331 127.314 78.797 ;
     RECT  53.208 78.232 57.87 78.809 ;
     RECT  22.5 70.891 25.722 78.899 ;
     RECT  128.808 78.715 129.51 78.899 ;
     RECT  2.415 76.505 2.697 78.907 ;
     RECT  44.172 76.219 44.694 78.907 ;
     RECT  45.504 78.232 46.638 78.907 ;
     RECT  2.415 78.907 3.186 79.045 ;
     RECT  77.904 78.205 78.297 79.045 ;
     RECT  59.184 78.673 59.274 79.051 ;
     RECT  77.904 79.045 78.39 79.051 ;
     RECT  91.44 78.797 127.278 79.051 ;
     RECT  2.415 79.045 3.33 79.099 ;
     RECT  4.32 78.205 9.846 79.099 ;
     RECT  56.415 78.809 57.87 79.169 ;
     RECT  61.815 78.781 62.73 79.169 ;
     RECT  66.42 78.781 75.078 79.169 ;
     RECT  80.964 79.051 80.982 79.169 ;
     RECT  129.492 78.899 129.51 79.181 ;
     RECT  61.815 79.169 62.694 79.229 ;
     RECT  2.415 79.099 9.846 79.321 ;
     RECT  83.415 77.359 85.446 79.321 ;
     RECT  77.904 79.051 78.462 79.373 ;
     RECT  59.184 79.051 59.31 79.447 ;
     RECT  60.336 78.395 60.354 79.447 ;
     RECT  11.016 75.505 11.142 79.483 ;
     RECT  15.66 76.267 16.29 79.483 ;
     RECT  87.876 78.665 90.63 79.483 ;
     RECT  91.404 79.051 127.278 79.483 ;
     RECT  13.215 78.269 14.526 79.511 ;
     RECT  15.552 79.483 16.29 79.531 ;
     RECT  18.615 78.029 18.897 79.579 ;
     RECT  19.656 78.029 20.61 79.579 ;
     RECT  87.876 79.483 127.278 79.591 ;
     RECT  15.372 79.531 16.29 79.723 ;
     RECT  61.815 79.229 62.097 79.723 ;
     RECT  78.015 79.373 78.462 79.819 ;
     RECT  26.568 65.281 26.586 79.825 ;
     RECT  27.612 79.789 27.63 79.825 ;
     RECT  87.876 79.591 127.674 79.853 ;
     RECT  87.876 79.853 127.314 79.861 ;
     RECT  78.015 79.819 78.858 79.915 ;
     RECT  83.304 79.321 85.446 79.915 ;
     RECT  83.232 79.915 85.446 79.979 ;
     RECT  26.568 79.825 27.63 80.023 ;
     RECT  28.764 68.521 29.697 80.023 ;
     RECT  78.015 79.915 78.966 80.045 ;
     RECT  17.496 79.291 17.514 80.059 ;
     RECT  18.615 79.579 20.61 80.059 ;
     RECT  12.204 78.781 12.258 80.131 ;
     RECT  11.988 80.131 12.258 80.221 ;
     RECT  13.215 79.511 14.274 80.221 ;
     RECT  15.372 79.723 16.506 80.221 ;
     RECT  86.364 76.775 86.994 80.221 ;
     RECT  87.768 79.861 127.314 80.221 ;
     RECT  2.376 79.321 9.846 80.251 ;
     RECT  2.376 80.251 10.026 80.257 ;
     RECT  15.372 80.221 16.65 80.257 ;
     RECT  17.496 80.059 20.61 80.257 ;
     RECT  11.988 80.221 14.274 80.329 ;
     RECT  15.372 80.257 20.61 80.329 ;
     RECT  22.68 78.899 25.722 80.365 ;
     RECT  53.208 78.809 55.674 80.392 ;
     RECT  56.415 79.169 57.618 80.392 ;
     RECT  2.304 80.257 10.026 80.395 ;
     RECT  10.764 79.483 11.142 80.395 ;
     RECT  11.988 80.329 20.61 80.395 ;
     RECT  21.348 68.647 21.69 80.395 ;
     RECT  22.5 80.365 25.722 80.395 ;
     RECT  34.308 66.793 35.097 80.395 ;
     RECT  36.36 67.019 36.378 80.395 ;
     RECT  37.224 67.019 37.926 80.395 ;
     RECT  66.42 79.169 74.286 80.395 ;
     RECT  75.024 79.169 75.078 80.395 ;
     RECT  81.216 80.011 81.234 80.395 ;
     RECT  30.528 79.819 30.546 80.401 ;
     RECT  81.036 80.395 81.234 80.401 ;
     RECT  83.268 79.979 85.446 80.401 ;
     RECT  53.208 80.392 57.618 80.429 ;
     RECT  2.304 80.395 11.142 80.443 ;
     RECT  11.916 80.395 20.61 80.443 ;
     RECT  78.015 80.045 78.678 80.491 ;
     RECT  81 80.401 81.234 80.491 ;
     RECT  30.528 80.401 30.87 80.587 ;
     RECT  37.116 80.395 37.926 80.587 ;
     RECT  38.772 77.083 43.434 80.587 ;
     RECT  59.184 79.447 60.354 80.599 ;
     RECT  2.304 80.443 20.61 80.629 ;
     RECT  21.348 80.395 25.722 80.629 ;
     RECT  32.472 80.563 32.49 80.635 ;
     RECT  30.528 80.587 31.05 80.671 ;
     RECT  32.472 80.635 32.598 80.671 ;
     RECT  61.776 79.723 62.097 80.671 ;
     RECT  77.904 80.491 78.678 80.671 ;
     RECT  56.415 80.429 57.618 80.683 ;
     RECT  76.32 80.395 76.338 80.731 ;
     RECT  77.22 80.671 78.678 80.731 ;
     RECT  30.528 80.671 31.698 80.761 ;
     RECT  32.472 80.671 32.814 80.761 ;
     RECT  34.308 80.395 36.378 80.761 ;
     RECT  37.116 80.587 43.434 80.761 ;
     RECT  66.42 80.395 75.078 80.761 ;
     RECT  80.964 80.491 81.234 80.761 ;
     RECT  82.512 80.671 82.53 80.761 ;
     RECT  83.268 80.401 85.518 80.761 ;
     RECT  80.964 80.761 81.378 80.797 ;
     RECT  61.776 80.671 62.19 80.827 ;
     RECT  80.964 80.797 81.594 80.869 ;
     RECT  2.304 80.629 25.722 80.905 ;
     RECT  26.568 80.023 29.697 80.905 ;
     RECT  66.42 80.761 75.546 80.905 ;
     RECT  76.32 80.731 78.678 80.905 ;
     RECT  2.304 80.905 29.697 80.923 ;
     RECT  30.528 80.761 32.814 80.923 ;
     RECT  49.212 77.927 49.77 80.923 ;
     RECT  56.415 80.683 57.978 80.923 ;
     RECT  58.896 80.599 60.354 80.923 ;
     RECT  80.964 80.869 81.738 80.923 ;
     RECT  79.848 79.591 79.866 80.941 ;
     RECT  80.928 80.923 81.738 80.941 ;
     RECT  82.512 80.761 85.518 80.941 ;
     RECT  44.172 78.907 46.638 80.971 ;
     RECT  66.42 80.905 78.678 80.971 ;
     RECT  79.848 80.941 85.518 80.971 ;
     RECT  86.364 80.221 127.314 80.971 ;
     RECT  2.304 80.923 32.814 81.067 ;
     RECT  33.552 80.671 33.57 81.067 ;
     RECT  50.868 77.131 52.398 81.115 ;
     RECT  53.208 80.429 55.674 81.115 ;
     RECT  66.42 80.971 78.75 81.115 ;
     RECT  2.304 81.067 33.57 81.163 ;
     RECT  34.308 80.761 43.434 81.163 ;
     RECT  2.304 81.163 43.434 81.175 ;
     RECT  129.492 80.155 129.51 81.197 ;
     RECT  50.868 81.115 55.674 81.205 ;
     RECT  56.415 80.923 60.498 81.205 ;
     RECT  79.848 80.971 127.314 81.211 ;
     RECT  49.104 80.923 49.77 81.259 ;
     RECT  61.344 80.827 62.19 81.259 ;
     RECT  49.032 81.259 49.77 81.301 ;
     RECT  50.868 81.205 60.498 81.301 ;
     RECT  61.344 81.259 62.73 81.301 ;
     RECT  49.032 81.301 49.878 81.403 ;
     RECT  48.78 81.403 49.878 81.445 ;
     RECT  66.42 81.115 78.858 81.445 ;
     RECT  79.596 81.211 127.314 81.445 ;
     RECT  61.344 81.301 63.306 81.481 ;
     RECT  65.412 81.067 65.43 81.481 ;
     RECT  48.636 81.445 49.878 81.499 ;
     RECT  65.196 81.481 65.43 81.499 ;
     RECT  66.42 81.445 127.314 81.499 ;
     RECT  2.268 81.175 43.434 81.533 ;
     RECT  47.628 81.499 49.878 81.571 ;
     RECT  50.652 81.301 60.498 81.571 ;
     RECT  61.344 81.481 63.666 81.571 ;
     RECT  64.8 81.499 127.314 81.571 ;
     RECT  47.628 81.571 127.314 81.607 ;
     RECT  44.172 80.971 46.782 81.643 ;
     RECT  44.172 81.643 46.854 81.715 ;
     RECT  47.628 81.607 127.962 81.715 ;
     RECT  2.304 81.533 43.434 81.779 ;
     RECT  2.34 81.779 43.434 82.291 ;
     RECT  44.172 81.715 127.962 82.291 ;
     RECT  2.34 82.291 127.962 82.525 ;
     RECT  2.304 82.525 127.962 82.561 ;
     RECT  1.404 82.795 1.422 83.165 ;
     RECT  129.492 82.987 129.51 83.213 ;
     RECT  2.268 82.561 127.962 83.327 ;
     RECT  2.304 83.327 127.962 83.789 ;
     RECT  2.376 83.789 127.962 84.029 ;
     RECT  2.415 84.029 13.986 84.065 ;
     RECT  15.084 84.029 25.218 84.065 ;
     RECT  90.792 84.029 93.33 84.065 ;
     RECT  101.88 84.029 123.318 84.065 ;
     RECT  124.164 84.029 124.182 84.065 ;
     RECT  125.316 84.029 127.962 84.065 ;
     RECT  2.415 84.065 10.242 84.101 ;
     RECT  15.156 84.065 25.218 84.101 ;
     RECT  25.956 84.029 36.882 84.101 ;
     RECT  52.056 84.029 52.218 84.101 ;
     RECT  53.28 84.029 62.838 84.101 ;
     RECT  64.944 84.029 80.01 84.101 ;
     RECT  87.516 84.029 89.802 84.101 ;
     RECT  91.8 84.065 93.33 84.101 ;
     RECT  94.215 84.029 97.578 84.101 ;
     RECT  101.88 84.065 107.694 84.101 ;
     RECT  115.776 84.065 121.59 84.101 ;
     RECT  15.156 84.101 19.134 84.137 ;
     RECT  101.916 84.101 107.694 84.137 ;
     RECT  108.432 84.065 114.93 84.137 ;
     RECT  121.104 84.101 121.59 84.137 ;
     RECT  126.468 84.065 127.962 84.137 ;
     RECT  126.615 84.137 127.962 84.145 ;
     RECT  15.84 84.137 19.134 84.173 ;
     RECT  32.868 84.101 36.882 84.173 ;
     RECT  49.86 84.029 51.282 84.173 ;
     RECT  64.944 84.101 77.094 84.173 ;
     RECT  80.964 84.029 80.982 84.173 ;
     RECT  115.776 84.101 115.905 84.173 ;
     RECT  4.68 84.101 5.13 84.209 ;
     RECT  25.956 84.101 32.13 84.209 ;
     RECT  32.868 84.173 35.586 84.209 ;
     RECT  89.784 84.101 89.802 84.209 ;
     RECT  90.972 84.065 90.99 84.209 ;
     RECT  91.836 84.101 93.33 84.209 ;
     RECT  98.784 84.029 101.142 84.209 ;
     RECT  101.916 84.137 105.105 84.209 ;
     RECT  108.432 84.137 108.81 84.209 ;
     RECT  109.584 84.137 114.93 84.209 ;
     RECT  116.82 84.101 120.366 84.209 ;
     RECT  121.215 84.137 121.59 84.209 ;
     RECT  122.832 84.065 123.246 84.209 ;
     RECT  125.46 84.065 125.478 84.209 ;
     RECT  50.148 84.173 51.282 84.221 ;
     RECT  64.944 84.173 76.59 84.221 ;
     RECT  77.904 84.101 80.01 84.221 ;
     RECT  82.368 84.029 85.194 84.221 ;
     RECT  87.516 84.101 88.905 84.221 ;
     RECT  96.588 84.101 97.578 84.221 ;
     RECT  98.784 84.209 98.802 84.221 ;
     RECT  99.576 84.209 101.142 84.221 ;
     RECT  101.916 84.209 103.482 84.221 ;
     RECT  106.488 84.137 107.694 84.221 ;
     RECT  120.24 84.209 120.366 84.221 ;
     RECT  2.415 84.101 3.87 84.257 ;
     RECT  5.976 84.101 10.242 84.257 ;
     RECT  15.84 84.173 18.705 84.257 ;
     RECT  37.836 84.029 48.87 84.257 ;
     RECT  88.128 84.221 88.905 84.257 ;
     RECT  94.215 84.101 95.67 84.257 ;
     RECT  104.256 84.209 105.105 84.257 ;
     RECT  110.415 84.209 111.51 84.257 ;
     RECT  115.815 84.173 115.905 84.257 ;
     RECT  121.215 84.209 121.305 84.257 ;
     RECT  126.615 84.145 128.286 84.257 ;
     RECT  36.324 84.173 36.882 84.269 ;
     RECT  53.316 84.101 54.414 84.269 ;
     RECT  63.72 84.029 64.206 84.269 ;
     RECT  64.944 84.221 67.482 84.269 ;
     RECT  70.704 84.221 76.59 84.269 ;
     RECT  82.368 84.221 84.186 84.269 ;
     RECT  92.52 84.209 92.97 84.269 ;
     RECT  96.912 84.221 97.578 84.269 ;
     RECT  102.204 84.221 103.482 84.269 ;
     RECT  104.256 84.257 104.958 84.269 ;
     RECT  112.32 84.209 112.878 84.269 ;
     RECT  79.992 84.221 80.01 84.299 ;
     RECT  92.7 84.269 92.97 84.299 ;
     RECT  100.692 84.221 100.71 84.299 ;
     RECT  67.104 84.269 67.482 84.317 ;
     RECT  120.348 84.221 120.366 84.317 ;
     RECT  77.904 84.221 79.218 84.335 ;
     RECT  2.736 84.257 3.87 84.365 ;
     RECT  4.68 84.209 4.986 84.365 ;
     RECT  5.976 84.257 7.47 84.365 ;
     RECT  8.28 84.257 10.242 84.365 ;
     RECT  11.052 84.065 13.914 84.365 ;
     RECT  15.84 84.257 18.198 84.365 ;
     RECT  19.872 84.101 25.218 84.365 ;
     RECT  25.956 84.209 26.514 84.365 ;
     RECT  27.576 84.209 32.13 84.365 ;
     RECT  32.868 84.209 33.39 84.365 ;
     RECT  34.308 84.209 35.586 84.365 ;
     RECT  36.36 84.269 36.882 84.365 ;
     RECT  37.836 84.257 39.906 84.365 ;
     RECT  40.824 84.257 48.87 84.365 ;
     RECT  50.256 84.221 51.282 84.365 ;
     RECT  53.532 84.269 54.414 84.365 ;
     RECT  55.26 84.101 62.838 84.365 ;
     RECT  70.704 84.269 71.154 84.365 ;
     RECT  72.576 84.269 74.79 84.365 ;
     RECT  84.924 84.221 85.194 84.365 ;
     RECT  94.392 84.257 95.67 84.365 ;
     RECT  96.912 84.269 97.326 84.365 ;
     RECT  99.576 84.221 99.918 84.365 ;
     RECT  102.204 84.269 103.338 84.365 ;
     RECT  110.592 84.257 111.51 84.365 ;
     RECT  113.76 84.209 114.93 84.365 ;
     RECT  122.832 84.209 122.85 84.365 ;
     RECT  127.044 84.257 128.286 84.365 ;
     RECT  48.204 84.365 48.51 84.407 ;
     RECT  13.356 84.365 13.374 84.413 ;
     RECT  24.156 84.365 24.174 84.413 ;
     RECT  29.376 84.365 29.394 84.413 ;
     RECT  45.432 84.365 45.774 84.413 ;
     RECT  127.116 84.365 128.286 84.413 ;
     RECT  48.204 84.407 48.33 84.443 ;
     RECT  110.772 84.365 111.51 84.461 ;
     RECT  65.16 84.269 65.826 84.479 ;
     RECT  116.82 84.209 118.458 84.479 ;
     RECT  50.256 84.365 50.958 84.509 ;
     RECT  63.72 84.269 64.062 84.524 ;
     RECT  113.76 84.365 114.318 84.524 ;
     RECT  50.94 84.509 50.958 84.557 ;
     RECT  56.232 84.365 56.754 84.557 ;
     RECT  61.74 84.365 61.794 84.557 ;
     RECT  62.676 84.365 62.838 84.569 ;
     RECT  110.988 84.461 111.51 84.569 ;
     RECT  113.76 84.524 113.778 84.605 ;
     RECT  67.176 84.317 67.194 84.701 ;
     RECT  72.576 84.365 74.07 84.701 ;
     RECT  82.548 84.269 84.186 84.701 ;
     RECT  94.536 84.365 95.67 84.701 ;
     RECT  99.576 84.365 99.594 84.701 ;
     RECT  104.292 84.269 104.958 84.701 ;
     RECT  65.16 84.479 65.178 84.749 ;
     RECT  18.072 84.365 18.162 84.947 ;
     RECT  103.32 84.365 103.338 84.947 ;
     RECT  61.74 84.557 61.758 84.983 ;
     RECT  117.828 84.479 118.458 84.983 ;
     RECT  4.968 84.365 4.986 84.989 ;
     RECT  9.072 84.365 9.09 84.989 ;
     RECT  18.072 84.947 18.09 84.989 ;
     RECT  33.372 84.365 33.39 84.989 ;
     RECT  45.432 84.413 45.45 84.989 ;
     RECT  56.232 84.557 56.25 84.989 ;
     RECT  112.32 84.269 112.77 84.989 ;
     RECT  118.44 84.983 118.458 84.989 ;
     RECT  127.116 84.413 127.962 84.989 ;
     RECT  54.072 84.365 54.414 85.019 ;
     RECT  106.488 84.221 106.866 85.019 ;
     RECT  63.72 84.524 63.738 85.037 ;
     RECT  68.868 84.221 69.462 85.037 ;
     RECT  73.512 84.701 74.07 85.037 ;
     RECT  77.976 84.335 79.218 85.037 ;
     RECT  82.548 84.701 82.566 85.037 ;
     RECT  84.168 84.701 84.186 85.037 ;
     RECT  86.292 84.029 86.562 85.037 ;
     RECT  88.128 84.257 88.614 85.037 ;
     RECT  52.056 84.101 52.074 85.064 ;
     RECT  102.204 84.365 102.222 85.064 ;
     RECT  88.596 85.037 88.614 85.085 ;
     RECT  95.256 84.701 95.67 85.085 ;
     RECT  104.292 84.701 104.886 85.085 ;
     RECT  106.848 85.019 106.866 85.085 ;
     RECT  86.292 85.037 86.31 85.109 ;
     RECT  108.432 84.209 108.666 85.109 ;
     RECT  12.456 84.365 12.474 85.517 ;
     RECT  16.344 84.365 16.362 85.517 ;
     RECT  36.864 84.365 36.882 85.517 ;
     RECT  48.312 84.443 48.33 85.517 ;
     RECT  55.26 84.365 55.278 85.517 ;
     RECT  59.076 84.365 59.562 85.517 ;
     RECT  60.876 84.365 60.894 85.517 ;
     RECT  71.136 84.365 71.154 85.517 ;
     RECT  79.2 85.037 79.218 85.517 ;
     RECT  108.648 85.109 108.666 85.517 ;
     RECT  127.116 84.989 127.278 85.517 ;
     RECT  43.02 84.365 43.038 85.523 ;
     RECT  112.32 84.989 112.338 85.523 ;
     RECT  40.824 84.365 40.842 85.559 ;
     RECT  109.584 84.209 109.602 85.559 ;
     RECT  39.888 84.365 39.906 86.237 ;
     RECT  22.14 84.365 22.374 86.285 ;
     RECT  25.956 84.365 25.974 86.285 ;
     RECT  34.308 84.365 34.326 86.285 ;
     RECT  47.124 84.365 47.142 86.285 ;
     RECT  54.072 85.019 54.09 86.285 ;
     RECT  59.076 85.517 59.094 86.285 ;
     RECT  62.676 84.569 62.694 86.285 ;
     RECT  69.444 85.037 69.462 86.285 ;
     RECT  85.176 84.365 85.194 86.285 ;
     RECT  92.7 84.299 92.718 86.285 ;
     RECT  95.256 85.085 95.274 86.285 ;
     RECT  97.308 84.365 97.326 86.285 ;
     RECT  104.868 85.085 104.886 86.285 ;
     RECT  107.676 84.221 107.694 86.285 ;
     RECT  110.988 84.569 111.006 86.285 ;
     RECT  116.82 84.479 116.838 86.285 ;
     RECT  127.26 85.517 127.278 86.285 ;
    LAYER M4 ;
     RECT  0.085 83.76 0.613 83.784 ;
     RECT  0.613 83.184 0.853 83.784 ;
     RECT  0.373 80.64 1.621 80.664 ;
     RECT  1.621 80.64 1.861 81.48 ;
     RECT  1.093 79.056 2.293 79.08 ;
     RECT  0.853 82.56 2.293 83.784 ;
     RECT  2.293 79.056 2.401 79.176 ;
     RECT  1.861 80.64 2.401 81.528 ;
     RECT  2.365 31.776 2.408 32.424 ;
     RECT  0.181 43.344 2.408 43.368 ;
     RECT  2.365 75.504 2.408 75.624 ;
     RECT  2.401 79.056 2.408 81.528 ;
     RECT  2.293 82.56 2.408 83.88 ;
     RECT  2.408 2.148 2.512 84.252 ;
     RECT  2.512 2.418 2.629 84.252 ;
     RECT  2.629 2.418 2.704 84.36 ;
     RECT  2.293 86.256 2.869 86.28 ;
     RECT  2.704 78.912 3.197 84.36 ;
     RECT  2.869 86.064 3.203 86.28 ;
     RECT  2.704 64.8 3.385 64.968 ;
     RECT  2.704 31.296 3.436 31.8 ;
     RECT  3.197 79.056 3.443 84.36 ;
     RECT  2.704 33.072 3.521 33.096 ;
     RECT  3.436 31.776 3.629 31.8 ;
     RECT  2.704 54.672 3.683 55.272 ;
     RECT  3.385 64.8 3.683 64.824 ;
     RECT  2.704 74.64 3.737 75.96 ;
     RECT  3.203 86.208 3.875 86.28 ;
     RECT  3.875 86.256 4.211 86.28 ;
     RECT  3.737 74.64 4.355 75.048 ;
     RECT  4.381 74.592 4.501 74.616 ;
     RECT  3.443 79.104 4.556 84.36 ;
     RECT  4.556 78.912 4.643 84.36 ;
     RECT  4.525 67.92 4.645 67.944 ;
     RECT  4.643 78.96 4.709 84.36 ;
     RECT  4.741 58.128 4.777 58.152 ;
     RECT  4.741 33.6 4.825 33.624 ;
     RECT  4.885 31.872 4.969 31.896 ;
     RECT  4.981 76.608 5.029 76.632 ;
     RECT  5.029 75.84 5.113 76.632 ;
     RECT  4.957 84.96 5.219 84.984 ;
     RECT  4.309 77.808 5.509 77.832 ;
     RECT  5.557 86.256 5.699 86.28 ;
     RECT  4.705 53.52 5.785 53.544 ;
     RECT  4.709 78.96 5.785 83.832 ;
     RECT  5.785 78.96 5.921 83.928 ;
     RECT  5.029 71.184 5.929 71.208 ;
     RECT  4.777 58.128 6.041 58.968 ;
     RECT  4.501 73.92 6.041 74.616 ;
     RECT  5.113 76.608 6.181 76.632 ;
     RECT  4.645 67.824 6.253 67.944 ;
     RECT  6.041 58.656 6.409 58.968 ;
     RECT  5.509 77.808 6.685 77.976 ;
     RECT  5.921 78.96 6.685 84.36 ;
     RECT  7.573 86.256 7.763 86.28 ;
     RECT  4.885 34.896 7.808 34.92 ;
     RECT  2.704 43.344 7.808 43.368 ;
     RECT  5.785 53.52 7.808 54.36 ;
     RECT  6.409 58.944 7.808 58.968 ;
     RECT  6.253 67.824 7.808 68.472 ;
     RECT  5.929 70.368 7.808 71.208 ;
     RECT  6.325 72.72 7.808 72.744 ;
     RECT  6.041 74.592 7.808 74.616 ;
     RECT  6.181 76.08 7.808 76.632 ;
     RECT  6.685 77.808 7.808 84.36 ;
     RECT  7.808 2.148 7.912 84.36 ;
     RECT  7.912 2.418 8.104 84.36 ;
     RECT  8.104 77.808 8.243 84.36 ;
     RECT  8.243 84.288 9.061 84.36 ;
     RECT  8.243 77.808 9.205 83.256 ;
     RECT  9.061 84.288 9.205 84.984 ;
     RECT  9.205 77.808 9.251 84.984 ;
     RECT  8.104 70.368 9.673 71.208 ;
     RECT  9.251 77.808 9.677 84.36 ;
     RECT  9.677 77.808 9.683 83.304 ;
     RECT  8.104 76.608 10.117 76.632 ;
     RECT  9.683 77.808 10.117 83.208 ;
     RECT  8.104 74.592 10.597 74.616 ;
     RECT  10.117 76.608 10.643 83.208 ;
     RECT  10.643 80.64 10.741 83.208 ;
     RECT  9.677 84.336 10.741 84.36 ;
     RECT  9.673 70.368 11.005 71.352 ;
     RECT  8.104 72.72 11.797 72.744 ;
     RECT  10.597 73.824 11.797 74.616 ;
     RECT  10.741 80.64 11.797 84.36 ;
     RECT  10.643 76.608 11.861 79.464 ;
     RECT  11.797 80.448 11.861 84.36 ;
     RECT  12.037 86.208 12.323 86.232 ;
     RECT  11.861 76.608 12.469 84.36 ;
     RECT  12.445 85.488 12.803 85.512 ;
     RECT  8.104 34.896 13.208 34.92 ;
     RECT  8.104 43.344 13.208 43.368 ;
     RECT  8.104 53.52 13.208 54.36 ;
     RECT  8.104 58.944 13.208 58.968 ;
     RECT  8.104 67.824 13.208 68.472 ;
     RECT  11.005 70.368 13.208 71.496 ;
     RECT  11.797 72.72 13.208 74.616 ;
     RECT  12.469 76.224 13.208 84.36 ;
     RECT  13.208 2.148 13.285 84.36 ;
     RECT  13.285 2.148 13.312 84.408 ;
     RECT  13.312 2.418 13.385 84.408 ;
     RECT  13.385 2.418 13.504 84.36 ;
     RECT  13.504 75.984 13.673 84.36 ;
     RECT  13.673 82.656 13.925 84.36 ;
     RECT  13.673 75.984 14.069 81.672 ;
     RECT  13.504 72.72 14.497 74.616 ;
     RECT  14.497 72.72 14.725 74.952 ;
     RECT  14.069 75.984 14.725 81.576 ;
     RECT  14.725 72.72 15.505 81.576 ;
     RECT  13.925 82.656 15.505 83.832 ;
     RECT  15.505 72.72 15.781 83.832 ;
     RECT  15.541 86.208 15.875 86.232 ;
     RECT  15.781 72.72 16.049 84.36 ;
     RECT  16.333 85.488 16.595 85.512 ;
     RECT  16.049 72.72 17.077 82.776 ;
     RECT  16.049 83.808 17.077 84.36 ;
     RECT  17.077 72.72 17.123 84.36 ;
     RECT  17.123 84.288 18.061 84.36 ;
     RECT  17.123 72.72 18.305 83.016 ;
     RECT  18.061 84.288 18.371 84.984 ;
     RECT  13.504 34.896 18.608 34.92 ;
     RECT  13.504 43.344 18.608 43.368 ;
     RECT  13.504 53.52 18.608 54.36 ;
     RECT  13.504 58.944 18.608 58.968 ;
     RECT  13.504 67.824 18.608 68.472 ;
     RECT  13.504 70.368 18.608 71.496 ;
     RECT  18.305 72.72 18.608 83.304 ;
     RECT  18.371 84.288 18.608 84.36 ;
     RECT  18.277 86.208 18.611 86.232 ;
     RECT  18.608 2.148 18.712 84.36 ;
     RECT  18.712 2.418 18.904 84.36 ;
     RECT  19.237 86.256 19.619 86.28 ;
     RECT  18.904 72.672 20.06 83.304 ;
     RECT  18.904 84.336 20.06 84.36 ;
     RECT  20.06 72.672 20.147 84.36 ;
     RECT  18.904 67.824 20.197 68.472 ;
     RECT  18.904 64.656 21.157 64.68 ;
     RECT  20.147 72.672 21.301 83.256 ;
     RECT  20.147 84.336 21.301 84.36 ;
     RECT  21.301 72.672 21.629 84.36 ;
     RECT  21.157 64.32 21.781 64.68 ;
     RECT  20.197 67.008 22.021 68.472 ;
     RECT  21.253 86.256 22.429 86.28 ;
     RECT  21.629 72.672 22.885 83.832 ;
     RECT  18.904 34.896 24.008 34.92 ;
     RECT  18.904 43.344 24.008 43.368 ;
     RECT  18.904 53.52 24.008 54.36 ;
     RECT  18.904 58.944 24.008 58.968 ;
     RECT  20.869 62.976 24.008 63 ;
     RECT  21.781 64.32 24.008 64.728 ;
     RECT  22.597 65.952 24.008 65.976 ;
     RECT  22.021 67.008 24.008 68.664 ;
     RECT  18.904 70.368 24.008 71.496 ;
     RECT  22.885 72.672 24.008 84.36 ;
     RECT  24.008 2.148 24.101 84.36 ;
     RECT  24.101 2.148 24.112 84.408 ;
     RECT  24.112 2.418 24.185 84.408 ;
     RECT  24.185 2.418 24.304 84.36 ;
     RECT  24.304 62.976 25.657 63 ;
     RECT  24.304 64.32 25.657 64.728 ;
     RECT  25.901 86.256 25.985 86.28 ;
     RECT  24.304 72.672 26.099 84.36 ;
     RECT  26.099 72.672 26.243 81.816 ;
     RECT  24.304 70.272 26.725 71.496 ;
     RECT  24.304 34.896 26.777 34.92 ;
     RECT  27.061 35.328 27.145 35.352 ;
     RECT  26.243 72.672 27.241 81.72 ;
     RECT  26.099 83.088 27.241 84.36 ;
     RECT  27.241 72.672 27.281 84.36 ;
     RECT  27.281 72.672 27.461 83.256 ;
     RECT  27.461 72.672 28.933 83.112 ;
     RECT  29.125 86.256 29.267 86.28 ;
     RECT  27.281 84.336 29.365 84.36 ;
     RECT  24.304 43.344 29.408 43.368 ;
     RECT  24.304 53.52 29.408 54.36 ;
     RECT  24.304 58.944 29.408 58.968 ;
     RECT  25.657 62.976 29.408 64.728 ;
     RECT  24.304 65.952 29.408 68.664 ;
     RECT  26.725 69.792 29.408 71.496 ;
     RECT  28.933 72.672 29.408 83.256 ;
     RECT  29.365 84.336 29.408 84.408 ;
     RECT  29.408 2.148 29.507 84.408 ;
     RECT  29.507 2.148 29.512 84.36 ;
     RECT  29.512 2.418 29.704 84.36 ;
     RECT  29.704 53.52 32.285 54.36 ;
     RECT  29.704 72.672 32.291 84.36 ;
     RECT  32.291 84.336 33.077 84.36 ;
     RECT  32.291 72.672 33.325 83.256 ;
     RECT  33.361 84.96 33.827 84.984 ;
     RECT  34.253 86.256 34.337 86.28 ;
     RECT  29.704 65.952 34.645 68.664 ;
     RECT  29.704 43.344 34.808 43.368 ;
     RECT  32.285 53.52 34.808 53.544 ;
     RECT  33.037 54.672 34.808 54.696 ;
     RECT  29.704 58.944 34.808 58.968 ;
     RECT  29.704 62.976 34.808 64.728 ;
     RECT  34.645 65.76 34.808 68.664 ;
     RECT  29.704 69.792 34.808 71.496 ;
     RECT  33.325 72.672 34.808 83.832 ;
     RECT  34.808 2.148 34.912 84.252 ;
     RECT  34.912 2.418 34.945 84.252 ;
     RECT  34.945 2.418 35.104 84.36 ;
     RECT  34.789 86.208 35.267 86.232 ;
     RECT  35.701 86.256 35.843 86.28 ;
     RECT  35.104 72.672 36.137 84.36 ;
     RECT  36.137 84.24 36.713 84.36 ;
     RECT  36.805 86.256 36.853 86.28 ;
     RECT  36.853 85.488 36.947 86.28 ;
     RECT  36.947 85.488 37.091 85.512 ;
     RECT  36.137 72.672 37.105 83.256 ;
     RECT  37.105 72.672 37.781 83.928 ;
     RECT  35.104 62.976 37.897 64.728 ;
     RECT  35.104 65.76 37.897 68.664 ;
     RECT  35.104 58.944 39.013 58.968 ;
     RECT  37.781 72.672 39.413 84.36 ;
     RECT  37.897 62.976 39.733 68.664 ;
     RECT  35.104 69.792 39.733 71.496 ;
     RECT  39.733 86.256 39.874 86.28 ;
     RECT  39.874 86.208 40.163 86.28 ;
     RECT  35.104 43.344 40.208 43.368 ;
     RECT  35.104 53.52 40.208 53.544 ;
     RECT  35.104 54.576 40.208 54.6 ;
     RECT  39.013 58.944 40.208 59.496 ;
     RECT  39.733 62.976 40.208 71.496 ;
     RECT  39.413 72.672 40.208 84.252 ;
     RECT  40.208 2.148 40.312 84.252 ;
     RECT  40.163 86.256 40.403 86.28 ;
     RECT  40.312 2.418 40.504 84.252 ;
     RECT  40.504 72.672 40.805 84.252 ;
     RECT  40.805 72.672 41.401 84.36 ;
     RECT  41.401 72.672 42.505 83.352 ;
     RECT  41.401 84.336 42.505 84.36 ;
     RECT  42.505 72.672 43.193 84.36 ;
     RECT  43.193 72.672 44.636 83.208 ;
     RECT  43.193 84.336 44.636 84.36 ;
     RECT  44.636 72.672 45.421 84.36 ;
     RECT  40.504 43.344 45.608 43.368 ;
     RECT  40.504 53.52 45.608 53.544 ;
     RECT  40.504 54.576 45.608 54.6 ;
     RECT  40.504 58.944 45.608 59.496 ;
     RECT  40.504 62.976 45.608 71.496 ;
     RECT  45.421 72.672 45.608 84.984 ;
     RECT  45.608 2.148 45.712 84.984 ;
     RECT  45.712 2.418 45.904 84.984 ;
     RECT  45.904 72.672 45.971 84.984 ;
     RECT  47.113 86.256 47.507 86.28 ;
     RECT  45.904 58.944 47.689 59.496 ;
     RECT  48.301 85.488 48.515 85.512 ;
     RECT  49.333 86.256 49.763 86.28 ;
     RECT  45.971 72.672 50.245 84.456 ;
     RECT  50.725 86.256 50.867 86.28 ;
     RECT  50.245 72.672 50.924 84.504 ;
     RECT  45.904 43.344 51.008 43.368 ;
     RECT  45.904 53.52 51.008 53.544 ;
     RECT  45.904 54.576 51.008 54.6 ;
     RECT  47.689 58.944 51.008 59.736 ;
     RECT  45.904 62.976 51.008 71.496 ;
     RECT  50.924 72.672 51.008 84.552 ;
     RECT  51.008 2.148 51.011 84.552 ;
     RECT  51.011 2.148 51.112 84.504 ;
     RECT  51.112 2.418 51.304 84.504 ;
     RECT  51.304 58.944 53.497 59.832 ;
     RECT  54.017 86.256 54.659 86.28 ;
     RECT  51.304 62.976 55.177 71.496 ;
     RECT  51.304 72.672 55.177 84.504 ;
     RECT  55.249 85.488 55.571 85.512 ;
     RECT  55.177 62.976 56.221 84.504 ;
     RECT  51.304 43.344 56.408 43.368 ;
     RECT  51.304 53.52 56.408 53.544 ;
     RECT  51.304 54.576 56.408 54.6 ;
     RECT  53.497 58.944 56.408 59.544 ;
     RECT  56.221 62.976 56.408 84.984 ;
     RECT  56.408 2.148 56.512 84.984 ;
     RECT  56.512 2.418 56.704 84.984 ;
     RECT  59.065 86.256 59.149 86.28 ;
     RECT  56.704 62.976 59.533 84.984 ;
     RECT  59.533 62.976 59.891 85.512 ;
     RECT  59.891 62.976 60.865 84.984 ;
     RECT  60.865 62.976 61.139 85.512 ;
     RECT  56.704 43.344 61.808 43.368 ;
     RECT  56.704 53.52 61.808 53.544 ;
     RECT  56.704 54.576 61.808 54.6 ;
     RECT  56.704 58.944 61.808 59.544 ;
     RECT  61.139 62.976 61.808 84.984 ;
     RECT  61.808 2.148 61.912 84.984 ;
     RECT  61.912 2.418 62.104 84.984 ;
     RECT  61.669 86.208 62.147 86.232 ;
     RECT  62.665 86.256 62.915 86.28 ;
     RECT  62.104 62.976 63.709 84.984 ;
     RECT  63.709 62.976 63.923 85.032 ;
     RECT  62.104 43.344 64.037 43.368 ;
     RECT  64.069 51.264 64.357 51.288 ;
     RECT  64.357 51.12 64.403 51.288 ;
     RECT  64.357 43.872 64.441 43.896 ;
     RECT  64.403 51.12 67.208 51.144 ;
     RECT  62.104 53.52 67.208 53.544 ;
     RECT  62.104 54.576 67.208 54.6 ;
     RECT  62.104 58.944 67.208 59.544 ;
     RECT  63.923 62.976 67.208 84.984 ;
     RECT  67.208 2.148 67.312 84.984 ;
     RECT  67.312 2.418 67.504 84.984 ;
     RECT  67.429 86.256 67.619 86.28 ;
     RECT  67.504 62.976 68.857 84.984 ;
     RECT  68.857 62.976 69.011 85.032 ;
     RECT  69.433 86.256 69.517 86.28 ;
     RECT  69.011 62.976 71.125 84.984 ;
     RECT  71.125 62.976 71.555 85.512 ;
     RECT  67.504 51.12 72.608 51.144 ;
     RECT  67.504 53.52 72.608 53.544 ;
     RECT  67.504 54.576 72.608 54.6 ;
     RECT  67.504 58.944 72.608 59.544 ;
     RECT  71.555 62.976 72.608 84.984 ;
     RECT  72.608 2.148 72.712 84.984 ;
     RECT  72.712 2.418 72.904 84.984 ;
     RECT  72.904 62.976 73.484 84.984 ;
     RECT  73.484 62.976 74.339 85.032 ;
     RECT  75.445 86.256 75.587 86.28 ;
     RECT  74.339 62.976 77.965 84.984 ;
     RECT  72.904 51.12 78.008 51.144 ;
     RECT  72.904 53.52 78.008 53.544 ;
     RECT  72.904 54.576 78.008 54.6 ;
     RECT  72.904 58.944 78.008 59.544 ;
     RECT  72.904 60.672 78.008 60.696 ;
     RECT  77.965 62.976 78.008 85.032 ;
     RECT  78.008 2.148 78.112 85.032 ;
     RECT  78.112 2.418 78.304 85.032 ;
     RECT  78.304 62.976 79.189 85.032 ;
     RECT  79.189 62.976 79.379 85.512 ;
     RECT  80.869 86.256 81.011 86.28 ;
     RECT  81.109 86.208 82.211 86.232 ;
     RECT  79.379 62.976 82.537 84.984 ;
     RECT  82.645 86.256 82.835 86.28 ;
     RECT  82.537 62.976 82.931 85.032 ;
     RECT  82.931 62.976 83.269 84.984 ;
     RECT  78.304 51.12 83.408 51.144 ;
     RECT  78.304 53.52 83.408 53.544 ;
     RECT  78.304 54.576 83.408 54.6 ;
     RECT  78.304 58.944 83.408 59.544 ;
     RECT  78.304 60.672 83.408 60.696 ;
     RECT  83.269 62.736 83.408 84.984 ;
     RECT  83.408 2.148 83.512 84.984 ;
     RECT  83.512 2.418 83.704 84.984 ;
     RECT  83.704 62.736 84.157 84.984 ;
     RECT  84.157 62.736 84.419 85.032 ;
     RECT  83.704 58.944 85.165 59.544 ;
     RECT  83.704 60.672 85.165 60.984 ;
     RECT  84.133 86.256 85.205 86.28 ;
     RECT  84.419 62.736 86.533 84.984 ;
     RECT  86.533 62.736 86.723 85.032 ;
     RECT  86.723 62.736 87.793 84.984 ;
     RECT  87.793 62.208 88.117 84.984 ;
     RECT  88.117 62.208 88.585 85.032 ;
     RECT  83.704 51.12 88.808 51.144 ;
     RECT  83.704 53.52 88.808 53.544 ;
     RECT  83.704 54.576 88.808 54.6 ;
     RECT  85.165 58.944 88.808 60.984 ;
     RECT  88.585 62.208 88.808 85.08 ;
     RECT  88.808 2.148 88.912 85.08 ;
     RECT  88.912 2.418 88.979 85.08 ;
     RECT  88.979 2.418 89.104 85.032 ;
     RECT  89.317 86.256 89.987 86.28 ;
     RECT  89.104 51.264 90.001 51.384 ;
     RECT  89.104 59.52 90.275 85.032 ;
     RECT  92.005 86.208 92.243 86.232 ;
     RECT  89.104 54.576 92.627 54.6 ;
     RECT  92.689 86.256 93.059 86.28 ;
     RECT  90.001 51.36 94.208 51.384 ;
     RECT  90.275 60.336 94.208 85.032 ;
     RECT  94.208 2.148 94.312 85.032 ;
     RECT  94.312 2.418 94.504 85.032 ;
     RECT  94.504 60.336 95.641 85.032 ;
     RECT  95.641 60.336 95.843 85.08 ;
     RECT  95.245 86.256 96.037 86.28 ;
     RECT  96.037 86.208 96.659 86.28 ;
     RECT  97.117 58.704 97.265 58.728 ;
     RECT  96.659 86.256 97.337 86.28 ;
     RECT  98.581 86.256 98.771 86.28 ;
     RECT  99.397 30.576 99.608 30.6 ;
     RECT  99.445 32.784 99.608 32.808 ;
     RECT  94.504 51.36 99.608 51.384 ;
     RECT  99.349 54.912 99.608 54.936 ;
     RECT  95.843 60.336 99.608 85.032 ;
     RECT  99.608 2.148 99.712 85.032 ;
     RECT  99.712 2.418 99.904 85.032 ;
     RECT  99.904 51.36 99.965 51.864 ;
     RECT  99.829 86.256 100.019 86.28 ;
     RECT  99.965 51.84 102.589 51.864 ;
     RECT  99.904 60.336 102.589 85.032 ;
     RECT  102.589 51.744 102.629 51.864 ;
     RECT  102.589 60.288 104.281 85.032 ;
     RECT  104.281 60.288 104.435 85.08 ;
     RECT  99.904 11.28 105.008 11.304 ;
     RECT  99.904 30.576 105.008 30.6 ;
     RECT  99.904 32.784 105.008 32.808 ;
     RECT  104.869 36.528 105.008 36.552 ;
     RECT  102.629 51.744 105.008 51.768 ;
     RECT  99.904 54.912 105.008 54.936 ;
     RECT  104.435 60.288 105.008 85.032 ;
     RECT  105.008 2.148 105.112 85.032 ;
     RECT  105.112 2.418 105.304 85.032 ;
     RECT  103.909 86.256 106.309 86.28 ;
     RECT  105.304 60.288 106.445 85.032 ;
     RECT  106.309 86.208 106.451 86.28 ;
     RECT  105.304 51.84 106.585 51.864 ;
     RECT  106.585 51.744 106.625 51.864 ;
     RECT  106.445 60.336 106.837 85.032 ;
     RECT  106.837 60.336 107.459 85.08 ;
     RECT  106.451 86.256 107.987 86.28 ;
     RECT  107.459 60.336 108.637 85.032 ;
     RECT  106.625 51.744 108.709 51.768 ;
     RECT  108.637 60.336 108.995 85.512 ;
     RECT  109.957 86.208 110.195 86.232 ;
     RECT  105.304 11.28 110.408 11.304 ;
     RECT  105.304 30.576 110.408 30.6 ;
     RECT  105.304 32.784 110.408 32.808 ;
     RECT  105.304 36.528 110.408 36.552 ;
     RECT  108.709 51.648 110.408 51.768 ;
     RECT  105.304 54.912 110.408 54.936 ;
     RECT  108.995 60.336 110.408 85.032 ;
     RECT  110.408 2.148 110.512 85.032 ;
     RECT  110.512 2.418 110.704 85.032 ;
     RECT  110.293 86.256 111.875 86.28 ;
     RECT  110.704 51.648 113.141 51.864 ;
     RECT  110.704 60.288 113.825 85.032 ;
     RECT  113.989 86.256 114.179 86.28 ;
     RECT  113.141 51.84 114.577 51.864 ;
     RECT  114.577 51.744 114.617 51.864 ;
     RECT  113.825 60.336 115.283 85.032 ;
     RECT  110.704 11.28 115.808 11.304 ;
     RECT  113.653 16.32 115.808 16.344 ;
     RECT  114.229 17.376 115.808 17.4 ;
     RECT  110.704 30.576 115.808 30.6 ;
     RECT  110.704 32.784 115.808 32.808 ;
     RECT  110.704 36.528 115.808 36.552 ;
     RECT  114.617 51.744 115.808 51.768 ;
     RECT  110.704 54.912 115.808 54.936 ;
     RECT  110.704 56.256 115.808 56.28 ;
     RECT  114.793 58.704 115.808 58.728 ;
     RECT  115.283 60.336 115.808 84.552 ;
     RECT  115.808 2.148 115.912 84.552 ;
     RECT  115.285 86.256 116.053 86.28 ;
     RECT  115.912 2.418 116.104 84.552 ;
     RECT  116.053 86.208 116.291 86.28 ;
     RECT  116.104 60.336 116.387 84.552 ;
     RECT  116.291 86.256 116.86 86.28 ;
     RECT  116.387 60.384 117.677 84.408 ;
     RECT  117.677 60.384 117.785 64.248 ;
     RECT  117.677 65.232 117.785 84.408 ;
     RECT  117.785 60.384 118.067 63.24 ;
     RECT  117.785 65.424 118.429 84.408 ;
     RECT  116.104 51.84 118.573 51.864 ;
     RECT  118.429 65.424 118.595 84.984 ;
     RECT  118.573 51.744 118.613 51.864 ;
     RECT  118.595 65.424 118.649 84.312 ;
     RECT  117.785 64.224 118.721 64.248 ;
     RECT  118.897 58.704 119.045 58.728 ;
     RECT  118.649 65.472 119.621 84.312 ;
     RECT  119.621 65.52 119.693 84.312 ;
     RECT  119.693 65.664 119.729 84.312 ;
     RECT  119.729 65.904 119.873 84.312 ;
     RECT  119.873 67.632 120.161 84.312 ;
     RECT  120.161 67.68 120.377 84.312 ;
     RECT  118.067 60.672 120.445 63.24 ;
     RECT  118.613 51.744 120.625 51.768 ;
     RECT  116.104 32.784 120.733 32.808 ;
     RECT  116.104 17.376 120.769 17.4 ;
     RECT  116.104 30.576 120.805 30.6 ;
     RECT  120.733 31.92 120.805 32.808 ;
     RECT  120.661 50.112 121.093 50.136 ;
     RECT  120.625 51.744 121.093 52.728 ;
     RECT  120.517 2.352 121.208 2.376 ;
     RECT  120.661 6.576 121.208 6.6 ;
     RECT  116.104 9.552 121.208 9.576 ;
     RECT  116.104 11.28 121.208 11.304 ;
     RECT  120.121 13.296 121.208 13.32 ;
     RECT  120.517 14.832 121.208 14.856 ;
     RECT  116.104 16.32 121.208 16.344 ;
     RECT  120.769 17.376 121.208 17.64 ;
     RECT  120.445 24.48 121.208 24.504 ;
     RECT  120.085 27.168 121.208 27.192 ;
     RECT  120.805 30.576 121.208 32.808 ;
     RECT  116.104 36.528 121.208 36.552 ;
     RECT  118.261 38.736 121.208 38.76 ;
     RECT  120.733 43.104 121.208 43.128 ;
     RECT  120.445 44.448 121.208 44.472 ;
     RECT  120.985 47.424 121.208 47.448 ;
     RECT  121.093 50.112 121.208 52.728 ;
     RECT  116.104 54.912 121.208 54.936 ;
     RECT  116.104 56.256 121.208 56.28 ;
     RECT  120.445 59.808 121.208 63.24 ;
     RECT  119.873 66.48 121.208 66.504 ;
     RECT  120.377 67.68 121.208 84.252 ;
     RECT  121.208 2.148 121.312 84.252 ;
     RECT  121.312 2.352 121.504 84.252 ;
     RECT  121.504 50.832 121.565 53.592 ;
     RECT  120.469 86.256 121.573 86.28 ;
     RECT  121.504 15.936 121.619 17.64 ;
     RECT  121.565 53.568 121.619 53.592 ;
     RECT  121.619 15.936 121.645 17.4 ;
     RECT  121.504 13.296 121.667 14.664 ;
     RECT  121.504 27.168 121.667 28.152 ;
     RECT  121.504 29.712 121.667 31.32 ;
     RECT  121.504 36.336 121.673 36.552 ;
     RECT  121.504 44.304 121.673 44.472 ;
     RECT  121.504 10.8 121.681 12.168 ;
     RECT  121.681 10.8 121.709 11.448 ;
     RECT  121.667 27.6 121.709 28.152 ;
     RECT  121.504 43.104 121.715 43.128 ;
     RECT  121.673 44.304 121.715 44.328 ;
     RECT  121.504 6.576 121.781 6.6 ;
     RECT  121.504 9.36 121.889 9.576 ;
     RECT  121.504 33.936 121.907 33.96 ;
     RECT  121.504 35.04 121.907 35.064 ;
     RECT  121.504 41.76 121.925 41.784 ;
     RECT  121.565 50.832 121.997 51.768 ;
     RECT  121.504 47.184 122.003 49.608 ;
     RECT  122.003 47.184 122.044 47.208 ;
     RECT  122.003 49.584 122.141 49.608 ;
     RECT  121.504 18.672 122.249 18.792 ;
     RECT  121.621 84.912 122.437 84.936 ;
     RECT  121.504 60.624 122.497 61.944 ;
     RECT  122.249 18.768 122.533 18.792 ;
     RECT  121.504 19.92 122.533 20.232 ;
     RECT  121.997 50.928 122.533 51.768 ;
     RECT  121.504 56.256 122.533 56.28 ;
     RECT  121.504 57.984 122.533 58.008 ;
     RECT  122.497 60.624 122.533 62.808 ;
     RECT  121.504 63.792 122.533 63.816 ;
     RECT  122.533 60.624 122.539 63.816 ;
     RECT  122.533 56.256 122.579 58.728 ;
     RECT  121.504 66.48 122.601 83.928 ;
     RECT  121.504 54.72 122.605 54.936 ;
     RECT  122.533 50.928 122.617 52.008 ;
     RECT  121.504 39.792 122.639 40.44 ;
     RECT  122.533 18.768 122.675 20.232 ;
     RECT  121.504 22.992 122.677 23.016 ;
     RECT  121.504 24.48 122.677 24.504 ;
     RECT  121.504 46.128 122.677 46.152 ;
     RECT  122.003 48.24 122.681 48.264 ;
     RECT  122.579 58.128 122.681 58.728 ;
     RECT  121.504 8.064 122.684 8.088 ;
     RECT  122.677 22.992 122.684 24.504 ;
     RECT  121.667 30.576 122.687 31.32 ;
     RECT  122.675 19.392 122.713 20.232 ;
     RECT  122.684 7.776 122.725 8.088 ;
     RECT  121.889 9.36 122.725 9.384 ;
     RECT  121.673 36.336 122.725 36.36 ;
     RECT  122.601 67.728 122.753 83.928 ;
     RECT  122.725 7.776 122.771 9.384 ;
     RECT  122.684 22.704 122.771 24.504 ;
     RECT  121.645 15.936 122.785 16.344 ;
     RECT  121.645 17.376 122.785 17.4 ;
     RECT  122.605 54.048 122.789 54.936 ;
     RECT  122.539 60.672 122.789 63.816 ;
     RECT  121.573 86.208 122.819 86.28 ;
     RECT  122.753 70.032 122.821 83.928 ;
     RECT  122.437 84.912 122.821 85.224 ;
     RECT  122.789 61.776 122.825 63.816 ;
     RECT  122.821 70.032 122.825 85.224 ;
     RECT  121.709 10.992 122.857 11.448 ;
     RECT  122.687 30 122.857 31.32 ;
     RECT  121.504 32.784 122.857 32.808 ;
     RECT  122.771 8.496 122.869 9.384 ;
     RECT  122.857 10.992 122.869 11.544 ;
     RECT  122.677 46.128 122.869 46.2 ;
     RECT  121.504 4.32 122.893 4.344 ;
     RECT  122.771 24.48 122.897 24.504 ;
     RECT  121.709 27.6 122.897 27.624 ;
     RECT  122.857 30 122.897 32.808 ;
     RECT  122.869 8.496 122.915 11.544 ;
     RECT  122.725 35.616 122.915 36.36 ;
     RECT  122.639 39.792 122.915 41.064 ;
     RECT  122.869 46.128 122.915 46.296 ;
     RECT  121.504 38.736 122.924 38.76 ;
     RECT  122.915 39.792 122.924 40.44 ;
     RECT  122.825 70.272 122.933 85.224 ;
     RECT  122.785 15.936 122.969 17.4 ;
     RECT  122.924 38.736 123.011 40.44 ;
     RECT  122.915 46.176 123.011 46.296 ;
     RECT  122.617 50.928 123.011 51.768 ;
     RECT  123.011 50.928 123.037 50.952 ;
     RECT  123.037 50.736 123.061 50.952 ;
     RECT  122.713 19.392 123.073 20.52 ;
     RECT  123.061 50.448 123.077 50.952 ;
     RECT  122.915 36.336 123.081 36.36 ;
     RECT  122.915 8.496 123.107 8.664 ;
     RECT  122.965 24.816 123.107 24.84 ;
     RECT  122.897 30 123.107 30.6 ;
     RECT  122.933 70.848 123.109 85.224 ;
     RECT  122.819 86.208 123.109 86.232 ;
     RECT  122.893 3.408 123.121 4.536 ;
     RECT  123.077 50.448 123.121 50.76 ;
     RECT  122.937 41.568 123.145 41.592 ;
     RECT  121.667 13.776 123.153 13.992 ;
     RECT  123.081 36.336 123.155 37.032 ;
     RECT  123.153 13.776 123.164 14.232 ;
     RECT  123.164 13.056 123.205 14.232 ;
     RECT  123.145 41.568 123.229 42.168 ;
     RECT  123.205 12.528 123.251 14.232 ;
     RECT  122.897 31.872 123.253 32.808 ;
     RECT  123.073 19.392 123.293 21.144 ;
     RECT  122.579 56.256 123.308 57.048 ;
     RECT  121.504 2.352 123.329 2.376 ;
     RECT  122.753 67.728 123.347 69 ;
     RECT  122.713 43.296 123.349 43.32 ;
     RECT  122.789 54.048 123.395 54.168 ;
     RECT  123.109 70.848 123.395 86.232 ;
     RECT  122.915 10.32 123.401 11.544 ;
     RECT  123.107 30.576 123.437 30.6 ;
     RECT  123.349 43.296 123.437 44.088 ;
     RECT  123.437 43.296 123.445 43.944 ;
     RECT  123.445 42.72 123.491 43.944 ;
     RECT  123.121 3.408 123.509 3.432 ;
     RECT  122.969 15.936 123.509 17.112 ;
     RECT  123.011 38.736 123.577 38.808 ;
     RECT  123.577 38.16 123.617 38.808 ;
     RECT  122.601 66.48 123.685 66.504 ;
     RECT  123.347 67.728 123.685 68.184 ;
     RECT  123.491 42.72 123.689 42.744 ;
     RECT  123.395 70.848 123.689 85.224 ;
     RECT  123.308 56.16 123.725 57.048 ;
     RECT  123.685 65.52 123.731 68.184 ;
     RECT  123.617 38.16 123.761 38.76 ;
     RECT  123.121 4.512 123.833 4.536 ;
     RECT  123.509 16.32 123.833 17.112 ;
     RECT  123.293 21.024 123.905 21.144 ;
     RECT  122.681 58.128 123.973 58.152 ;
     RECT  122.789 60.672 123.973 60.696 ;
     RECT  122.825 61.776 123.973 62.856 ;
     RECT  123.293 19.392 123.98 19.416 ;
     RECT  123.973 58.128 124.013 58.536 ;
     RECT  123.229 41.568 124.049 41.592 ;
     RECT  123.937 18.192 124.067 18.216 ;
     RECT  123.98 19.248 124.067 19.416 ;
     RECT  123.253 31.872 124.076 33.288 ;
     RECT  123.731 65.52 124.085 67.176 ;
     RECT  124.076 31.872 124.117 34.104 ;
     RECT  123.973 60.672 124.117 62.856 ;
     RECT  122.569 26.592 124.157 26.616 ;
     RECT  123.689 71.088 124.157 85.224 ;
     RECT  124.117 31.872 124.163 34.776 ;
     RECT  123.251 12.528 124.193 12.552 ;
     RECT  123.761 38.16 124.193 38.184 ;
     RECT  124.117 60.672 124.211 63.24 ;
     RECT  124.163 34.752 124.213 34.776 ;
     RECT  123.155 37.008 124.229 37.032 ;
     RECT  123.121 50.448 124.229 50.472 ;
     RECT  124.211 60.672 124.229 62.664 ;
     RECT  123.251 14.208 124.259 14.232 ;
     RECT  124.213 34.752 124.259 35.352 ;
     RECT  124.085 65.52 124.259 65.544 ;
     RECT  124.213 15.312 124.3 15.336 ;
     RECT  123.833 16.32 124.301 16.536 ;
     RECT  124.067 19.392 124.301 19.416 ;
     RECT  123.905 21.024 124.301 21.048 ;
     RECT  124.259 35.328 124.301 35.352 ;
     RECT  123.011 39.792 124.301 39.912 ;
     RECT  123.401 11.28 124.373 11.544 ;
     RECT  124.301 39.792 124.409 39.816 ;
     RECT  123.011 46.272 124.477 46.296 ;
     RECT  124.301 16.32 124.481 16.344 ;
     RECT  124.373 11.28 124.517 11.304 ;
     RECT  124.163 31.872 124.517 33.048 ;
     RECT  124.477 46.176 124.517 46.296 ;
     RECT  124.517 31.872 124.625 32.808 ;
     RECT  124.229 60.672 124.697 60.696 ;
     RECT  123.109 6.24 124.721 6.264 ;
     RECT  124.721 5.712 124.805 6.264 ;
     RECT  123.725 56.16 124.805 56.184 ;
     RECT  124.741 4.272 124.828 4.296 ;
     RECT  124.517 46.176 124.835 46.2 ;
     RECT  123.491 43.92 124.869 43.944 ;
     RECT  123.107 8.496 124.883 8.52 ;
     RECT  123.395 54.144 124.913 54.168 ;
     RECT  124.085 67.152 124.913 67.176 ;
     RECT  124.837 7.392 124.949 7.416 ;
     RECT  124.625 31.872 124.949 31.896 ;
     RECT  124.789 45.12 124.949 45.144 ;
     RECT  124.013 58.512 124.981 58.536 ;
     RECT  124.837 9.696 125.021 9.72 ;
     RECT  124.229 61.872 125.021 62.664 ;
     RECT  124.981 57.552 125.027 58.536 ;
     RECT  124.945 59.856 125.029 59.88 ;
     RECT  123.731 68.16 125.057 68.184 ;
     RECT  124.157 71.136 125.077 85.224 ;
     RECT  123.395 86.208 125.077 86.232 ;
     RECT  125.077 71.136 125.165 86.232 ;
     RECT  125.027 57.552 125.273 57.576 ;
     RECT  125.021 62.64 125.273 62.664 ;
     RECT  124.657 64.368 125.345 64.392 ;
     RECT  125.165 71.232 125.797 86.232 ;
     RECT  125.797 71.232 126.608 86.28 ;
     RECT  126.608 2.148 126.904 86.28 ;
     RECT  125.953 0.48 127.141 0.504 ;
     RECT  126.904 73.488 127.289 86.28 ;
     RECT  127.289 73.488 127.475 86.232 ;
     RECT  127.141 0.48 127.645 1.176 ;
     RECT  127.475 73.488 128.041 77.112 ;
     RECT  126.904 35.952 128.077 35.976 ;
     RECT  126.904 60.24 128.113 60.264 ;
     RECT  126.904 4.896 128.185 4.92 ;
     RECT  126.904 46.752 128.185 46.776 ;
     RECT  128.077 51.12 128.185 51.144 ;
     RECT  126.904 58.224 128.185 58.248 ;
     RECT  127.645 0.48 128.221 1.512 ;
     RECT  128.185 4.224 128.221 4.92 ;
     RECT  126.904 19.056 128.221 19.08 ;
     RECT  128.185 23.088 128.221 23.112 ;
     RECT  128.113 25.488 128.221 25.512 ;
     RECT  128.185 26.832 128.221 26.856 ;
     RECT  128.185 28.512 128.221 28.536 ;
     RECT  128.077 35.28 128.221 35.976 ;
     RECT  128.185 37.296 128.221 37.32 ;
     RECT  128.185 39.984 128.221 40.008 ;
     RECT  126.904 43.008 128.221 43.032 ;
     RECT  128.185 46.752 128.221 47.112 ;
     RECT  126.904 49.776 128.221 49.8 ;
     RECT  126.904 54.816 128.221 54.84 ;
     RECT  128.185 57.552 128.221 58.248 ;
     RECT  128.077 59.232 128.221 59.256 ;
     RECT  128.113 60.24 128.221 60.6 ;
     RECT  126.904 61.584 128.221 61.608 ;
     RECT  126.904 63.264 128.221 63.288 ;
     RECT  128.185 64.272 128.221 64.296 ;
     RECT  128.041 73.056 128.221 77.112 ;
     RECT  128.221 10.272 128.257 10.296 ;
     RECT  128.221 11.952 128.257 12.312 ;
     RECT  128.221 17.376 128.257 19.08 ;
     RECT  128.221 46.752 128.257 47.448 ;
     RECT  128.221 48.432 128.257 49.8 ;
     RECT  128.221 68.688 128.257 68.712 ;
     RECT  128.221 70.032 128.257 70.056 ;
     RECT  128.185 71.712 128.257 71.736 ;
     RECT  128.221 72.72 128.257 77.112 ;
     RECT  128.185 50.784 128.329 51.144 ;
     RECT  128.221 20.4 128.761 20.424 ;
     RECT  128.221 22.752 128.761 23.112 ;
     RECT  128.221 25.152 128.761 25.512 ;
     RECT  128.221 26.832 128.761 28.536 ;
     RECT  128.329 29.856 128.761 29.88 ;
     RECT  128.221 30.864 128.761 30.888 ;
     RECT  128.221 32.88 128.761 33.24 ;
     RECT  128.221 34.224 128.761 37.32 ;
     RECT  128.221 56.496 128.761 60.6 ;
     RECT  128.221 61.584 128.761 63.288 ;
     RECT  128.221 64.272 128.761 64.632 ;
     RECT  128.257 68.688 128.761 70.056 ;
     RECT  128.221 0.144 128.797 1.512 ;
     RECT  128.221 3.552 128.797 5.592 ;
     RECT  126.904 6.576 128.797 6.6 ;
     RECT  128.221 7.584 128.797 7.608 ;
     RECT  126.904 8.928 128.797 8.952 ;
     RECT  128.257 10.272 128.797 10.632 ;
     RECT  128.257 11.616 128.797 12.312 ;
     RECT  128.221 13.296 128.797 13.32 ;
     RECT  128.221 14.352 128.797 14.712 ;
     RECT  126.904 16.032 128.797 16.056 ;
     RECT  128.257 17.04 128.797 19.08 ;
     RECT  128.761 20.064 128.797 20.424 ;
     RECT  128.221 21.408 128.797 21.432 ;
     RECT  128.761 22.416 128.797 23.112 ;
     RECT  128.761 25.152 128.797 28.536 ;
     RECT  128.761 29.856 128.797 30.888 ;
     RECT  128.761 32.208 128.797 37.32 ;
     RECT  128.221 39.312 128.797 40.008 ;
     RECT  128.221 42.336 128.797 43.032 ;
     RECT  126.904 44.016 128.797 44.712 ;
     RECT  128.257 46.752 128.797 49.8 ;
     RECT  128.329 50.784 128.797 51.48 ;
     RECT  128.761 52.464 128.797 52.488 ;
     RECT  126.904 53.472 128.797 53.496 ;
     RECT  128.221 54.816 128.797 55.512 ;
     RECT  128.761 56.496 128.797 64.632 ;
     RECT  128.257 65.616 128.797 65.64 ;
     RECT  128.221 66.624 128.797 67.32 ;
     RECT  128.761 68.352 128.797 70.056 ;
     RECT  128.257 71.04 128.797 77.112 ;
     RECT  128.797 3.552 128.833 77.112 ;
     RECT  127.475 78.096 128.833 86.232 ;
     RECT  128.833 3.552 129.409 86.232 ;
     RECT  128.797 0.144 129.445 2.184 ;
     RECT  129.409 3.216 129.445 86.232 ;
     RECT  129.445 0.144 129.564 86.232 ;
    LAYER M5 ;
     RECT  2.4 2.137 2.52 2.151 ;
     RECT  7.8 2.137 7.92 2.151 ;
     RECT  13.2 2.137 13.32 2.151 ;
     RECT  18.6 2.137 18.72 2.151 ;
     RECT  24 2.137 24.12 2.151 ;
     RECT  29.4 2.137 29.52 2.151 ;
     RECT  34.8 2.137 34.92 2.151 ;
     RECT  40.2 2.137 40.32 2.151 ;
     RECT  45.6 2.137 45.72 2.151 ;
     RECT  51 2.137 51.12 2.151 ;
     RECT  56.4 2.137 56.52 2.151 ;
     RECT  61.8 2.137 61.92 2.151 ;
     RECT  67.2 2.137 67.32 2.151 ;
     RECT  72.6 2.137 72.72 2.151 ;
     RECT  78 2.137 78.12 2.151 ;
     RECT  83.4 2.137 83.52 2.151 ;
     RECT  88.8 2.137 88.92 2.151 ;
     RECT  94.2 2.137 94.32 2.151 ;
     RECT  99.6 2.137 99.72 2.151 ;
     RECT  105 2.137 105.12 2.151 ;
     RECT  110.4 2.137 110.52 2.151 ;
     RECT  115.8 2.137 115.92 2.151 ;
     RECT  121.2 2.137 121.32 2.151 ;
     RECT  126.6 2.137 126.72 2.151 ;
     RECT  124.752 4.261 124.776 5.747 ;
     RECT  121.2 2.151 121.512 6.565 ;
     RECT  123.072 3.925 123.096 7.765 ;
     RECT  121.2 6.565 121.608 8.099 ;
     RECT  122.736 7.765 123.096 8.531 ;
     RECT  122.784 8.531 123.096 8.675 ;
     RECT  115.8 2.151 116.112 9.541 ;
     RECT  124.848 7.381 124.872 9.731 ;
     RECT  121.2 8.099 121.512 10.789 ;
     RECT  122.784 8.675 122.904 10.835 ;
     RECT  99.6 2.151 99.912 11.269 ;
     RECT  122.784 10.835 122.808 12.517 ;
     RECT  121.2 10.789 121.656 13.765 ;
     RECT  122.784 12.517 123.24 13.765 ;
     RECT  121.2 13.765 123.24 14.243 ;
     RECT  121.2 14.243 122.568 14.675 ;
     RECT  121.2 14.675 121.512 16.501 ;
     RECT  122.544 14.675 122.568 16.501 ;
     RECT  124.224 14.197 124.248 16.547 ;
     RECT  113.664 16.309 113.688 17.365 ;
     RECT  121.2 16.501 122.568 18.707 ;
     RECT  122.544 18.707 122.568 18.757 ;
     RECT  124.032 18.181 124.056 19.427 ;
     RECT  122.544 18.757 122.664 19.669 ;
     RECT  121.2 18.707 121.512 19.909 ;
     RECT  122.544 19.669 123 19.909 ;
     RECT  121.2 19.909 123 24.805 ;
     RECT  121.2 24.805 123.096 30.035 ;
     RECT  99.6 11.269 100.584 30.565 ;
     RECT  121.2 30.035 122.76 31.237 ;
     RECT  2.4 2.151 2.712 31.285 ;
     RECT  120.816 31.237 122.76 31.955 ;
     RECT  4.896 31.861 4.92 33.589 ;
     RECT  124.128 33.013 124.152 34.115 ;
     RECT  4.752 33.589 4.92 34.931 ;
     RECT  124.224 34.741 124.248 35.363 ;
     RECT  121.2 31.955 122.76 35.605 ;
     RECT  121.2 35.605 122.904 36.325 ;
     RECT  105 2.151 105.312 36.517 ;
     RECT  121.2 36.325 123.144 37.043 ;
     RECT  121.2 37.043 122.904 38.773 ;
     RECT  121.2 38.773 123 42.133 ;
     RECT  121.2 42.133 123.192 42.709 ;
     RECT  121.2 42.709 123.48 43.331 ;
     RECT  0.192 10.789 0.216 43.379 ;
     RECT  121.2 43.331 123.384 44.099 ;
     RECT  124.8 43.909 124.824 46.211 ;
     RECT  121.2 44.099 123.192 50.101 ;
     RECT  64.368 43.861 64.392 51.253 ;
     RECT  88.8 2.151 89.112 51.253 ;
     RECT  64.08 51.253 64.392 51.299 ;
     RECT  121.104 50.101 123.192 51.395 ;
     RECT  88.8 51.253 89.976 53.509 ;
     RECT  121.2 51.395 123.192 54.037 ;
     RECT  2.4 31.285 3.384 54.661 ;
     RECT  99.408 30.565 100.584 54.901 ;
     RECT  121.2 54.037 123.384 56.195 ;
     RECT  110.4 2.151 110.712 56.245 ;
     RECT  4.752 34.931 4.776 58.163 ;
     RECT  88.08 53.509 89.976 59.509 ;
     RECT  64.08 51.299 64.104 59.555 ;
     RECT  121.2 56.195 123.192 59.797 ;
     RECT  124.992 57.541 125.016 59.891 ;
     RECT  104.88 36.517 105.312 60.373 ;
     RECT  113.664 17.365 114.264 60.373 ;
     RECT  118.272 38.725 118.296 60.373 ;
     RECT  120.816 59.797 123.192 60.563 ;
     RECT  99.36 54.901 100.584 60.805 ;
     RECT  104.208 60.373 105.312 60.901 ;
     RECT  96.72 60.853 96.744 60.949 ;
     RECT  96.288 60.949 96.744 60.995 ;
     RECT  121.2 60.563 123.192 61.237 ;
     RECT  110.4 56.245 110.904 61.861 ;
     RECT  115.8 9.541 116.568 62.485 ;
     RECT  92.592 54.565 92.616 62.533 ;
     RECT  92.592 62.533 92.952 62.677 ;
     RECT  96.288 60.995 96.312 62.677 ;
     RECT  83.4 2.151 83.712 62.725 ;
     RECT  96.288 62.677 97.128 62.917 ;
     RECT  92.016 62.677 92.952 63.013 ;
     RECT  103.776 60.901 105.312 63.061 ;
     RECT  106.608 60.805 106.632 63.157 ;
     RECT  121.2 61.237 124.008 63.205 ;
     RECT  96.288 62.917 97.176 63.253 ;
     RECT  98.592 60.805 100.584 63.301 ;
     RECT  115.344 62.485 116.568 63.349 ;
     RECT  98.592 63.301 100.92 63.397 ;
     RECT  102.288 62.773 102.312 63.397 ;
     RECT  91.728 63.013 92.952 63.445 ;
     RECT  110.4 61.861 111.384 63.541 ;
     RECT  106.608 63.157 106.872 63.589 ;
     RECT  91.728 63.445 93.096 63.683 ;
     RECT  110.016 63.541 111.384 63.683 ;
     RECT  103.68 63.061 105.312 63.685 ;
     RECT  98.592 63.397 102.312 63.731 ;
     RECT  88.08 59.509 90.264 63.781 ;
     RECT  94.2 2.151 94.512 63.781 ;
     RECT  98.592 63.731 101.256 63.781 ;
     RECT  103.488 63.685 105.312 63.781 ;
     RECT  96.288 63.253 97.464 63.827 ;
     RECT  94.08 63.781 94.632 63.877 ;
     RECT  103.488 63.781 105.432 63.925 ;
     RECT  110.304 63.683 111.384 63.973 ;
     RECT  94.08 63.877 95.208 64.067 ;
     RECT  113.376 60.373 114.264 64.069 ;
     RECT  110.304 63.973 111.912 64.115 ;
     RECT  53.424 59.797 53.448 64.165 ;
     RECT  98.544 63.781 101.256 64.211 ;
     RECT  20.88 62.965 20.904 64.309 ;
     RECT  103.488 63.925 105.48 64.309 ;
     RECT  106.464 63.589 106.872 64.309 ;
     RECT  98.544 64.211 101.016 64.357 ;
     RECT  102.288 63.731 102.312 64.357 ;
     RECT  103.488 64.309 106.872 64.357 ;
     RECT  115.344 63.349 116.856 64.357 ;
     RECT  98.496 64.357 101.016 64.403 ;
     RECT  102.288 64.357 106.872 64.499 ;
     RECT  20.88 64.309 21.192 64.693 ;
     RECT  96.288 63.827 97.416 64.789 ;
     RECT  96 64.789 97.416 64.931 ;
     RECT  98.496 64.403 100.584 64.933 ;
     RECT  108.72 51.637 108.744 64.933 ;
     RECT  112.992 64.069 114.264 64.933 ;
     RECT  96.144 64.931 97.416 65.075 ;
     RECT  92.352 63.683 93.096 65.077 ;
     RECT  94.08 64.067 94.92 65.077 ;
     RECT  112.752 64.933 114.264 65.123 ;
     RECT  85.392 64.933 85.416 65.221 ;
     RECT  88.08 63.781 91.176 65.267 ;
     RECT  108.72 64.933 108.984 65.509 ;
     RECT  121.2 63.205 124.2 65.509 ;
     RECT  92.352 65.077 94.92 65.557 ;
     RECT  98.4 64.933 100.584 65.653 ;
     RECT  115.344 64.357 117 65.653 ;
     RECT  118.032 60.373 118.296 65.653 ;
     RECT  34.8 2.151 35.112 65.749 ;
     RECT  103.488 64.499 106.872 65.797 ;
     RECT  20.88 64.693 21.816 65.941 ;
     RECT  92.352 65.557 95.112 65.941 ;
     RECT  96.144 65.075 97.368 65.941 ;
     RECT  108.72 65.509 109.224 65.941 ;
     RECT  110.304 64.115 111.384 65.941 ;
     RECT  83.28 62.725 83.712 66.037 ;
     RECT  92.352 65.941 97.368 66.083 ;
     RECT  92.352 66.083 95.112 66.131 ;
     RECT  96.24 66.083 97.368 66.179 ;
     RECT  103.488 65.797 107.352 66.181 ;
     RECT  108.72 65.941 111.384 66.181 ;
     RECT  98.4 65.653 101.016 66.277 ;
     RECT  119.664 66.085 119.688 66.373 ;
     RECT  88.08 65.267 90.936 66.613 ;
     RECT  87.744 66.613 90.936 66.709 ;
     RECT  98.4 66.277 101.064 66.709 ;
     RECT  87.744 66.709 91.368 66.757 ;
     RECT  92.352 66.131 94.92 66.757 ;
     RECT  103.488 66.181 111.384 66.803 ;
     RECT  20.88 65.941 22.632 66.997 ;
     RECT  121.2 65.509 124.248 67.187 ;
     RECT  87.744 66.757 94.92 67.189 ;
     RECT  96.24 66.179 96.984 67.189 ;
     RECT  112.8 65.123 114.264 67.381 ;
     RECT  96.24 67.189 97.08 67.477 ;
     RECT  115.344 65.653 118.296 67.477 ;
     RECT  119.424 66.373 119.688 67.477 ;
     RECT  36.288 63.205 36.312 67.525 ;
     RECT  96.24 67.477 97.272 67.669 ;
     RECT  102.288 64.499 102.408 67.669 ;
     RECT  103.488 66.803 107.736 67.669 ;
     RECT  96.048 67.669 97.272 67.717 ;
     RECT  87.456 67.189 94.92 67.909 ;
     RECT  102.288 67.669 107.736 67.909 ;
     RECT  108.72 66.803 109.224 67.909 ;
     RECT  112.704 67.381 114.264 67.909 ;
     RECT  115.344 67.477 119.688 67.909 ;
     RECT  67.2 2.151 67.512 67.957 ;
     RECT  87.456 67.909 95.016 68.005 ;
     RECT  96.048 67.717 97.368 68.005 ;
     RECT  98.4 66.709 101.112 68.005 ;
     RECT  102.288 67.909 109.224 68.005 ;
     RECT  110.304 66.803 111.384 68.005 ;
     RECT  87.456 68.005 101.112 68.053 ;
     RECT  102.288 68.005 111.384 68.053 ;
     RECT  87.456 68.053 111.384 68.147 ;
     RECT  96.048 68.147 111.384 68.195 ;
     RECT  112.704 67.909 119.688 68.245 ;
     RECT  108.72 68.195 111.384 68.389 ;
     RECT  112.704 68.245 119.736 68.389 ;
     RECT  87.456 68.147 94.92 68.531 ;
     RECT  108.72 68.389 119.736 68.579 ;
     RECT  96.048 68.195 107.736 68.819 ;
     RECT  67.2 67.957 68.136 68.917 ;
     RECT  96.048 68.819 102.456 69.011 ;
     RECT  103.488 68.819 107.736 69.059 ;
     RECT  87.456 68.531 91.656 69.491 ;
     RECT  93.024 68.531 94.92 69.493 ;
     RECT  106.8 69.059 107.736 69.541 ;
     RECT  108.72 68.579 111.672 69.541 ;
     RECT  106.8 69.541 111.672 69.685 ;
     RECT  112.896 68.579 119.736 69.685 ;
     RECT  27.072 35.317 27.096 69.781 ;
     RECT  96.048 69.011 101.976 70.019 ;
     RECT  92.976 69.493 94.92 70.117 ;
     RECT  96.048 70.019 100.968 70.117 ;
     RECT  92.976 70.117 100.968 70.165 ;
     RECT  103.488 69.059 105.768 70.211 ;
     RECT  24 2.151 24.312 70.261 ;
     RECT  92.784 70.165 100.968 70.261 ;
     RECT  104.736 70.211 105.768 70.405 ;
     RECT  106.8 69.685 119.736 70.405 ;
     RECT  85.392 65.221 85.896 70.501 ;
     RECT  87.456 69.491 91.608 70.501 ;
     RECT  85.392 70.501 91.608 70.643 ;
     RECT  104.736 70.405 119.736 70.835 ;
     RECT  13.2 2.151 13.512 70.885 ;
     RECT  103.488 70.211 103.512 70.885 ;
     RECT  92.592 70.261 100.968 71.077 ;
     RECT  101.952 70.019 101.976 71.077 ;
     RECT  104.736 70.835 107.64 71.123 ;
     RECT  108.72 70.835 119.736 71.125 ;
     RECT  4.656 67.813 4.68 71.173 ;
     RECT  10.848 70.885 10.872 71.219 ;
     RECT  13.2 70.885 13.8 71.219 ;
     RECT  72.6 2.151 72.912 71.221 ;
     RECT  126.6 2.151 126.912 71.221 ;
     RECT  103.104 70.885 103.512 71.315 ;
     RECT  40.2 2.151 40.512 71.317 ;
     RECT  92.592 71.077 101.976 71.363 ;
     RECT  93.888 71.363 101.976 71.365 ;
     RECT  103.104 71.315 103.272 71.365 ;
     RECT  40.08 71.317 40.512 71.459 ;
     RECT  72.6 71.221 73.32 71.605 ;
     RECT  108.72 71.125 120.072 71.749 ;
     RECT  121.2 67.187 124.2 71.749 ;
     RECT  104.784 71.123 107.64 71.797 ;
     RECT  125.952 71.221 126.912 71.797 ;
     RECT  93.888 71.365 103.272 72.131 ;
     RECT  95.952 72.131 103.272 72.277 ;
     RECT  108.72 71.749 124.2 72.277 ;
     RECT  108.72 72.277 124.68 72.325 ;
     RECT  125.712 71.797 126.912 72.325 ;
     RECT  104.784 71.797 107.736 72.373 ;
     RECT  108.72 72.325 126.912 72.373 ;
     RECT  95.952 72.277 103.8 72.517 ;
     RECT  104.784 72.373 126.912 72.517 ;
     RECT  85.392 70.643 85.896 72.613 ;
     RECT  92.592 71.363 92.808 72.613 ;
     RECT  93.888 72.131 94.92 72.613 ;
     RECT  6.336 58.645 6.36 72.755 ;
     RECT  95.952 72.517 126.912 73.477 ;
     RECT  92.592 72.613 94.92 73.765 ;
     RECT  95.952 73.477 127.32 73.765 ;
     RECT  2.4 54.661 3.672 73.909 ;
     RECT  4.656 71.173 5.064 73.909 ;
     RECT  87.456 70.643 91.608 73.909 ;
     RECT  92.592 73.765 127.32 73.909 ;
     RECT  48.432 73.573 48.456 73.957 ;
     RECT  15.648 70.549 15.672 74.147 ;
     RECT  87.456 73.909 127.32 74.147 ;
     RECT  87.456 74.147 113.304 74.243 ;
     RECT  87.456 74.243 107.016 74.581 ;
     RECT  114.336 74.147 127.32 74.581 ;
     RECT  2.4 73.909 5.064 74.675 ;
     RECT  18.6 2.151 18.912 75.397 ;
     RECT  53.424 64.165 53.832 75.637 ;
     RECT  86.976 74.581 107.016 75.637 ;
     RECT  108 74.243 113.304 75.637 ;
     RECT  86.976 75.637 113.304 75.733 ;
     RECT  114.336 74.581 127.416 75.733 ;
     RECT  4.32 74.675 5.064 75.875 ;
     RECT  34.656 65.749 35.112 76.021 ;
     RECT  11.808 73.237 11.832 76.213 ;
     RECT  13.2 71.219 13.512 76.213 ;
     RECT  51 2.151 51.312 76.453 ;
     RECT  11.808 76.213 13.512 76.501 ;
     RECT  14.736 75.397 14.76 76.501 ;
     RECT  51 76.453 51.864 76.979 ;
     RECT  10.608 73.813 10.632 77.269 ;
     RECT  34.656 76.021 35.208 77.317 ;
     RECT  36.288 67.525 37.176 77.317 ;
     RECT  45.6 2.151 45.912 77.365 ;
     RECT  47.616 73.957 48.456 77.555 ;
     RECT  4.32 75.875 5.016 77.843 ;
     RECT  69.12 68.725 69.144 77.845 ;
     RECT  42.624 74.053 42.648 77.893 ;
     RECT  4.512 77.843 5.016 77.941 ;
     RECT  6.192 76.069 6.216 77.941 ;
     RECT  86.976 75.733 127.416 77.941 ;
     RECT  17.712 75.397 18.912 77.989 ;
     RECT  20.208 66.997 22.632 77.989 ;
     RECT  61.8 2.151 62.112 77.989 ;
     RECT  45.6 77.365 46.392 78.181 ;
     RECT  16.08 74.341 16.104 78.421 ;
     RECT  17.712 77.989 22.632 78.515 ;
     RECT  83.232 66.037 83.712 78.517 ;
     RECT  86.976 77.941 127.464 78.613 ;
     RECT  11.808 76.501 14.76 78.707 ;
     RECT  16.08 78.421 16.68 78.707 ;
     RECT  45.36 78.181 46.392 78.709 ;
     RECT  47.616 77.555 48.072 78.709 ;
     RECT  83.232 78.517 83.832 78.709 ;
     RECT  84.816 72.613 85.896 78.709 ;
     RECT  86.976 78.613 127.992 78.755 ;
     RECT  26.736 69.781 27.096 78.947 ;
     RECT  7.8 2.151 8.112 78.997 ;
     RECT  2.4 74.675 3.336 79.045 ;
     RECT  2.4 79.045 3.432 79.093 ;
     RECT  4.512 77.941 6.216 79.093 ;
     RECT  2.4 79.093 6.216 79.141 ;
     RECT  61.8 77.989 62.568 79.189 ;
     RECT  78 2.151 78.312 79.237 ;
     RECT  60.96 79.189 62.568 79.333 ;
     RECT  86.976 78.755 89.976 79.765 ;
     RECT  91.104 78.755 127.992 79.765 ;
     RECT  78 79.237 78.744 79.957 ;
     RECT  29.4 2.151 29.712 80.005 ;
     RECT  45.36 78.709 48.072 80.053 ;
     RECT  7.68 78.997 8.112 80.101 ;
     RECT  29.4 80.005 30.216 80.101 ;
     RECT  2.304 79.141 6.216 80.245 ;
     RECT  7.392 80.101 8.112 80.245 ;
     RECT  16.08 78.707 16.584 80.245 ;
     RECT  26.736 78.947 26.76 80.245 ;
     RECT  16.08 80.245 16.68 80.293 ;
     RECT  17.712 78.515 18.912 80.293 ;
     RECT  20.208 78.515 22.632 80.293 ;
     RECT  86.976 79.765 127.992 80.341 ;
     RECT  83.232 78.709 85.896 80.435 ;
     RECT  16.08 80.293 22.632 80.533 ;
     RECT  1.104 79.045 1.128 80.629 ;
     RECT  10.128 77.269 10.632 80.629 ;
     RECT  11.808 78.707 14.664 80.629 ;
     RECT  2.304 80.245 8.112 80.677 ;
     RECT  10.128 80.629 10.728 80.677 ;
     RECT  11.808 80.629 14.808 80.677 ;
     RECT  16.08 80.533 22.776 80.677 ;
     RECT  33.024 79.765 33.048 80.677 ;
     RECT  76.32 77.605 76.344 80.725 ;
     RECT  10.128 80.677 10.824 80.773 ;
     RECT  28.464 80.101 30.216 80.773 ;
     RECT  33.024 80.677 33.576 80.821 ;
     RECT  34.656 77.317 37.176 80.821 ;
     RECT  9.936 80.773 10.824 80.869 ;
     RECT  11.808 80.677 22.776 80.869 ;
     RECT  80.928 80.485 80.952 80.869 ;
     RECT  81.936 75.445 81.96 80.869 ;
     RECT  83.232 80.435 84.84 80.869 ;
     RECT  2.16 80.677 8.952 80.917 ;
     RECT  9.936 80.869 22.776 80.917 ;
     RECT  26.736 80.245 27.336 80.917 ;
     RECT  28.464 80.773 30.936 80.917 ;
     RECT  53.424 75.637 54.6 80.917 ;
     RECT  72.144 71.605 73.32 80.917 ;
     RECT  76.32 80.725 76.68 80.917 ;
     RECT  78 79.957 79.224 80.917 ;
     RECT  28.464 80.917 31.8 80.963 ;
     RECT  42.624 77.893 43.128 80.963 ;
     RECT  58.08 77.797 58.104 80.963 ;
     RECT  60.96 79.333 63 80.963 ;
     RECT  85.872 80.435 85.896 81.011 ;
     RECT  69.12 77.845 70.008 81.059 ;
     RECT  39.024 59.461 39.048 81.109 ;
     RECT  45.36 80.053 48.456 81.109 ;
     RECT  72.144 80.917 73.416 81.109 ;
     RECT  38.784 81.109 39.048 81.205 ;
     RECT  56.4 2.151 56.712 81.205 ;
     RECT  76.32 80.917 79.224 81.205 ;
     RECT  38.352 81.205 39.048 81.301 ;
     RECT  40.2 71.459 40.512 81.301 ;
     RECT  45.36 81.109 49.032 81.301 ;
     RECT  51 76.979 51.312 81.301 ;
     RECT  61.536 80.963 63 81.301 ;
     RECT  67.056 68.917 68.136 81.301 ;
     RECT  69.12 81.059 69.528 81.301 ;
     RECT  75.408 81.205 79.224 81.301 ;
     RECT  86.976 80.341 128.232 81.301 ;
     RECT  24 70.261 24.984 81.349 ;
     RECT  26.064 80.917 27.336 81.349 ;
     RECT  33.024 80.821 37.176 81.349 ;
     RECT  38.352 81.301 40.512 81.349 ;
     RECT  72.144 81.109 73.512 81.349 ;
     RECT  75.024 81.301 79.224 81.349 ;
     RECT  80.928 80.869 84.84 81.349 ;
     RECT  72.144 81.349 79.224 81.395 ;
     RECT  23.904 81.349 24.984 81.397 ;
     RECT  26.064 81.349 27.384 81.397 ;
     RECT  28.944 80.963 31.8 81.397 ;
     RECT  33.024 81.349 40.512 81.397 ;
     RECT  41.52 81.301 41.544 81.397 ;
     RECT  52.896 80.917 54.6 81.397 ;
     RECT  55.776 81.205 57.336 81.397 ;
     RECT  0.384 80.629 1.128 81.445 ;
     RECT  2.16 80.917 22.776 81.445 ;
     RECT  28.944 81.397 31.896 81.445 ;
     RECT  33.024 81.397 41.592 81.445 ;
     RECT  80.784 81.349 84.84 81.493 ;
     RECT  23.904 81.397 27.384 81.539 ;
     RECT  28.944 81.445 41.592 81.539 ;
     RECT  67.056 81.301 69.528 81.539 ;
     RECT  71.04 77.653 71.064 81.539 ;
     RECT  72.144 81.395 72.912 81.539 ;
     RECT  50.688 81.301 51.312 81.589 ;
     RECT  73.968 81.395 79.224 81.685 ;
     RECT  45.36 81.301 49.56 81.733 ;
     RECT  50.688 81.589 51.48 81.733 ;
     RECT  58.416 81.301 59.736 81.733 ;
     RECT  73.968 81.685 79.704 81.779 ;
     RECT  50.688 81.733 51.816 81.925 ;
     RECT  52.896 81.397 57.336 81.925 ;
     RECT  80.784 81.493 85.08 81.973 ;
     RECT  64.368 81.781 64.392 82.021 ;
     RECT  23.904 81.539 24.504 82.115 ;
     RECT  45.36 81.733 49.704 82.115 ;
     RECT  48.432 82.115 49.704 82.309 ;
     RECT  50.688 81.925 57.336 82.309 ;
     RECT  48.432 82.309 57.336 82.355 ;
     RECT  80.784 81.973 85.32 82.357 ;
     RECT  86.64 81.301 128.232 82.453 ;
     RECT  28.944 81.539 33.576 82.549 ;
     RECT  34.8 81.539 41.592 82.549 ;
     RECT  58.416 81.733 60.36 82.597 ;
     RECT  86.64 82.453 128.856 82.597 ;
     RECT  56.304 82.355 57.336 82.645 ;
     RECT  58.416 82.597 60.408 82.645 ;
     RECT  43.104 80.963 43.128 82.691 ;
     RECT  45.36 82.115 46.92 82.691 ;
     RECT  48.432 82.355 55.272 82.691 ;
     RECT  86.64 82.597 129.48 82.691 ;
     RECT  0.384 81.445 22.776 82.787 ;
     RECT  28.944 82.549 41.592 82.883 ;
     RECT  45.408 82.691 46.776 83.075 ;
     RECT  64.368 82.021 65.16 83.125 ;
     RECT  64.368 83.125 65.208 83.173 ;
     RECT  72.384 81.539 72.912 83.173 ;
     RECT  73.968 81.779 78.6 83.173 ;
     RECT  80.784 82.357 85.464 83.173 ;
     RECT  86.64 82.691 86.904 83.173 ;
     RECT  25.632 81.539 27.384 83.267 ;
     RECT  28.944 82.883 31.032 83.267 ;
     RECT  32.256 82.883 41.592 83.267 ;
     RECT  56.304 82.645 60.408 83.267 ;
     RECT  0.384 82.787 17.112 83.315 ;
     RECT  39.6 83.267 41.544 83.363 ;
     RECT  80.784 83.173 86.904 83.653 ;
     RECT  87.936 82.691 129.48 83.653 ;
     RECT  0.384 83.315 9.528 83.749 ;
     RECT  18.288 82.787 22.776 83.797 ;
     RECT  24 82.115 24.504 83.797 ;
     RECT  44.16 83.173 44.184 83.797 ;
     RECT  45.408 83.075 46.728 83.797 ;
     RECT  48.768 82.691 55.272 83.797 ;
     RECT  56.304 83.267 59.064 83.797 ;
     RECT  60.336 83.267 60.408 83.797 ;
     RECT  61.536 81.301 63.336 83.797 ;
     RECT  64.368 83.173 65.688 83.797 ;
     RECT  67.2 81.539 69.528 83.797 ;
     RECT  70.992 83.173 71.016 83.797 ;
     RECT  72.384 83.173 78.6 83.797 ;
     RECT  79.68 81.779 79.704 83.797 ;
     RECT  80.784 83.653 129.48 83.797 ;
     RECT  18.288 83.797 24.504 83.941 ;
     RECT  25.632 83.267 27.24 83.941 ;
     RECT  60.336 83.797 69.528 84.181 ;
     RECT  70.992 83.797 129.48 84.181 ;
     RECT  32.256 83.267 35.88 84.229 ;
     RECT  36.912 83.267 38.616 84.229 ;
     RECT  48.192 83.797 59.064 84.229 ;
     RECT  60.336 84.181 129.48 84.229 ;
     RECT  0.096 83.749 9.528 84.325 ;
     RECT  10.512 83.315 17.112 84.325 ;
     RECT  18.288 83.941 27.24 84.325 ;
     RECT  28.992 83.267 31.032 84.325 ;
     RECT  32.256 84.229 38.616 84.325 ;
     RECT  39.6 83.363 41.352 84.325 ;
     RECT  42.624 83.797 43.176 84.325 ;
     RECT  44.16 83.797 46.728 84.325 ;
     RECT  48.192 84.229 129.48 84.325 ;
     RECT  0.096 84.325 129.48 86.352 ;
     RECT  121.608 6.565 123.072 7.765 ;
     RECT  121.608 7.765 122.736 8.099 ;
     RECT  121.512 8.099 122.736 8.531 ;
     RECT  121.512 8.531 122.784 10.789 ;
     RECT  121.656 10.789 122.784 13.765 ;
     RECT  123.24 14.197 124.224 14.243 ;
     RECT  121.512 14.675 122.544 16.501 ;
     RECT  122.568 18.181 124.032 18.757 ;
     RECT  121.512 18.707 122.544 19.909 ;
     RECT  122.664 18.757 124.032 19.427 ;
     RECT  122.664 19.427 123 19.669 ;
     RECT  3.384 31.861 4.896 33.589 ;
     RECT  122.76 33.013 124.128 34.115 ;
     RECT  3.384 33.589 4.752 54.661 ;
     RECT  122.76 34.115 124.152 34.741 ;
     RECT  122.76 34.741 124.224 35.363 ;
     RECT  122.76 35.363 123.144 35.605 ;
     RECT  122.904 35.605 123.144 36.325 ;
     RECT  123.384 43.331 123.48 43.909 ;
     RECT  123.384 43.909 124.8 44.099 ;
     RECT  3.672 54.661 4.752 58.163 ;
     RECT  6.36 58.645 7.8 72.755 ;
     RECT  39.048 59.461 40.2 71.317 ;
     RECT  116.568 60.373 118.032 63.349 ;
     RECT  105.312 60.805 106.608 63.589 ;
     RECT  114.264 62.485 115.344 67.909 ;
     RECT  92.952 62.533 94.2 63.445 ;
     RECT  97.128 62.677 98.592 62.917 ;
     RECT  102.312 62.773 103.776 63.061 ;
     RECT  97.176 62.917 98.592 63.253 ;
     RECT  90.264 63.013 91.728 63.683 ;
     RECT  102.312 63.061 103.68 63.685 ;
     RECT  35.112 63.205 36.288 76.021 ;
     RECT  97.464 63.253 98.592 63.781 ;
     RECT  100.92 63.301 102.288 63.397 ;
     RECT  116.856 63.349 118.032 64.357 ;
     RECT  93.096 63.445 94.2 63.781 ;
     RECT  108.744 63.541 110.016 63.683 ;
     RECT  105.312 63.589 106.464 63.781 ;
     RECT  90.264 63.683 92.352 63.781 ;
     RECT  108.744 63.683 110.304 64.933 ;
     RECT  102.312 63.685 103.488 64.357 ;
     RECT  101.256 63.731 102.288 64.211 ;
     RECT  91.176 63.781 92.352 65.267 ;
     RECT  93.096 63.781 94.08 65.077 ;
     RECT  97.464 63.781 98.544 63.827 ;
     RECT  105.432 63.781 106.464 63.925 ;
     RECT  97.416 63.827 98.544 64.357 ;
     RECT  95.208 63.877 96.288 64.067 ;
     RECT  105.48 63.925 106.464 64.309 ;
     RECT  111.912 63.973 113.376 64.069 ;
     RECT  94.92 64.067 96.288 64.789 ;
     RECT  111.912 64.069 112.992 64.115 ;
     RECT  111.384 64.115 112.992 64.933 ;
     RECT  101.016 64.211 102.288 64.403 ;
     RECT  97.416 64.357 98.496 64.933 ;
     RECT  117 64.357 118.032 65.653 ;
     RECT  100.584 64.403 102.288 65.653 ;
     RECT  102.408 64.499 103.488 67.669 ;
     RECT  94.92 64.789 96 64.931 ;
     RECT  94.92 64.931 96.144 65.557 ;
     RECT  97.416 64.933 98.4 65.075 ;
     RECT  108.984 64.933 110.304 65.509 ;
     RECT  111.384 64.933 112.752 65.123 ;
     RECT  97.368 65.075 98.4 66.179 ;
     RECT  111.384 65.123 112.8 67.381 ;
     RECT  90.936 65.267 92.352 66.709 ;
     RECT  109.224 65.509 110.304 65.941 ;
     RECT  95.112 65.557 96.144 65.941 ;
     RECT  101.016 65.653 102.288 66.277 ;
     RECT  107.352 65.797 108.72 66.181 ;
     RECT  22.632 65.941 24 80.533 ;
     RECT  95.112 66.083 96.24 66.131 ;
     RECT  118.296 66.085 119.664 66.373 ;
     RECT  119.688 66.085 121.2 68.245 ;
     RECT  94.92 66.131 96.24 67.669 ;
     RECT  96.984 66.179 98.4 67.189 ;
     RECT  101.064 66.277 102.288 66.709 ;
     RECT  118.296 66.373 119.424 67.477 ;
     RECT  91.368 66.709 92.352 66.757 ;
     RECT  101.112 66.709 102.288 68.053 ;
     RECT  107.736 66.803 108.72 67.909 ;
     RECT  109.224 66.803 110.304 68.005 ;
     RECT  18.912 66.997 20.208 77.989 ;
     RECT  97.08 67.189 98.4 67.477 ;
     RECT  111.384 67.381 112.704 68.389 ;
     RECT  97.272 67.477 98.4 67.717 ;
     RECT  94.92 67.669 96.048 67.909 ;
     RECT  97.368 67.717 98.4 68.005 ;
     RECT  3.672 67.813 4.656 73.909 ;
     RECT  95.016 67.909 96.048 68.005 ;
     RECT  94.92 68.147 96.048 70.117 ;
     RECT  107.736 68.195 108.72 69.541 ;
     RECT  119.736 68.245 121.2 71.125 ;
     RECT  91.656 68.531 93.024 69.491 ;
     RECT  111.672 68.579 112.896 69.685 ;
     RECT  68.136 68.725 69.12 81.301 ;
     RECT  102.456 68.819 103.488 69.011 ;
     RECT  101.976 69.011 103.488 70.885 ;
     RECT  105.768 69.059 106.8 70.405 ;
     RECT  91.608 69.491 93.024 69.493 ;
     RECT  91.608 69.493 92.976 70.165 ;
     RECT  100.968 70.019 101.952 71.077 ;
     RECT  91.608 70.165 92.784 70.261 ;
     RECT  103.512 70.211 104.736 71.123 ;
     RECT  91.608 70.261 92.592 73.909 ;
     RECT  107.64 70.835 108.72 71.797 ;
     RECT  101.976 70.885 103.104 71.365 ;
     RECT  103.512 71.123 104.784 71.315 ;
     RECT  120.072 71.125 121.2 71.749 ;
     RECT  5.064 71.173 6.336 72.755 ;
     RECT  103.272 71.315 104.784 72.277 ;
     RECT  39.048 71.317 40.08 71.459 ;
     RECT  92.808 71.363 93.888 72.613 ;
     RECT  39.048 71.459 40.2 81.301 ;
     RECT  107.736 71.797 108.72 72.373 ;
     RECT  124.2 71.797 125.712 72.277 ;
     RECT  94.92 72.131 95.952 73.765 ;
     RECT  103.8 72.277 104.784 72.517 ;
     RECT  124.68 72.277 125.712 72.325 ;
     RECT  83.712 72.613 84.816 78.517 ;
     RECT  11.832 73.237 13.2 76.213 ;
     RECT  10.632 73.813 11.808 80.629 ;
     RECT  15.648 74.147 15.672 74.341 ;
     RECT  113.304 74.147 114.336 75.733 ;
     RECT  107.016 74.243 108 75.637 ;
     RECT  15.648 74.341 16.08 75.397 ;
     RECT  85.896 74.581 86.976 81.011 ;
     RECT  3.336 74.675 4.32 77.843 ;
     RECT  13.512 75.397 14.736 76.501 ;
     RECT  14.76 75.397 16.08 78.707 ;
     RECT  81.96 75.445 83.232 80.869 ;
     RECT  5.016 75.875 5.064 76.069 ;
     RECT  35.208 76.021 36.288 77.317 ;
     RECT  5.016 76.069 6.192 77.941 ;
     RECT  46.392 77.365 47.616 78.709 ;
     RECT  71.064 77.653 72.144 81.539 ;
     RECT  56.712 77.797 58.08 80.963 ;
     RECT  3.336 77.843 4.512 79.045 ;
     RECT  70.008 77.845 71.04 81.059 ;
     RECT  16.68 78.421 17.712 78.707 ;
     RECT  18.912 78.515 20.208 80.293 ;
     RECT  83.832 78.517 84.816 78.709 ;
     RECT  14.664 78.707 16.08 80.629 ;
     RECT  16.584 78.707 17.712 80.245 ;
     RECT  89.976 78.755 91.104 79.765 ;
     RECT  26.76 78.947 27.096 80.101 ;
     RECT  6.216 78.997 7.68 80.101 ;
     RECT  1.128 79.045 2.4 79.141 ;
     RECT  3.432 79.045 4.512 79.093 ;
     RECT  1.128 79.141 2.304 80.677 ;
     RECT  6.216 80.101 7.392 80.245 ;
     RECT  26.76 80.101 28.464 80.245 ;
     RECT  16.68 80.245 17.712 80.293 ;
     RECT  27.336 80.245 28.464 80.963 ;
     RECT  84.84 80.435 85.872 81.011 ;
     RECT  80.952 80.485 81.936 80.869 ;
     RECT  22.776 80.533 24 81.349 ;
     RECT  10.728 80.629 11.808 80.677 ;
     RECT  14.808 80.629 16.08 80.677 ;
     RECT  1.128 80.677 2.16 81.445 ;
     RECT  8.952 80.677 10.128 80.773 ;
     RECT  10.824 80.677 11.808 80.869 ;
     RECT  33.576 80.677 34.656 80.821 ;
     RECT  76.68 80.725 78 80.917 ;
     RECT  8.952 80.773 9.936 80.917 ;
     RECT  24.984 80.917 26.064 81.397 ;
     RECT  31.8 80.917 33.024 81.397 ;
     RECT  27.336 80.963 27.384 81.349 ;
     RECT  42.624 80.963 43.104 81.301 ;
     RECT  56.712 80.963 58.104 81.205 ;
     RECT  60.96 80.963 61.536 81.301 ;
     RECT  84.84 81.011 86.976 81.301 ;
     RECT  69.528 81.059 71.04 81.539 ;
     RECT  37.176 81.205 38.352 81.349 ;
     RECT  54.6 81.205 55.776 81.397 ;
     RECT  57.336 81.205 58.104 81.301 ;
     RECT  40.512 81.301 41.52 81.397 ;
     RECT  41.544 81.301 43.104 81.397 ;
     RECT  49.56 81.301 50.688 81.733 ;
     RECT  57.336 81.301 58.416 82.645 ;
     RECT  59.736 81.301 61.536 81.733 ;
     RECT  73.512 81.301 75.024 81.349 ;
     RECT  84.84 81.301 86.64 81.493 ;
     RECT  22.776 81.349 23.904 82.115 ;
     RECT  72.912 81.395 73.968 83.173 ;
     RECT  31.896 81.397 33.024 81.445 ;
     RECT  41.592 81.397 43.104 82.691 ;
     RECT  85.08 81.493 86.64 81.973 ;
     RECT  24.504 81.539 25.632 83.941 ;
     RECT  33.576 81.539 34.8 82.549 ;
     RECT  51.48 81.589 52.896 81.733 ;
     RECT  79.704 81.685 80.784 83.797 ;
     RECT  49.704 81.733 50.688 82.309 ;
     RECT  51.816 81.733 52.896 81.925 ;
     RECT  60.36 81.733 61.536 82.597 ;
     RECT  78.6 81.779 79.68 83.797 ;
     RECT  63.336 81.781 64.368 83.797 ;
     RECT  85.32 81.973 86.64 82.357 ;
     RECT  22.776 82.115 24 83.797 ;
     RECT  46.92 82.115 48.432 82.691 ;
     RECT  55.272 82.355 56.304 83.797 ;
     RECT  85.464 82.357 86.64 83.173 ;
     RECT  60.408 82.597 61.536 83.797 ;
     RECT  41.592 82.691 43.128 83.173 ;
     RECT  45.36 82.691 45.408 83.173 ;
     RECT  46.776 82.691 48.768 83.075 ;
     RECT  86.904 82.691 87.936 83.653 ;
     RECT  17.112 82.787 18.288 84.325 ;
     RECT  31.032 82.883 32.256 84.325 ;
     RECT  46.728 83.075 48.768 83.797 ;
     RECT  41.592 83.173 44.16 83.267 ;
     RECT  44.184 83.173 45.408 83.797 ;
     RECT  65.688 83.173 67.2 83.797 ;
     RECT  69.528 83.173 70.992 84.181 ;
     RECT  71.016 83.173 72.384 83.797 ;
     RECT  27.24 83.267 27.384 84.325 ;
     RECT  28.944 83.267 28.992 84.325 ;
     RECT  35.88 83.267 36.912 84.229 ;
     RECT  38.616 83.267 39.6 84.325 ;
     RECT  41.544 83.267 44.16 83.363 ;
     RECT  59.064 83.267 60.336 84.229 ;
     RECT  9.528 83.315 10.512 84.325 ;
     RECT  41.352 83.363 44.16 83.797 ;
     RECT  41.352 83.797 42.624 84.325 ;
     RECT  43.176 83.797 44.16 84.325 ;
     RECT  46.728 83.797 48.192 84.325 ;
  END
END ot_hgi_qdq_transport_rslice
END LIBRARY
